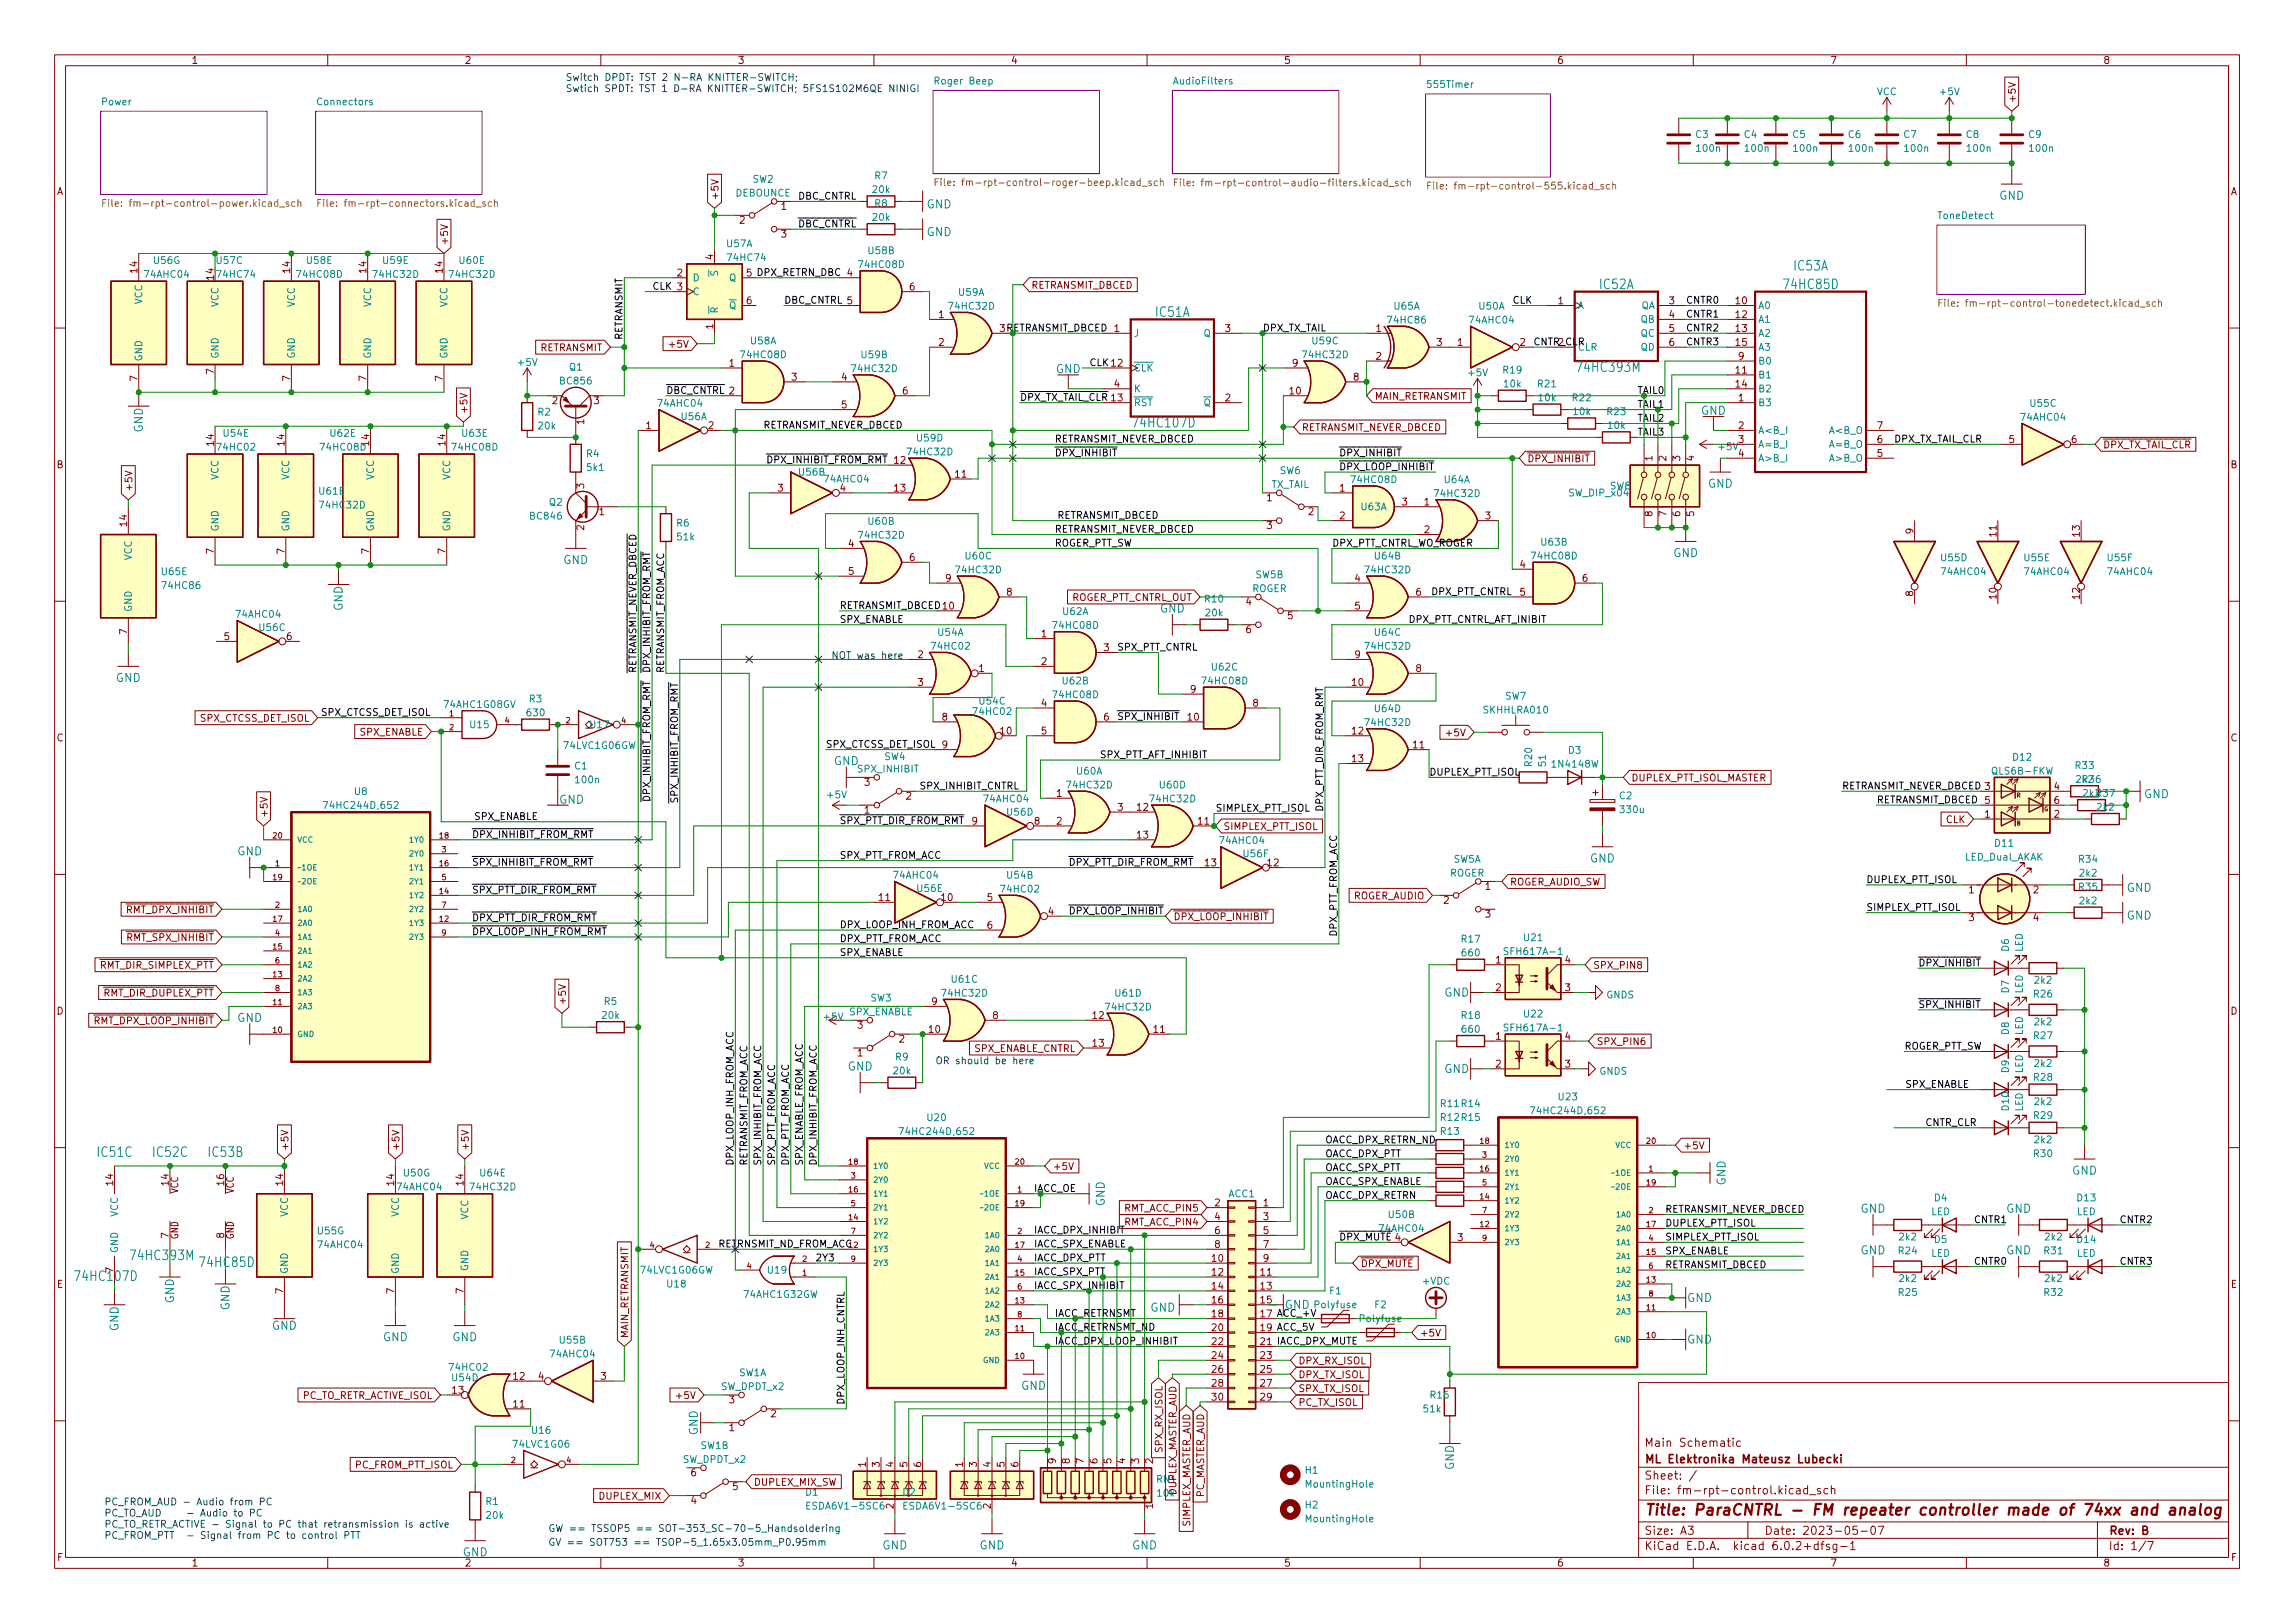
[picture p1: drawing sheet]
<svg xmlns="http://www.w3.org/2000/svg" width="420mm" height="297mm" viewBox="0 0 420 297" stroke-linecap="round" stroke-linejoin="round" font-family="sans-serif">
<defs><g id="words">
<text font-size="2.8" fill="#840000" x="301" y="277.3">Title: ParaCNTRL - FM repeater controller made of 74xx and analog</text>
<g font-size="2.5" fill="#008484">
<text x="292.9" y="52.9">IC52A</text>
<text x="326.8" y="52.9">74HC85D</text>
<text x="328.5" y="49.5">IC53A</text>
<text x="211.6" y="58">IC51A</text>
<text x="289.1" y="68.1">74HC393M</text>
<text x="207.8" y="78.2">74HC107D</text>
<text x="18" y="211.7">IC51C</text>
<text x="28.1" y="211.7">IC52C</text>
<text x="38.3" y="211.7">IC53B</text>
<text x="36.9" y="231.9">74HC85D</text>
<text x="14.1" y="234.4">74HC107D</text>
</g>
<text font-size="2.5" fill="#008400" x="24.3" y="230.6">74HC393M</text>
<g font-size="2.1" fill="#008484">
<text x="169.6" y="38.1">GND</text>
<text x="366" y="36.5">GND</text>
<text x="169.6" y="43.2">GND</text>
<text x="193.3" y="68.3">GND</text>
<text x="311.4" y="75.9">GND</text>
<text x="26.1" y="79.2" transform="rotate(-90 26.1 79.2)">GND</text>
<text x="312.6" y="89.3">GND</text>
<text x="306.3" y="102">GND</text>
<text x="103.1" y="103.2">GND</text>
<text x="62.7" y="111.8" transform="rotate(-90 62.7 111.8)">GND</text>
<text x="21.2" y="124.8">GND</text>
<text x="152.6" y="140">GND</text>
<text x="102.3" y="147.1">GND</text>
<text x="392.5" y="146.1">GND</text>
<text x="43.4" y="156.5">GND</text>
<text x="291.1" y="157.8">GND</text>
<text x="389.3" y="163.2">GND</text>
<text x="389.3" y="168.3">GND</text>
<text x="264.4" y="182.4">GND</text>
<text x="43.4" y="187">GND</text>
<text x="155.2" y="195.9">GND</text>
<text x="264.4" y="196.4">GND</text>
<text x="379.3" y="215">GND</text>
<text x="202.2" y="220.8" transform="rotate(-90 202.2 220.8)">GND</text>
<text x="315.9" y="217" transform="rotate(-90 315.9 217)">GND</text>
<text x="340.6" y="222">GND</text>
<text x="367.3" y="222">GND</text>
<text x="340.6" y="229.6">GND</text>
<text x="367.3" y="229.6">GND</text>
<text x="31.9" y="238.6" transform="rotate(-90 31.9 238.6)">GND</text>
<text x="42" y="239.8" transform="rotate(-90 42 239.8)">GND</text>
<text x="235.2" y="239.5">GND</text>
<text x="308.8" y="238.3">GND</text>
<text x="21.7" y="243.7" transform="rotate(-90 21.7 243.7)">GND</text>
<text x="49.8" y="243.4">GND</text>
<text x="70.1" y="245.5">GND</text>
<text x="82.8" y="245.5">GND</text>
<text x="210.6" y="240.1">GND</text>
<text x="308.8" y="245.9">GND</text>
<text x="186.9" y="254.4">GND</text>
<text x="127.7" y="262.7" transform="rotate(-90 127.7 262.7)">GND</text>
<text x="266.2" y="269.1" transform="rotate(-90 266.2 269.1)">GND</text>
<text x="84.7" y="284.8">GND</text>
<text x="161.5" y="283.6">GND</text>
<text x="179.3" y="283.6">GND</text>
<text x="207.2" y="283.6">GND</text>
</g>
<g font-size="2.1" fill="#840000">
<text x="212.3" y="112.1">GND</text>
<text x="301" y="267.8">ML Elektronika Mateusz Lubecki</text>
<text x="301" y="264.8">Main Schematic</text>
<text x="301" y="273.5">File: fm-rpt-control.kicad_sch</text>
<text x="301" y="270.8">Sheet: /</text>
<text x="301" y="280.9">Size: A3</text>
<text x="323" y="280.9">Date: 2023-05-07</text>
<text x="386" y="280.9">Rev: B</text>
<text x="301" y="283.7">KiCad E.D.A. kicad 6.0.2+dfsg-1</text>
<text x="386" y="283.7">Id: 1/7</text>
</g>
<g font-size="1.8" fill="#840000">
<text x="35" y="11.7">1</text>
<text x="85" y="11.7">2</text>
<text x="135" y="11.7">3</text>
<text x="185" y="11.7">4</text>
<text x="235" y="11.7">5</text>
<text x="285" y="11.7">6</text>
<text x="335" y="11.7">7</text>
<text x="385" y="11.7">8</text>
<text x="369" y="18.9" transform="rotate(-90 369 18.9)">+5V</text>
<text x="10.3" y="35.7">A</text>
<text x="408.3" y="35.7">A</text>
<text x="131.5" y="36.7" transform="rotate(-90 131.5 36.7)">+5V</text>
<text x="135.4" y="40.9">2</text>
<text x="143" y="38.4">1</text>
<text x="82" y="45" transform="rotate(-90 82 45)">+5V</text>
<text x="130.6" y="47.5" transform="rotate(-90 130.6 47.5)">4</text>
<text x="143" y="43.5">3</text>
<text x="25.1" y="49.9" transform="rotate(-90 25.1 49.9)">14</text>
<text x="39.1" y="51.2" transform="rotate(-90 39.1 51.2)">14</text>
<text x="53.1" y="49.9" transform="rotate(-90 53.1 49.9)">14</text>
<text x="67.1" y="49.9" transform="rotate(-90 67.1 49.9)">14</text>
<text x="81" y="49.9" transform="rotate(-90 81 49.9)">14</text>
<text x="124" y="50.6">2</text>
<text x="166.5" y="53.1">6</text>
<text x="188.8" y="52.8">RETRANSMIT_DBCED</text>
<text x="136.7" y="55.7">6</text>
<text x="171.8" y="58.2">1</text>
<text x="285.3" y="55.7">1</text>
<text x="305.6" y="55.7">3</text>
<text x="305.6" y="58.2">4</text>
<text x="317.8" y="55.7">10</text>
<text x="317.8" y="58.2">12</text>
<text x="98.7" y="64.3">RETRANSMIT</text>
<text x="123" y="63.6">+5V</text>
<text x="130.6" y="60.2" transform="rotate(-90 130.6 60.2)">1</text>
<text x="171.8" y="63.3">2</text>
<text x="224.3" y="60.7">3</text>
<text x="251.9" y="60.7">1</text>
<text x="251.9" y="65.8">2</text>
<text x="263" y="63.3">3</text>
<text x="266.8" y="63.3">1</text>
<text x="278.3" y="63.3">2</text>
<text x="305.6" y="60.7">5</text>
<text x="305.6" y="63.3">6</text>
<text x="317.8" y="60.7">13</text>
<text x="317.8" y="63.3">15</text>
<text x="318.3" y="65.8">9</text>
<text x="25.1" y="69.7" transform="rotate(-90 25.1 69.7)">7</text>
<text x="39.1" y="68.5" transform="rotate(-90 39.1 68.5)">7</text>
<text x="53.1" y="69.7" transform="rotate(-90 53.1 69.7)">7</text>
<text x="67.1" y="69.7" transform="rotate(-90 67.1 69.7)">7</text>
<text x="81" y="69.7" transform="rotate(-90 81 69.7)">7</text>
<text x="133.5" y="67.1">1</text>
<text x="144.9" y="69.6">3</text>
<text x="154.1" y="69.6">4</text>
<text x="204" y="70.9">4</text>
<text x="236.6" y="67.1">9</text>
<text x="247.8" y="69.6">8</text>
<text x="317.8" y="68.4">11</text>
<text x="317.8" y="70.9">14</text>
<text x="85.6" y="75.8" transform="rotate(-90 85.6 75.8)">+5V</text>
<text x="101.1" y="74">2</text>
<text x="106.9" y="77.7" transform="rotate(-90 106.9 77.7)">1</text>
<text x="108.7" y="74">3</text>
<text x="133.5" y="72.2">2</text>
<text x="154.1" y="74.7">5</text>
<text x="165.2" y="72.2">6</text>
<text x="203.5" y="73.4">13</text>
<text x="224.3" y="73.4">2</text>
<text x="236.1" y="72.2">10</text>
<text x="251.6" y="73.2">MAIN_RETRANSMIT</text>
<text x="318.3" y="73.4">1</text>
<text x="39.1" y="81.5" transform="rotate(-90 39.1 81.5)">14</text>
<text x="52.1" y="81.5" transform="rotate(-90 52.1 81.5)">14</text>
<text x="67.6" y="81.5" transform="rotate(-90 67.6 81.5)">14</text>
<text x="81.5" y="81.5" transform="rotate(-90 81.5 81.5)">14</text>
<text x="118.3" y="78.5">1</text>
<text x="129.7" y="78.5">2</text>
<text x="238.3" y="78.9">RETRANSMIT_NEVER_DBCED</text>
<text x="318.3" y="78.5">2</text>
<text x="318.3" y="81.1">3</text>
<text x="318.3" y="83.6">4</text>
<text x="343.7" y="83.6">5</text>
<text x="343.7" y="81.1">6</text>
<text x="343.7" y="78.5">7</text>
<text x="367.8" y="81.1">5</text>
<text x="379.2" y="81.1">6</text>
<text x="385" y="82">~{DPX_TX_TAIL_CLR}</text>
<text x="10.3" y="85.7">B</text>
<text x="106.9" y="89.4" transform="rotate(-90 106.9 89.4)">3</text>
<text x="142.4" y="90">3</text>
<text x="153.8" y="90">4</text>
<text x="163.7" y="90">13</text>
<text x="174.9" y="87.4">11</text>
<text x="245.3" y="90">1</text>
<text x="279.6" y="84.6">~{DPX_INHIBIT}</text>
<text x="302.5" y="84.3" transform="rotate(-90 302.5 84.3)">1</text>
<text x="305.1" y="84.3" transform="rotate(-90 305.1 84.3)">2</text>
<text x="307.6" y="84.3" transform="rotate(-90 307.6 84.3)">3</text>
<text x="310.1" y="84.3" transform="rotate(-90 310.1 84.3)">4</text>
<text x="408.3" y="85.7">B</text>
<text x="24.2" y="90" transform="rotate(-90 24.2 90)">+5V</text>
<text x="109.7" y="94.3">1</text>
<text x="231.9" y="91.7">1</text>
<text x="239.5" y="94.3">2</text>
<text x="245.3" y="95">2</text>
<text x="256.7" y="92.5">3</text>
<text x="260.7" y="92.5">1</text>
<text x="271.9" y="95">3</text>
<text x="302.5" y="94.5" transform="rotate(-90 302.5 94.5)">8</text>
<text x="305.1" y="94.5" transform="rotate(-90 305.1 94.5)">7</text>
<text x="307.6" y="94.5" transform="rotate(-90 307.6 94.5)">6</text>
<text x="310.1" y="94.5" transform="rotate(-90 310.1 94.5)">5</text>
<text x="23.2" y="96.3" transform="rotate(-90 23.2 96.3)">14</text>
<text x="39.1" y="101.4" transform="rotate(-90 39.1 101.4)">7</text>
<text x="52.1" y="101.4" transform="rotate(-90 52.1 101.4)">7</text>
<text x="67.6" y="101.4" transform="rotate(-90 67.6 101.4)">7</text>
<text x="81.5" y="101.4" transform="rotate(-90 81.5 101.4)">7</text>
<text x="106.9" y="97" transform="rotate(-90 106.9 97)">2</text>
<text x="155.3" y="100.1">4</text>
<text x="231.9" y="96.8">3</text>
<text x="260.7" y="97.6">2</text>
<text x="350.3" y="97.7" transform="rotate(-90 350.3 97.7)">9</text>
<text x="365.5" y="98.2" transform="rotate(-90 365.5 98.2)">11</text>
<text x="380.7" y="98.2" transform="rotate(-90 380.7 98.2)">13</text>
<text x="155.3" y="105.2">5</text>
<text x="166.5" y="102.7">6</text>
<text x="173.1" y="106.5">9</text>
<text x="248" y="106.5">4</text>
<text x="278.3" y="103.9">4</text>
<text x="289.7" y="106.5">6</text>
<text x="184.3" y="109">8</text>
<text x="195.8" y="110">ROGER_PTT_CNTRL_OUT</text>
<text x="228.1" y="110.8">4</text>
<text x="235.7" y="113.3">5</text>
<text x="248" y="111.5">5</text>
<text x="259.2" y="109">6</text>
<text x="278.3" y="109">5</text>
<text x="350.3" y="109.1" transform="rotate(-90 350.3 109.1)">8</text>
<text x="365.5" y="109.6" transform="rotate(-90 365.5 109.6)">10</text>
<text x="380.7" y="109.6" transform="rotate(-90 380.7 109.6)">12</text>
<text x="23.2" y="116.1" transform="rotate(-90 23.2 116.1)">7</text>
<text x="41" y="117.1">5</text>
<text x="52.5" y="117.1">6</text>
<text x="190.6" y="116.6">1</text>
<text x="202.1" y="119.2">3</text>
<text x="228.1" y="115.9">6</text>
<text x="168" y="120.4">2</text>
<text x="168" y="125.5">3</text>
<text x="179.2" y="123">1</text>
<text x="190.6" y="121.7">2</text>
<text x="247.6" y="125.5">10</text>
<text x="248" y="120.4">9</text>
<text x="259.2" y="123">8</text>
<text x="172.5" y="131.9">8</text>
<text x="190.6" y="129.3">4</text>
<text x="202.1" y="131.9">6</text>
<text x="217.9" y="126.8">9</text>
<text x="229.4" y="129.3">8</text>
<text x="10.3" y="135.7">C</text>
<text x="36.6" y="132.1">SPX_CTCSS_DET_ISOL</text>
<text x="65.8" y="134.6">SPX_ENABLE</text>
<text x="172.5" y="136.9">9</text>
<text x="183.2" y="134.4">10</text>
<text x="190.6" y="134.4">5</text>
<text x="247.6" y="134.4">12</text>
<text x="258.7" y="136.9">11</text>
<text x="265.2" y="134.7">+5V</text>
<text x="408.3" y="135.7">C</text>
<text x="158.3" y="143.8">3</text>
<text x="247.6" y="139.5">13</text>
<text x="298.6" y="143">DUPLEX_PTT_ISOL_MASTER</text>
<text x="49" y="149.7" transform="rotate(-90 49 149.7)">+5V</text>
<text x="158.3" y="148.9">1</text>
<text x="165.9" y="146.3">2</text>
<text x="193.4" y="145.8">1</text>
<text x="204.6" y="148.4">3</text>
<text x="208.2" y="148.4">12</text>
<text x="363.4" y="149.6">1</text>
<text x="376.1" y="149.6">2</text>
<text x="376.1" y="144.6">4</text>
<text x="376.1" y="147.1">6</text>
<text x="177.9" y="150.9">9</text>
<text x="189.4" y="150.9">8</text>
<text x="193.4" y="150.9">2</text>
<text x="208.2" y="153.5">13</text>
<text x="219.4" y="150.9">11</text>
<text x="223.9" y="151.9">SIMPLEX_PTT_ISOL</text>
<text x="356.3" y="150.6">CLK</text>
<text x="232.1" y="158.5">12</text>
<text x="22" y="167.1">~{RMT_DPX_INHIBIT}</text>
<text x="160.9" y="164.9">11</text>
<text x="172.4" y="164.9">10</text>
<text x="180.7" y="164.9">5</text>
<text x="191.9" y="167.4">4</text>
<text x="247.7" y="164.6">ROGER_AUDIO</text>
<text x="264.3" y="165.4">2</text>
<text x="271.9" y="162.9">1</text>
<text x="271.9" y="167.9">3</text>
<text x="276.4" y="162.1">ROGER_AUDIO_SW</text>
<text x="360.4" y="163.5">1</text>
<text x="372.3" y="163.5">2</text>
<text x="22.1" y="172.2">~{RMT_SPX_INHIBIT}</text>
<text x="180.7" y="170">6</text>
<text x="214.8" y="168.4">~{DPX_LOOP_INHIBIT}</text>
<text x="360.4" y="168.6">3</text>
<text x="372.3" y="168.6">4</text>
<text x="16.9" y="177.3">~{RMT_DIR_SIMPLEX_PTT}</text>
<text x="273.8" y="176.3">1</text>
<text x="286.5" y="176.3">4</text>
<text x="291.6" y="177.3">SPX_PIN8</text>
<text x="10.3" y="185.7">D</text>
<text x="17.5" y="182.4">~{RMT_DIR_DUPLEX_PTT}</text>
<text x="103.6" y="184" transform="rotate(-90 103.6 184)">+5V</text>
<text x="170.6" y="183.9">9</text>
<text x="273.8" y="181.4">2</text>
<text x="286.5" y="181.4">3</text>
<text x="408.3" y="185.7">D</text>
<text x="16" y="187.5">~{RMT_DPX_LOOP_INHIBIT}</text>
<text x="157" y="188.3">3</text>
<text x="164.6" y="190.8">2</text>
<text x="170.1" y="189">10</text>
<text x="181.8" y="186.5">8</text>
<text x="200.1" y="186.5">12</text>
<text x="200.1" y="191.6">13</text>
<text x="211.2" y="189">11</text>
<text x="273.8" y="190.3">1</text>
<text x="286.5" y="190.3">4</text>
<text x="292.3" y="191.3">SPX_PIN6</text>
<text x="157" y="193.3">1</text>
<text x="178.2" y="192.5">SPX_ENABLE_CNTRL</text>
<text x="273.8" y="195.4">2</text>
<text x="286.5" y="195.4">3</text>
<text x="52.8" y="210.7" transform="rotate(-90 52.8 210.7)">+5V</text>
<text x="73.1" y="210.7" transform="rotate(-90 73.1 210.7)">+5V</text>
<text x="85.8" y="210.7" transform="rotate(-90 85.8 210.7)">+5V</text>
<text x="192.7" y="214.1">+5V</text>
<text x="308.1" y="210.3">+5V</text>
<text x="20.7" y="216.9" transform="rotate(-90 20.7 216.9)">14</text>
<text x="30.9" y="216.9" transform="rotate(-90 30.9 216.9)">14</text>
<text x="32.6" y="218.5" transform="rotate(-90 32.6 218.5)">VCC</text>
<text x="41" y="216.9" transform="rotate(-90 41 216.9)">16</text>
<text x="42.8" y="218.5" transform="rotate(-90 42.8 218.5)">VCC</text>
<text x="51.8" y="216.9" transform="rotate(-90 51.8 216.9)">14</text>
<text x="72.1" y="216.9" transform="rotate(-90 72.1 216.9)">14</text>
<text x="84.8" y="216.9" transform="rotate(-90 84.8 216.9)">14</text>
<text x="206" y="221.7">RMT_ACC_PIN5</text>
<text x="222.4" y="220.8">2</text>
<text x="231.3" y="220.8">1</text>
<text x="30.9" y="226.6" transform="rotate(-90 30.9 226.6)">7</text>
<text x="32.6" y="226.8" transform="rotate(-90 32.6 226.8)">GND</text>
<text x="41" y="226.6" transform="rotate(-90 41 226.6)">8</text>
<text x="42.8" y="226.8" transform="rotate(-90 42.8 226.8)">GND</text>
<text x="206" y="224.3">RMT_ACC_PIN4</text>
<text x="222.4" y="223.3">4</text>
<text x="222.4" y="225.8">6</text>
<text x="231.3" y="223.3">3</text>
<text x="231.3" y="225.8">5</text>
<text x="255.4" y="227.1">4</text>
<text x="266.8" y="227.1">3</text>
<text x="20.7" y="232.9" transform="rotate(-90 20.7 232.9)">7</text>
<text x="221.9" y="230.9">10</text>
<text x="221.9" y="233.5">12</text>
<text x="222.4" y="228.4">8</text>
<text x="230.8" y="233.5">11</text>
<text x="231.3" y="228.4">7</text>
<text x="231.3" y="230.9">9</text>
<text x="249.1" y="231.9">~{DPX_MUTE}</text>
<text x="10.4" y="235.7">E</text>
<text x="51.8" y="236.7" transform="rotate(-90 51.8 236.7)">7</text>
<text x="72.1" y="236.7" transform="rotate(-90 72.1 236.7)">7</text>
<text x="84.8" y="236.7" transform="rotate(-90 84.8 236.7)">7</text>
<text x="221.9" y="236">14</text>
<text x="221.9" y="238.5">16</text>
<text x="230.8" y="236">13</text>
<text x="230.8" y="238.5">15</text>
<text x="408.4" y="235.7">E</text>
<text x="115" y="245" transform="rotate(-90 115 245)">MAIN_RETRANSMIT</text>
<text x="221.9" y="241.1">18</text>
<text x="221.9" y="243.6">20</text>
<text x="259.9" y="244.6">+5V</text>
<text x="221.9" y="246.2">22</text>
<text x="221.9" y="248.7">24</text>
<text x="221.9" y="251.2">26</text>
<text x="230.8" y="248.7">23</text>
<text x="230.8" y="251.2">25</text>
<text x="237.6" y="249.7">DPX_RX_ISOL</text>
<text x="54.9" y="256">PC_TO_RETR_ACTIVE_ISOL</text>
<text x="82.8" y="255.1">13</text>
<text x="94" y="257.6">11</text>
<text x="94" y="252.5">12</text>
<text x="98.6" y="252.5">4</text>
<text x="110" y="252.5">3</text>
<text x="124.3" y="256">+5V</text>
<text x="133.5" y="256.8">3</text>
<text x="221.9" y="253.8">28</text>
<text x="221.9" y="256.3">30</text>
<text x="230.8" y="253.8">27</text>
<text x="230.8" y="256.3">29</text>
<text x="237.6" y="254.8">SPX_TX_ISOL</text>
<text x="237.6" y="257.3">PC_TX_ISOL</text>
<text x="237.6" y="252.2">DPX_TX_ISOL</text>
<text x="133.5" y="261.9">1</text>
<text x="141.1" y="259.4">2</text>
<text x="64.9" y="268.7">PC_FROM_PTT_ISOL</text>
<text x="158.5" y="268.5" transform="rotate(-90 158.5 268.5)">1</text>
<text x="161" y="268.5" transform="rotate(-90 161 268.5)">3</text>
<text x="163.6" y="268.5" transform="rotate(-90 163.6 268.5)">4</text>
<text x="166.1" y="268.5" transform="rotate(-90 166.1 268.5)">5</text>
<text x="168.7" y="268.5" transform="rotate(-90 168.7 268.5)">6</text>
<text x="176.3" y="268.5" transform="rotate(-90 176.3 268.5)">1</text>
<text x="178.8" y="268.5" transform="rotate(-90 178.8 268.5)">3</text>
<text x="181.4" y="268.5" transform="rotate(-90 181.4 268.5)">4</text>
<text x="183.9" y="268.5" transform="rotate(-90 183.9 268.5)">5</text>
<text x="186.4" y="268.5" transform="rotate(-90 186.4 268.5)">6</text>
<text x="193.3" y="267.9" transform="rotate(-90 193.3 267.9)">9</text>
<text x="195.8" y="267.9" transform="rotate(-90 195.8 267.9)">8</text>
<text x="198.4" y="267.9" transform="rotate(-90 198.4 267.9)">7</text>
<text x="200.9" y="267.9" transform="rotate(-90 200.9 267.9)">6</text>
<text x="203.5" y="267.9" transform="rotate(-90 203.5 267.9)">5</text>
<text x="206" y="267.9" transform="rotate(-90 206 267.9)">4</text>
<text x="208.5" y="267.9" transform="rotate(-90 208.5 267.9)">3</text>
<text x="211.1" y="267.9" transform="rotate(-90 211.1 267.9)">2</text>
<text x="212.8" y="265.7" transform="rotate(-90 212.8 265.7)">SPX_RX_ISOL</text>
<text x="109.8" y="274.4">DUPLEX_MIX</text>
<text x="126.5" y="275.2">4</text>
<text x="126.5" y="270.2">6</text>
<text x="134.1" y="272.7">5</text>
<text x="138" y="271.9">DUPLEX_MIX_SW</text>
<text x="211.8" y="271.4">RN1</text>
<text x="211.9" y="273.9">10k</text>
<text x="215.4" y="274" transform="rotate(-90 215.4 274)">DUPLEX_MASTER_AUD</text>
<text x="220.4" y="274.4" transform="rotate(-90 220.4 274.4)">PC_MASTER_AUD</text>
<text x="163.6" y="276.1" transform="rotate(-90 163.6 276.1)">2</text>
<text x="181.4" y="276.1" transform="rotate(-90 181.4 276.1)">2</text>
<text x="211.1" y="276.1" transform="rotate(-90 211.1 276.1)">1</text>
<text x="217.9" y="279.7" transform="rotate(-90 217.9 279.7)">SIMPLEX_MASTER_AUD</text>
<text x="10.4" y="285.7">F</text>
<text x="35" y="286.7">1</text>
<text x="85" y="286.7">2</text>
<text x="135" y="286.7">3</text>
<text x="185" y="286.7">4</text>
<text x="235" y="286.7">5</text>
<text x="285" y="286.7">6</text>
<text x="335" y="286.7">7</text>
<text x="385" y="286.7">8</text>
<text x="408.4" y="285.7">F</text>
</g>
<g font-size="1.8" fill="#0000c2">
<text x="103.5" y="14.8">Switch DPDT: TST 2 N-RA KNITTER-SWITCH;</text>
<text x="103.5" y="16.8">Swtich SPDT: TST 1 D-RA KNITTER-SWITCH; 5FS1S102M6QE NINIGI</text>
<text x="152.1" y="120.6">NOT was here</text>
<text x="171.2" y="194.8">OR should be here</text>
<text x="19" y="275.5">PC_FROM_AUD - Audio from PC</text>
<text x="19" y="277.5">PC_TO_AUD - Audio to PC</text>
<text x="19" y="279.6">PC_TO_RETR_ACTIVE - Signal to PC that retransmission is active</text>
<text x="19" y="281.6">PC_FROM_PTT - Signal from PC to control PTT</text>
<text x="100.3" y="280.4">GW == TSSOP5 == SOT-353_SC-70-5_Handsoldering</text>
<text x="100.3" y="282.9">GV == SOT753 == TSOP-5_1.65x3.05mm_P0.95mm</text>
</g>
<g font-size="1.8" fill="#008484">
<text x="171.4" y="15.4">Roger Beep</text>
<text x="215.1" y="15.4">AudioFilters</text>
<text x="261.6" y="16.1">555Timer</text>
<text x="343.6" y="17.4">VCC</text>
<text x="355.3" y="17.4">+5V</text>
<text x="18.7" y="19.3">Power</text>
<text x="58.2" y="19.3">Connectors</text>
<text x="310.4" y="25.2">C3</text>
<text x="310.7" y="27.8">100n</text>
<text x="319.3" y="25.2">C4</text>
<text x="319.6" y="27.8">100n</text>
<text x="328.2" y="25.2">C5</text>
<text x="328.5" y="27.8">100n</text>
<text x="338.4" y="25.2">C6</text>
<text x="338.7" y="27.8">100n</text>
<text x="348.5" y="25.2">C7</text>
<text x="348.8" y="27.8">100n</text>
<text x="360" y="25.2">C8</text>
<text x="360.2" y="27.8">100n</text>
<text x="371.4" y="25.2">C9</text>
<text x="371.7" y="27.8">100n</text>
<text x="134.6" y="36">DEBOUNCE</text>
<text x="137.8" y="33.4">SW2</text>
<text x="159.8" y="35.3">20k</text>
<text x="160.2" y="32.8">R7</text>
<text x="159.8" y="40.4">20k</text>
<text x="160.2" y="37.9">R8</text>
<text x="355" y="40.1">ToneDetect</text>
<text x="133.1" y="45.2">U57A</text>
<text x="133.4" y="47.8">74HC74</text>
<text x="159" y="46.5">U58B</text>
<text x="26.6" y="50.8">74AHC04</text>
<text x="28.2" y="48.3">U56G</text>
<text x="39.9" y="50.8">74HC74</text>
<text x="54.5" y="50.8">74HC08D</text>
<text x="56.2" y="48.3">U58E</text>
<text x="68.5" y="50.8">74HC32D</text>
<text x="70.2" y="48.3">U59E</text>
<text x="82.5" y="50.8">74HC32D</text>
<text x="84.1" y="48.3">U60E</text>
<text x="126.7" y="51.5">D</text>
<text x="133.5" y="51.5">Q</text>
<text x="157.4" y="49">74HC08D</text>
<text x="26" y="55.7" transform="rotate(-90 26 55.7)">VCC</text>
<text x="40" y="56.2" transform="rotate(-90 40 56.2)">VCC</text>
<text x="54" y="56.2" transform="rotate(-90 54 56.2)">VCC</text>
<text x="67.9" y="56.2" transform="rotate(-90 67.9 56.2)">VCC</text>
<text x="81.9" y="56.2" transform="rotate(-90 81.9 56.2)">VCC</text>
<text x="126.7" y="54">C</text>
<text x="131.4" y="57.4" transform="rotate(-90 131.4 57.4)">~{R}</text>
<text x="132.1" y="56.6">~{Q}</text>
<text x="173.9" y="56.7">74HC32D</text>
<text x="175.5" y="54.1">U59A</text>
<text x="254.3" y="59.2">74HC86</text>
<text x="255.2" y="56.7">U65A</text>
<text x="269.2" y="59.2">74AHC04</text>
<text x="270.8" y="56.7">U50A</text>
<text x="288.8" y="56.6">A</text>
<text x="300.4" y="56.6">QA</text>
<text x="300.4" y="59.1">QB</text>
<text x="321.8" y="56.6">A0</text>
<text x="321.8" y="59.1">A1</text>
<text x="40" y="65.7" transform="rotate(-90 40 65.7)">GND</text>
<text x="54" y="65.7" transform="rotate(-90 54 65.7)">GND</text>
<text x="67.9" y="65.7" transform="rotate(-90 67.9 65.7)">GND</text>
<text x="81.9" y="65.7" transform="rotate(-90 81.9 65.7)">GND</text>
<text x="135.8" y="65.5">74HC08D</text>
<text x="137.4" y="63">U58A</text>
<text x="157.8" y="65.6">U59B</text>
<text x="207.5" y="61.6">J</text>
<text x="220.4" y="61.6">Q</text>
<text x="238.7" y="65.5">74HC32D</text>
<text x="240.3" y="63">U59C</text>
<text x="300.4" y="61.6">QC</text>
<text x="300.4" y="64.2">QD</text>
<text x="321.8" y="61.6">A2</text>
<text x="321.8" y="64.2">A3</text>
<text x="26" y="66.2" transform="rotate(-90 26 66.2)">GND</text>
<text x="94.9" y="66.9">+5V</text>
<text x="102.7" y="70.3">BC856</text>
<text x="104.2" y="67.8">Q1</text>
<text x="156.1" y="68.1">74HC32D</text>
<text x="207.5" y="68">~{CLK}</text>
<text x="207.5" y="71.8">K</text>
<text x="268.9" y="68.9">+5V</text>
<text x="275.2" y="68.3">R19</text>
<text x="275.4" y="70.9">10k</text>
<text x="281.6" y="70.9">R21</text>
<text x="321.8" y="69.3">B1</text>
<text x="321.8" y="71.8">B2</text>
<text x="321.8" y="66.7">B0</text>
<text x="98.5" y="76">R2</text>
<text x="120.6" y="74.4">74AHC04</text>
<text x="124.7" y="76.9">U56A</text>
<text x="207.5" y="74.3">~{RST}</text>
<text x="219" y="74.3">~{Q}</text>
<text x="281.7" y="73.4">10k</text>
<text x="287.9" y="73.4">R22</text>
<text x="288.1" y="76">10k</text>
<text x="294.3" y="76">R23</text>
<text x="321.8" y="74.3">B3</text>
<text x="370.1" y="77">74AHC04</text>
<text x="371.8" y="74.4">U55C</text>
<text x="39.9" y="82.5">74HC02</text>
<text x="41" y="79.9">U54E</text>
<text x="58.9" y="82.5">74HC08D</text>
<text x="60.5" y="79.9">U62E</text>
<text x="83" y="82.5">74HC08D</text>
<text x="84.7" y="79.9">U63E</text>
<text x="98.6" y="78.6">20k</text>
<text x="107.4" y="83.7">R4</text>
<text x="166.3" y="83.3">74HC32D</text>
<text x="167.9" y="80.8">U59D</text>
<text x="294.4" y="78.5">10k</text>
<text x="314.7" y="82.4">+5V</text>
<text x="321.8" y="79.4">A&lt;B_I</text>
<text x="321.8" y="82">A=B_I</text>
<text x="335.2" y="82">A=B_O</text>
<text x="335.2" y="79.4">A&lt;B_O</text>
<text x="40" y="87.8" transform="rotate(-90 40 87.8)">VCC</text>
<text x="53" y="87.8" transform="rotate(-90 53 87.8)">VCC</text>
<text x="68.5" y="87.8" transform="rotate(-90 68.5 87.8)">VCC</text>
<text x="82.4" y="87.8" transform="rotate(-90 82.4 87.8)">VCC</text>
<text x="107.5" y="86.2">5k1</text>
<text x="146.3" y="87">U56B</text>
<text x="151.1" y="88.3">74AHC04</text>
<text x="232.6" y="89.3">TX_TAIL</text>
<text x="234.3" y="86.8">SW6</text>
<text x="247.6" y="88.4">74HC08D</text>
<text x="264.4" y="88.4">U64A</text>
<text x="294.7" y="89.6">SW8</text>
<text x="321.8" y="84.5">A&gt;B_I</text>
<text x="335.2" y="84.5">A&gt;B_O</text>
<text x="58.5" y="90.5">U61E</text>
<text x="58.7" y="93.1">74HC32D</text>
<text x="97.2" y="95.1">BC846</text>
<text x="100.6" y="92.5">Q2</text>
<text x="249.2" y="93.4">U63A</text>
<text x="262.8" y="90.9">74HC32D</text>
<text x="287.3" y="90.8">SW_DIP_x04</text>
<text x="40" y="97.3" transform="rotate(-90 40 97.3)">GND</text>
<text x="53" y="97.3" transform="rotate(-90 53 97.3)">GND</text>
<text x="68.5" y="97.3" transform="rotate(-90 68.5 97.3)">GND</text>
<text x="82.4" y="97.3" transform="rotate(-90 82.4 97.3)">GND</text>
<text x="123.9" y="96.4">R6</text>
<text x="124" y="98.9">51k</text>
<text x="157.4" y="98.6">74HC32D</text>
<text x="159" y="96">U60B</text>
<text x="282.2" y="99.8">U63B</text>
<text x="24.1" y="102.6" transform="rotate(-90 24.1 102.6)">VCC</text>
<text x="29.7" y="105.2">U65E</text>
<text x="29.9" y="107.8">74HC86</text>
<text x="175.2" y="104.9">74HC32D</text>
<text x="176.8" y="102.4">U60C</text>
<text x="229.9" y="105.8">SW5B</text>
<text x="250.1" y="104.9">74HC32D</text>
<text x="251.7" y="102.4">U64B</text>
<text x="280.6" y="102.4">74HC08D</text>
<text x="355.4" y="102.7">U55D</text>
<text x="355.6" y="105.2">74AHC04</text>
<text x="370.6" y="102.7">U55E</text>
<text x="370.8" y="105.2">74AHC04</text>
<text x="385.9" y="102.7">U55F</text>
<text x="386" y="105.2">74AHC04</text>
<text x="24.1" y="112.1" transform="rotate(-90 24.1 112.1)">GND</text>
<text x="43.4" y="113">74AHC04</text>
<text x="194.6" y="112.5">U62A</text>
<text x="220.6" y="110.3">R10</text>
<text x="220.8" y="112.8">20k</text>
<text x="229.2" y="108.3">ROGER</text>
<text x="47.5" y="115.5">U56C</text>
<text x="170.7" y="118.9">74HC02</text>
<text x="171.7" y="116.4">U54A</text>
<text x="193" y="115.1">74HC08D</text>
<text x="250.1" y="118.9">74HC32D</text>
<text x="251.7" y="116.4">U64C</text>
<text x="194.6" y="125.2">U62B</text>
<text x="220.3" y="125.2">74HC08D</text>
<text x="221.9" y="122.7">U62C</text>
<text x="81.4" y="129.6">74AHC1G08GV</text>
<text x="96.6" y="131.1">630</text>
<text x="96.9" y="128.5">R3</text>
<text x="178.4" y="130.8">74HC02</text>
<text x="179.3" y="128.9">U54C</text>
<text x="193" y="127.8">74HC08D</text>
<text x="251.7" y="130.3">U64D</text>
<text x="271.7" y="130.6">SKHHLRA010</text>
<text x="275.6" y="128">SW7</text>
<text x="86.1" y="133.3">U15</text>
<text x="103.3" y="137.1">74LVC1G06GW</text>
<text x="108.1" y="133.3">U17</text>
<text x="250.1" y="132.9">74HC32D</text>
<text x="287.2" y="137.9">D3</text>
<text x="105.2" y="140.8">C1</text>
<text x="105.5" y="143.3">100n</text>
<text x="157.1" y="141.4">SPX_INHIBIT</text>
<text x="161.9" y="139.1">SW4</text>
<text x="197.1" y="141.8">U60A</text>
<text x="280.5" y="140.2" transform="rotate(-90 280.5 140.2)">R20</text>
<text x="283" y="140.2" transform="rotate(-90 283 140.2)">51</text>
<text x="284.4" y="140.5">1N4148W</text>
<text x="364.9" y="141.7">QLS6B-FKW</text>
<text x="368.6" y="139.2">D12</text>
<text x="380" y="140.7">R33</text>
<text x="380.2" y="143.3">2k2</text>
<text x="59.9" y="148">74HC244D,652</text>
<text x="64.9" y="145.5">U8</text>
<text x="151.5" y="146.1">+5V</text>
<text x="180.3" y="146.8">74AHC04</text>
<text x="184.4" y="149.3">U56D</text>
<text x="195.5" y="144.3">74HC32D</text>
<text x="210.7" y="146.8">74HC32D</text>
<text x="212.4" y="144.3">U60D</text>
<text x="296.5" y="146.3">C2</text>
<text x="296.7" y="148.8">330u</text>
<text x="381.4" y="145.8">2k2R37</text>
<text x="384" y="148.4">2k2</text>
<text x="223.4" y="154.4">74AHC04</text>
<text x="365.3" y="155">D11</text>
<text x="163.8" y="160.8">74AHC04</text>
<text x="184.4" y="160.8">U54B</text>
<text x="227.7" y="156.9">U56F</text>
<text x="265.4" y="160.4">ROGER</text>
<text x="266" y="157.9">SW5A</text>
<text x="359.7" y="157.5">LED_Dual_AKAK</text>
<text x="380.6" y="157.9">R34</text>
<text x="380.8" y="160.4">2k2</text>
<text x="168" y="163.2">U56E</text>
<text x="183.4" y="163.3">74HC02</text>
<text x="380.6" y="163">R35</text>
<text x="380.8" y="165.5">2k2</text>
<text x="267.6" y="172.5">R17</text>
<text x="279" y="172.2">U21</text>
<text x="174.3" y="179.9">U61C</text>
<text x="267.8" y="175">660</text>
<text x="276" y="174.8">SFH617A-1</text>
<text x="367.8" y="174.1" transform="rotate(-90 367.8 174.1)">D6</text>
<text x="370.3" y="174.2" transform="rotate(-90 370.3 174.2)">LED</text>
<text x="110.6" y="183.9">R5</text>
<text x="155.4" y="185.8">SPX_ENABLE</text>
<text x="159.4" y="183.3">SW3</text>
<text x="172.6" y="182.4">74HC32D</text>
<text x="202.6" y="184.9">74HC32D</text>
<text x="204.2" y="182.4">U61D</text>
<text x="294.1" y="182.7">GNDS</text>
<text x="367.8" y="181.7" transform="rotate(-90 367.8 181.7)">D7</text>
<text x="370.3" y="181.9" transform="rotate(-90 370.3 181.9)">LED</text>
<text x="372.4" y="182.6">R26</text>
<text x="372.5" y="180">2k2</text>
<text x="110.3" y="186.5">20k</text>
<text x="150.9" y="186.7">+5V</text>
<text x="267.6" y="186.5">R18</text>
<text x="267.8" y="189">660</text>
<text x="276" y="188.7">SFH617A-1</text>
<text x="279" y="186.2">U22</text>
<text x="367.8" y="189.3" transform="rotate(-90 367.8 189.3)">D8</text>
<text x="370.3" y="189.5" transform="rotate(-90 370.3 189.5)">LED</text>
<text x="372.4" y="190.2">R27</text>
<text x="372.5" y="187.6">2k2</text>
<text x="163.6" y="196.6">20k</text>
<text x="164" y="194.1">R9</text>
<text x="292.8" y="196.7">GNDS</text>
<text x="367.8" y="196.3" transform="rotate(-90 367.8 196.3)">D9</text>
<text x="370.3" y="196.5" transform="rotate(-90 370.3 196.5)">LED</text>
<text x="372.4" y="197.8">R28</text>
<text x="372.5" y="195.3">2k2</text>
<text x="263.8" y="202.6">R11 R14</text>
<text x="280.9" y="203.9">74HC244D,652</text>
<text x="285.4" y="201.4">U23</text>
<text x="367.8" y="203.2" transform="rotate(-90 367.8 203.2)">D10</text>
<text x="370.3" y="203.5" transform="rotate(-90 370.3 203.5)">LED</text>
<text x="372.5" y="202.2">2k2</text>
<text x="165.4" y="207.7">74HC244D,652</text>
<text x="169.8" y="205.2">U20</text>
<text x="263.8" y="207.7">R13</text>
<text x="263.8" y="205.1">R12 R15</text>
<text x="372.4" y="204.8">R29</text>
<text x="372.5" y="209.2">2k2</text>
<text x="73.9" y="215.3">U50G</text>
<text x="88" y="215.3">U64E</text>
<text x="372.4" y="211.8">R30</text>
<text x="72.9" y="217.8">74AHC04</text>
<text x="86.3" y="217.8">74HC32D</text>
<text x="224.9" y="219.1">ACC1</text>
<text x="354.2" y="219.9">D4</text>
<text x="380.3" y="219.9">D13</text>
<text x="21.6" y="222.7" transform="rotate(-90 21.6 222.7)">VCC</text>
<text x="52.7" y="222.7" transform="rotate(-90 52.7 222.7)">VCC</text>
<text x="58.2" y="225.9">U55G</text>
<text x="73" y="222.7" transform="rotate(-90 73 222.7)">VCC</text>
<text x="85.7" y="223.2" transform="rotate(-90 85.7 223.2)">VCC</text>
<text x="254.3" y="222.9">U50B</text>
<text x="347.8" y="227">2k2</text>
<text x="353.5" y="222.4">LED</text>
<text x="354.2" y="227.5">D5</text>
<text x="374.4" y="227">2k2</text>
<text x="380.2" y="222.4">LED</text>
<text x="380.3" y="227.5">D14</text>
<text x="21.6" y="229.4" transform="rotate(-90 21.6 229.4)">GND</text>
<text x="52.7" y="233.2" transform="rotate(-90 52.7 233.2)">GND</text>
<text x="58.4" y="228.4">74AHC04</text>
<text x="73" y="233.2" transform="rotate(-90 73 233.2)">GND</text>
<text x="85.7" y="232.7" transform="rotate(-90 85.7 232.7)">GND</text>
<text x="117.4" y="233.1">74LVC1G06GW</text>
<text x="140.6" y="233.1">U19</text>
<text x="347.6" y="229.5">R24</text>
<text x="353.5" y="230">LED</text>
<text x="374.3" y="229.5">R31</text>
<text x="380.2" y="230">LED</text>
<text x="122.2" y="235.6">U18</text>
<text x="136.3" y="237.5">74AHC1G32GW</text>
<text x="240.8" y="239.4">Polyfuse</text>
<text x="243.4" y="236.9">F1</text>
<text x="251.7" y="239.4">F2</text>
<text x="260.5" y="235.1">+VDC</text>
<text x="347.6" y="237.2">R25</text>
<text x="347.8" y="234.6">2k2</text>
<text x="374.3" y="237.2">R32</text>
<text x="374.4" y="234.6">2k2</text>
<text x="102.5" y="245.9">U55B</text>
<text x="249" y="242">Polyfuse</text>
<text x="82.5" y="250.9">74HC02</text>
<text x="100.9" y="248.4">74AHC04</text>
<text x="135.2" y="251.9">SW1A</text>
<text x="82.8" y="252.8">U54D</text>
<text x="132" y="254.4">SW_DPDT_x2</text>
<text x="261.9" y="255.9">R16</text>
<text x="97.4" y="262.4">U16</text>
<text x="260.7" y="258.5">51k</text>
<text x="94.1" y="264.9">74LVC1G06</text>
<text x="125" y="267.7">SW_DPDT_x2</text>
<text x="128.3" y="265.2">SW1B</text>
<text x="239" y="269.7">H1</text>
<text x="89" y="275.4">R1</text>
<text x="147.5" y="273.7">D1</text>
<text x="165.3" y="273.7">D2</text>
<text x="239.3" y="272.2">MountingHole</text>
<text x="89.1" y="278">20k</text>
<text x="148.2" y="276.3">ESDA6V1-5SC6</text>
<text x="166" y="276.3">ESDA6V1-5SC6</text>
<text x="239" y="276.1">H2</text>
<text x="239.3" y="278.6">MountingHole</text>
</g>
<g font-size="1.8" fill="#848400">
<text x="174.7" y="34">File: fm-rpt-control-roger-beep.kicad_sch</text>
<text x="218.8" y="34.1">File: fm-rpt-control-audio-filters.kicad_sch</text>
<text x="264.4" y="34.7">File: fm-rpt-control-555.kicad_sch</text>
<text x="21.6" y="37.8">File: fm-rpt-control-power.kicad_sch</text>
<text x="60.4" y="37.8">File: fm-rpt-connectors.kicad_sch</text>
<text x="358.1" y="56.1">File: fm-rpt-control-tonedetect.kicad_sch</text>
</g>
<g font-size="1.8">
<text x="146" y="41.6">~{DBC_CNTRL}</text>
<text x="146" y="36.5">DBC_CNTRL</text>
<text x="119.4" y="53">CLK 3</text>
<text x="136.7" y="50.6">5 DPX_RETRN_DBC 4</text>
<text x="143.5" y="55.6">DBC_CNTRL 5</text>
<text x="276.9" y="55.6">CLK</text>
<text x="308.6" y="58.1">CNTR1</text>
<text x="308.6" y="55.6">CNTR0</text>
<text x="114" y="62.3" transform="rotate(-90 114 62.3)">RETRANSMIT</text>
<text x="285.3" y="63.3">2</text>
<text x="288.8" y="64.2">CLR</text>
<text x="308.6" y="63.2">CNTR3</text>
<text x="308.6" y="60.6">CNTR2</text>
<text x="199.4" y="67">CLK 12</text>
<text x="121.9" y="72.1">~{DBC_CNTRL}</text>
<text x="186.7" y="73.3">~{DPX_TX_TAIL_CLR}</text>
<text x="299.7" y="77.2">TAIL2</text>
<text x="299.7" y="74.6">TAIL1</text>
<text x="299.7" y="72.1">TAIL0</text>
<text x="139.7" y="78.4">RETRANSMIT_NEVER_DBCED</text>
<text x="193" y="83.5">~{DPX_INHIBIT}</text>
<text x="193" y="81">RETRANSMIT_NEVER_DBCED</text>
<text x="245.1" y="83.5">~{DPX_INHIBIT}</text>
<text x="299.7" y="79.7">TAIL3</text>
<text x="346.7" y="81">DPX_TX_TAIL_CLR</text>
<text x="139.2" y="84.8">~{DPX_INHIBIT_FROM_RMT} 12</text>
<text x="245.1" y="86">~{DPX_LOOP_INHIBIT}</text>
<text x="193.5" y="94.9">RETRANSMIT_DBCED</text>
<text x="193" y="97.5">RETRANSMIT_NEVER_DBCED</text>
<text x="193" y="100">ROGER_PTT_SW</text>
<text x="243.8" y="100">DPX_PTT_CNTRL_WO_ROGER</text>
<text x="153.7" y="114">SPX_ENABLE</text>
<text x="153.7" y="111.4">RETRANSMIT_DBCED10</text>
<text x="257.8" y="114">DPX_PTT_CNTRL_AFT_INIBIT</text>
<text x="261.9" y="108.9">DPX_PTT_CNTRL</text>
<text x="204.5" y="119.1">SPX_PTT_CNTRL</text>
<text x="116.5" y="123.2" transform="rotate(-90 116.5 123.2)">~{RETRANSMIT_NEVER_DBCED}</text>
<text x="121.6" y="123.2" transform="rotate(-90 121.6 123.2)">RETRANSMIT_FROM_ACC</text>
<text x="58.7" y="131">SPX_CTCSS_DET_ISOL</text>
<text x="204.5" y="131.8">~{SPX_INHIBIT}10</text>
<text x="151.1" y="136.8">SPX_CTCSS_DET_ISOL</text>
<text x="201.3" y="138.8">SPX_PTT_AFT_INHIBIT</text>
<text x="261.6" y="141.9">DUPLEX_PTT_ISOL</text>
<text x="119" y="146.8" transform="rotate(-90 119 146.8)">~{DPX_INHIBIT_FROM_RMT}~{DPX_INHIBIT_FROM_RMT}</text>
<text x="124.1" y="147.1" transform="rotate(-90 124.1 147.1)">~{SPX_INHIBIT_FROM_RMT}</text>
<text x="168.3" y="144.5">SPX_INHIBIT_CNTRL</text>
<text x="222.5" y="148.5">SIMPLEX_PTT_ISOL</text>
<text x="242.2" y="148.6" transform="rotate(-90 242.2 148.6)">DPX_PTT_DIR_FROM_RMT</text>
<text x="337.2" y="144.5">RETRANSMIT_NEVER_DBCED 3</text>
<text x="343.5" y="147">RETRANSMIT_DBCED 5</text>
<text x="86.4" y="153.4">~{DPX_INHIBIT_FROM_RMT}</text>
<text x="86.8" y="150.1">SPX_ENABLE</text>
<text x="153.7" y="150.8">~{SPX_PTT_DIR_FROM_RMT}</text>
<text x="86.4" y="158.4">~{SPX_INHIBIT_FROM_RMT}</text>
<text x="153.7" y="157.2">SPX_PTT_FROM_ACC</text>
<text x="195.6" y="158.4">~{DPX_PTT_DIR_FROM_RMT}13</text>
<text x="341.6" y="161.6">DUPLEX_PTT_ISOL</text>
<text x="86.4" y="163.5">~{SPX_PTT_DIR_FROM_RMT}</text>
<text x="195.6" y="167.3">~{DPX_LOOP_INHIBIT}</text>
<text x="341.6" y="166.7">SIMPLEX_PTT_ISOL</text>
<text x="86.4" y="168.6">~{DPX_PTT_DIR_FROM_RMT}</text>
<text x="86.4" y="171.1">~{DPX_LOOP_INH_FROM_RMT}</text>
<text x="153.7" y="172.4">DPX_PTT_FROM_ACC</text>
<text x="153.7" y="169.9">DPX_LOOP_INH_FROM_ACC</text>
<text x="244.8" y="171.5" transform="rotate(-90 244.8 171.5)">DPX_PTT_FROM_ACC</text>
<text x="153.7" y="174.9">SPX_ENABLE</text>
<text x="351.2" y="176.9">~{DPX_INHIBIT}</text>
<text x="351.2" y="184.5">~{SPX_INHIBIT}</text>
<text x="348.6" y="192.1">ROGER_PTT_SW</text>
<text x="348.7" y="199.1">SPX_ENABLE</text>
<text x="242.6" y="209.2">OACC_DPX_RETRN_ND</text>
<text x="352.4" y="206.1">CNTR_CLR</text>
<text x="134.3" y="213.4" transform="rotate(-90 134.3 213.4)">DPX_LOOP_INH_FROM_ACC</text>
<text x="136.8" y="213.4" transform="rotate(-90 136.8 213.4)">RETRANSMIT_FROM_ACC</text>
<text x="139.4" y="213.4" transform="rotate(-90 139.4 213.4)">SPX_INHIBIT_FROM_ACC</text>
<text x="141.9" y="213.4" transform="rotate(-90 141.9 213.4)">SPX_PTT_FROM_ACC</text>
<text x="144.4" y="213.4" transform="rotate(-90 144.4 213.4)">DPX_PTT_FROM_ACC</text>
<text x="147" y="213.4" transform="rotate(-90 147 213.4)">SPX_ENABLE_FROM_ACC</text>
<text x="149.5" y="213.4" transform="rotate(-90 149.5 213.4)">DPX_INHIBIT_FROM_ACC</text>
<text x="242.6" y="214.3">OACC_SPX_PTT</text>
<text x="242.6" y="211.8">OACC_DPX_PTT</text>
<text x="242.6" y="216.9">OACC_SPX_ENABLE</text>
<text x="242.6" y="219.4">OACC_DPX_RETRN</text>
<text x="304.8" y="221.9">RETRANSMIT_NEVER_DBCED</text>
<text x="189.2" y="225.7">IACC_DPX_INHIBIT</text>
<text x="245.1" y="227">~{DPX_MUTE}</text>
<text x="252.7" y="225.5">74AHC04</text>
<text x="304.8" y="224.5">DUPLEX_PTT_ISOL</text>
<text x="304.8" y="227">SIMPLEX_PTT_ISOL</text>
<text x="361.3" y="223.8">CNTR1</text>
<text x="388" y="223.8">CNTR2</text>
<text x="131.4" y="228.3">RETRNSMIT_ND_FROM_ACC</text>
<text x="149.2" y="230.8">2Y3</text>
<text x="189.2" y="228.3">IACC_SPX_ENABLE</text>
<text x="189.2" y="230.8">IACC_DPX_PTT</text>
<text x="304.8" y="229.6">SPX_ENABLE</text>
<text x="304.8" y="232.1">RETRANSMIT_DBCED</text>
<text x="361.3" y="231.5">CNTR0</text>
<text x="388" y="231.5">CNTR3</text>
<text x="230.8" y="241.1">17 ACC_+V</text>
<text x="230.8" y="243.6">19 ACC_5V</text>
<text x="193" y="246.1">IACC_DPX_LOOP_INHIBIT</text>
<text x="230.8" y="246.2">21 IACC_DPX_MUTE</text>
<text x="154.6" y="256.9" transform="rotate(-90 154.6 256.9)">DPX_LOOP_INH_CNTRL</text>
</g>
<g font-size="1.8" fill="#008400">
<text x="39.7" y="48.3">U57C</text>
<text x="183" y="60.7">3RETRANSMIT_DBCED 1</text>
<text x="231.1" y="60.6">DPX_TX_TAIL</text>
<text x="280.7" y="63.2">CNTR_CLR</text>
<text x="189.2" y="218.1">IACC_OE</text>
<text x="189.2" y="233.4">IACC_SPX_PTT</text>
<text x="189.2" y="235.9">IACC_SPX_INHIBIT</text>
<text x="193" y="243.5">IACC_RETRNSMT_ND</text>
<text x="193" y="241">IACC_RETRNSMT</text>
</g>
<g font-size="1.4" fill="#840000">
<text x="82.3" y="131.1">1</text>
<text x="82.3" y="133.6">2</text>
<text x="92.4" y="132.4">4</text>
<text x="103.6" y="132.4">2</text>
<text x="113.8" y="132.4">4</text>
<text x="50" y="153.5">20</text>
<text x="80.5" y="153.5">18</text>
<text x="80.9" y="156">3</text>
<text x="50" y="161.1">19</text>
<text x="50.4" y="158.5">1</text>
<text x="80.5" y="158.5">16</text>
<text x="80.9" y="161.1">5</text>
<text x="50.4" y="166.2">2</text>
<text x="80.5" y="163.6">14</text>
<text x="80.9" y="166.2">7</text>
<text x="50" y="173.8">15</text>
<text x="50" y="168.7">17</text>
<text x="50.4" y="171.2">4</text>
<text x="80.5" y="168.7">12</text>
<text x="80.9" y="171.2">9</text>
<text x="50" y="178.9">13</text>
<text x="50.4" y="176.3">6</text>
<text x="50" y="183.9">11</text>
<text x="50.4" y="181.4">8</text>
<text x="50" y="189">10</text>
<text x="271" y="209.3">18</text>
<text x="301.5" y="209.3">20</text>
<text x="155.4" y="213.1">18</text>
<text x="155.8" y="215.7">3</text>
<text x="185.9" y="213.1">20</text>
<text x="271" y="214.4">16</text>
<text x="271.4" y="211.9">3</text>
<text x="301.9" y="214.4">1</text>
<text x="155.4" y="218.2">16</text>
<text x="155.8" y="220.8">5</text>
<text x="185.9" y="220.8">19</text>
<text x="186.3" y="218.2">1</text>
<text x="271" y="219.5">14</text>
<text x="271.4" y="217">5</text>
<text x="301.5" y="217">19</text>
<text x="155.4" y="223.3">14</text>
<text x="155.8" y="225.8">7</text>
<text x="186.3" y="225.8">2</text>
<text x="271" y="224.6">12</text>
<text x="271.4" y="222">7</text>
<text x="271.4" y="227.1">9</text>
<text x="301.5" y="224.6">17</text>
<text x="301.9" y="222">2</text>
<text x="301.9" y="227.1">4</text>
<text x="119" y="228.4">4</text>
<text x="129.1" y="228.4">2</text>
<text x="136.8" y="232.2">4</text>
<text x="146.9" y="233.5">1</text>
<text x="146.9" y="230.9">2</text>
<text x="155.4" y="228.4">12</text>
<text x="155.8" y="230.9">9</text>
<text x="185.9" y="233.5">15</text>
<text x="185.9" y="228.4">17</text>
<text x="186.3" y="230.9">4</text>
<text x="301.5" y="229.7">15</text>
<text x="301.9" y="232.2">6</text>
<text x="185.9" y="238.5">13</text>
<text x="186.3" y="236">6</text>
<text x="301.5" y="239.8">11</text>
<text x="301.5" y="234.7">13</text>
<text x="301.9" y="237.3">8</text>
<text x="185.9" y="243.6">11</text>
<text x="186.3" y="241.1">8</text>
<text x="301.5" y="244.9">10</text>
<text x="185.9" y="248.7">10</text>
<text x="93.6" y="267.8">2</text>
<text x="103.7" y="267.8">4</text>
</g>
<g font-size="1.4" fill="#008484">
<text x="54.4" y="154.2">VCC</text>
<text x="75.2" y="154.2">1Y0</text>
<text x="54.4" y="159.3">~1OE</text>
<text x="54.4" y="161.8">~2OE</text>
<text x="75.2" y="159.3">1Y1</text>
<text x="75.2" y="156.8">2Y0</text>
<text x="75.2" y="161.8">2Y1</text>
<text x="54.4" y="166.9">1A0</text>
<text x="75.2" y="164.4">1Y2</text>
<text x="75.2" y="166.9">2Y2</text>
<text x="54.4" y="169.5">2A0</text>
<text x="54.4" y="172">1A1</text>
<text x="75.2" y="169.5">1Y3</text>
<text x="75.2" y="172">2Y3</text>
<text x="54.4" y="179.6">2A2</text>
<text x="54.4" y="174.5">2A1</text>
<text x="54.4" y="177.1">1A2</text>
<text x="54.4" y="184.7">2A3</text>
<text x="54.4" y="182.2">1A3</text>
<text x="54.4" y="189.8">GND</text>
<text x="159.8" y="213.9">1Y0</text>
<text x="180.1" y="213.9">VCC</text>
<text x="275.3" y="215.2">1Y1</text>
<text x="275.3" y="210.1">1Y0</text>
<text x="275.3" y="212.6">2Y0</text>
<text x="295.7" y="210.1">VCC</text>
<text x="295.9" y="215.2">~1OE</text>
<text x="159.8" y="219">1Y1</text>
<text x="159.8" y="216.4">2Y0</text>
<text x="159.8" y="221.5">2Y1</text>
<text x="180.3" y="219">~1OE</text>
<text x="180.3" y="221.5">~2OE</text>
<text x="275.3" y="220.3">1Y2</text>
<text x="275.3" y="217.7">2Y1</text>
<text x="295.9" y="217.7">~2OE</text>
<text x="159.8" y="224.1">1Y2</text>
<text x="159.8" y="226.6">2Y2</text>
<text x="180.5" y="226.6">1A0</text>
<text x="275.3" y="225.3">1Y3</text>
<text x="275.3" y="222.8">2Y2</text>
<text x="275.3" y="227.9">2Y3</text>
<text x="296.1" y="225.3">2A0</text>
<text x="296.1" y="222.8">1A0</text>
<text x="296.1" y="227.9">1A1</text>
<text x="159.8" y="229.1">1Y3</text>
<text x="159.8" y="231.7">2Y3</text>
<text x="180.5" y="229.1">2A0</text>
<text x="180.5" y="231.7">1A1</text>
<text x="296.1" y="230.4">2A1</text>
<text x="296.1" y="233">1A2</text>
<text x="180.5" y="239.3">2A2</text>
<text x="180.5" y="234.2">2A1</text>
<text x="180.5" y="236.8">1A2</text>
<text x="296.1" y="235.5">2A2</text>
<text x="296.1" y="238">1A3</text>
<text x="180.5" y="244.4">2A3</text>
<text x="180.5" y="241.8">1A3</text>
<text x="295.6" y="245.7">GND</text>
<text x="296.1" y="240.6">2A3</text>
<text x="180" y="249.5">GND</text>
</g>
<g font-size="1.1" fill="#840000">
<text x="369.2" y="145.9">R</text>
<text x="374.2" y="148.4">G</text>
<text x="369.2" y="151.1">B</text>
</g>
</g></defs>
<g fill="none" stroke="#840000" stroke-width=".18">
<path d="M10 10h400v277h-400zM12 12h396v273h-396zM60 10v2M110 10v2M160 10v2M210 10v2M260 10v2M310 10v2M345.4 17.8l-.7 1.3M345.4 17.8v2.6M345.4 17.8l.8 1.3M356.9 17.8v2.6"/>
<path d="M356.9 17.8l-.8 1.3M356.9 17.8l.7 1.3M360 10v2M367 14.1h2.6v5.1l-1.3 1.2-1.3-1.2zM367.7 15.1l1.3 .4-1.3 .4M129.5 31.9h2.6v5.1l-1.3 1.1-1.3-1.1zM130.2 32.9l1.3 .4-1.3 .4M134.6 39.4h2.6M141.4 37.1l-3.2 2.1M142.2 36.9h2.6M157.5 36.9h1.2M163.8 36.9h1.3"/>
<path d="M166.4 36.9h2.5M168.9 35v3.8M307.3 21.6v2.8M307.3 26.5v2.7M316.2 21.6v2.8M316.2 26.5v2.7M325.1 21.6v2.8M325.1 26.5v2.7M335.3 21.6v2.8M335.3 26.5v2.7M345.4 21.6v2.8M345.4 26.5v2.7"/>
<path d="M356.9 21.6v2.8M356.9 26.5v2.7M366.4 33.7h3.8M368.3 21.6v2.8M368.3 26.5v2.7M368.3 31.2v2.5M25.4 46.4v5.1M53.3 46.4v5.1M67.3 46.4v5.1M80 40.1h2.6v5.2l-1.3 1.1-1.3-1.1zM80.7 41.1l1.2 .5-1.2 .4M81.3 46.4v5.1"/>
<path d="M123.2 50.8h2.5M123.2 53.4h2.5M125.7 52.7l1.3 .7-1.3 .6M130.8 45.8v2.5M130.8 58.5v2.5M135.9 55.9h2.5M135.9 50.8h2.5M142.2 41.9h2.6M153.7 55.9h3.8M153.7 50.8h3.8M163.8 41.9h1.3M165.1 53.4h3.8"/>
<path d="M166.4 41.9h2.5M168.9 40v3.9M170.2 58.5h4.3M177.2 57.2h-3.2a6.6 6.6 0 0 1 0 7.6h3.2M188.4 50.8h19.8v2.6h-19.8l-1.1-1.3zM257.2 59.7h-3.2a6.6 6.6 0 0 1 0 7.6h3.2M283.2 55.9h5.1M303.5 55.9h5.1M303.5 58.5h5.1M316.2 55.9h5.1M316.2 58.5h5.1M10 60h2"/>
<path d="M23.5 74.3h3.8M25.4 66.7v7.6M39.4 66.7v2.6M39.4 78v5.1M52.3 78v5.1M53.3 66.7v5.1M67.3 66.7v5.1M67.8 78v5.1M81.3 66.7v5.1M81.8 78v5.1M83.6 71h2.5v5.1l-1.3 1.2-1.2-1.2zM84.2 72l1.3 .4-1.3 .4"/>
<path d="M96.5 67.3l-.7 1.3M96.5 67.3v2.6M96.5 72.4v1.3M96.5 78.8v1.2M96.5 67.3l.8 1.3M98.1 62.3h12.5l1.2 1.2-1.2 1.3h-12.5zM100.3 72.4h2.6l1.9 1.9M105.4 74.3v7M110.5 72.4h-2.6l-1.9 1.9M116.8 78.8h3.8M121.4 61.6h5.1l1.1 1.3-1.1 1.3h-5.1zM129.5 78.8h2.6"/>
<path d="M132.1 72.4h3.8M132.1 67.3h3.8M143.5 69.9h3.8M152.4 75h4.3M152.4 69.9h4.3M159.4 68.6h-3.2a6.6 6.6 0 0 1 0 7.6h3.2M163.8 72.4h3.8M170.2 63.5h4.3M181.6 61h3.8M193.7 68.6h3.8M195.6 68.6v2.6M201.9 61h5.1"/>
<path d="M201.9 73.7h5.1M201.9 71.2h5.1M201.9 67.3h5.1M222.2 61h5.1M222.2 73.7h5.1M234.9 72.4h4.4M234.9 67.3h4.4M238 76.9h26.7v2.5h-26.7l-1.1-1.3zM241.9 66.1h-3.1a6.6 6.6 0 0 1 0 7.6h3.1M246.4 69.9h3.8M250.2 66.1h4.4M250.2 61h4.4"/>
<path d="M251.3 71.2h18v2.5h-18l-1.1-1.3zM261.6 63.5h7.6M270.5 69.3l-.8 1.2M270.5 69.3v2.5M270.5 69.3l.8 1.2M273 72.4h1.3M278.1 63.5h2.6M279.4 72.4h1.3M279.4 75h1.3M283.2 63.5h5.1M285.7 77.5h1.3M285.7 75h1.3"/>
<path d="M292.1 77.5h1.3M303.5 63.5h5.1M303.5 61h5.1M311.8 76.2h3.8M313.7 76.2v2.6M316.2 63.5h5.1M316.2 66.1h5.1M316.2 61h5.1M316.2 73.7h5.1M316.2 68.6h5.1M316.2 71.2h5.1M316.2 78.8h5.1"/>
<path d="M341.6 78.8h5.1M408 60h2M22.2 85.2h2.6v5.2l-1.3 1.1-1.3-1.1zM22.9 86.2l1.3 .4-1.3 .5M23.5 92.7v5.1M39.4 98.3v5.1M52.3 98.3v5.1M67.8 98.3v5.1M81.8 98.3v5.1M105.4 86.4v3.8l1.9 1.9M107.3 93.4l-1.9 1.9v5.1M107.3 92.7h5.7"/>
<path d="M121.9 92.7v1.3M121.9 99.1v1.3M141 90.2h3.8M153.7 90.2h2.5M160.7 99.1h-3.2a6.6 6.6 0 0 1 0 7.6h3.2M162.6 90.2h4.3M162.6 85.1h4.3M169.5 83.9h-3.1a6.6 6.6 0 0 1 0 7.6h3.1M174 87.7h3.8M231.1 90.2h2.6M231.1 95.3h2.6M234.6 90.5l3.1 2"/>
<path d="M238.8 92.7h2.5M243.8 90.2h3.8M243.8 95.3h3.8M255.3 92.7h8.1M259.1 97.8h4.3M266.1 91.5h-3.2a6.6 6.6 0 0 1 0 7.6h3.2M270.5 95.3h3.8M279.2 82.6h12.7v2.5h-12.7l-1.1-1.2zM292.1 80h1.3M298.4 80h1.3M300.9 87.4l-1.1 3.9M301 81.3v5.1"/>
<path d="M301 91.5v5.1M303.4 87.4l-1 3.9M303.5 81.3v5.1M303.5 91.5v5.1M305.9 87.4l-1 3.9M306.1 81.3v5.1M306.1 91.5v5.1M306.7 99.1h3.8M308.5 87.4l-1.1 3.9M308.6 81.3v5.1M308.6 91.5v7.6M311.1 81.3l1.3 .8"/>
<path d="M311.1 81.3h2.6M312.4 80.6l-1.3 .7M313.1 86.4h3.8M315 83.9v2.5M316.2 81.3h5.1M316.2 83.9h5.1M341.6 81.3h5.1M341.6 83.9h5.1M350.5 95.3v3.8M365.8 95.3v3.8M366.4 81.3h3.8M379.1 81.3h2.5"/>
<path d="M381 95.3v3.8M384.7 80h17.3v2.6h-17.3l-1.2-1.3zM10 110h2M23.5 113.1v5M23.5 119.4v2.6M39.6 117.4h3.8M52.3 117.4h2.6M60.1 107h3.8M62 104.4v2.6M103.5 100.4h3.8M153.7 100.4h4.3M153.7 105.4h4.3"/>
<path d="M165.1 102.9h3.8M171.4 106.7h4.4M171.4 111.8h4.4M173.4 119.4h-3.2a6.6 6.6 0 0 1 0 7.6h3.2M178.4 105.4h-3.1a6.6 6.6 0 0 1 0 7.7h3.1M182.9 109.3h3.8M189.2 116.9h3.8M195.4 108h23.2l1.1 1.3-1.1 1.2h-23.2zM200.7 119.4h3.8M214.6 112.4v3.8M214.6 114.3h2.6M218.4 114.3h1.3"/>
<path d="M224.8 114.3h1.3M227.3 109.3h2.6M227.3 114.3h2.6M230.8 109.5l3.1 2M234.9 111.8h2.6M246.4 106.7h4.3M246.4 111.8h4.3M253.4 105.4h-3.2a6.6 6.6 0 0 1 0 7.7h3.2M253.4 119.4h-3.2a6.6 6.6 0 0 1 0 7.6h3.2M257.8 109.3h3.8M276.9 109.3h3.8M276.9 104.2h3.8"/>
<path d="M288.3 106.7h3.8M350.5 108v2.5M365.8 108v2.5M381 108v2.5M408 110h2M21.6 122h3.8M35.7 130.1h21.4l1.1 1.3-1.1 1.2h-21.4zM64.9 132.6h13l1.1 1.3-1.1 1.3h-13zM80.8 131.4h3.8M80.8 133.9h3.8M90.9 132.6h4.6M100.6 132.6h1.3"/>
<path d="M102.1 132.6h3.8M102.1 137.2v2.8M107.2 132.6l.6-.6 .7 .6-.7 .7zM107.2 133.3h1.3M113.5 132.6h2.6M166.4 125.8h4.3M166.4 120.7h4.3M170.8 132.1h4.3M170.8 137.2h4.3M177.8 130.8h-3.2a6.6 6.6 0 0 1 0 7.7h3.2M179.1 123.2h2.5M183.5 134.7h2.6"/>
<path d="M189.2 122h3.8M189.2 134.7h3.8M189.2 129.6h3.8M200.7 132.1h3.8M216.5 132.1h3.8M216.5 127h3.8M228 129.6h3.8M246.4 125.8h4.3M246.4 120.7h4.3M246.4 134.7h4.3M246.4 139.7h4.3M253.4 133.4h-3.2a6.6 6.6 0 0 1 0 7.6h3.2"/>
<path d="M257.8 123.2h3.8M257.8 137.2h3.8M263.6 132.8h5.2l1.1 1.2-1.1 1.3h-5.2zM272.4 134h2.6M275 132.8h5M277.5 131v1.8M280 134h2.6M45.7 158.8h7.6M45.7 156.9v3.8M47 144.9h2.5v5.2l-1.2 1.1-1.3-1.1zM47.7 145.9l1.2 .4-1.2 .5M48.3 153.7h5"/>
<path d="M78.7 158.8h5.1M78.7 153.7h5.1M78.7 156.2h5.1M100.2 147.4h3.8M102.1 142v5.4M152.4 147.4h2.5M152.4 147.4l1.3 .7M153.7 146.6l-1.3 .8M154.9 142.3h5.1M154.9 140.4v3.8M157.5 147.4h2.5M164.1 145.1l-3.2 2"/>
<path d="M165.1 144.8h2.5M176.5 151.2h3.8M189.2 151.2h6.9M191.8 146.1h4.3M198.8 144.8h-3.2a6.6 6.6 0 0 1 0 7.6h3.2M203.2 148.6h8.1M207 153.7h4.3M214 147.4h-3.2a6.6 6.6 0 0 1 0 7.6h3.2M218.4 151.2h3.8M219.7 158.8h3.8M223.6 149.9h18.5v2.5h-18.5l-1.1-1.2zM232.4 158.8h2.5"/>
<path d="M283.2 142.3h8.9M291.1 146.3h4.6v.5h-4.6zM291.5 155h3.8M291.6 145.1h1M292.1 144.6v1M293.4 143.5v2.8M293.4 148.4v2.8M293.4 152.4v2.6M298.3 141h25.9v2.5h-25.9l-1.1-1.2zM355.4 148.6h4.8l1.1 1.3-1.1 1.3h-4.8zM362.6 147.4h15.2M362.6 144.8h16.5"/>
<path d="M362.6 149.9h15.2M367.7 142.8l.7-.3-.2 .8M367.7 147.9l.7-.3-.2 .8M368.4 147.6l-1 1M368.4 142.5l-1 1M368.7 147.9l.7-.3-.2 .8M368.7 142.8l.7-.3-.2 .8M369.4 147.6l-1 1M369.4 142.5l-1 1M370.6 158.7v-.8h-.8h.8l-1.5 1.5M371.9 159.7v-.8h-.8h.8l-1.6 1.5M372.7 145.3l.8-.2-.2 .7"/>
<path d="M373.5 145.1l-1 1M373.8 145.3l.7-.2-.2 .7M374.5 145.1l-1 1M379.1 147.4h1.3M381.6 149.9h1.3M388 149.9h1.3M389.3 144.8h2.5M391.8 142.9v3.8M10 160h2M17.4 175.3h22.1l1.1 1.3-1.1 1.2h-22.1zM22.2 165.1h17.3l1.1 1.3-1.1 1.3h-17.3zM22.2 170.2h17.3l1.1 1.3-1.1 1.3h-17.3z"/>
<path d="M48.3 168.9h5M48.3 179.1h5M48.3 174h5M48.3 161.3h5M48.3 166.4h5M48.3 171.5h5M48.3 176.6h5M78.7 168.9h5.1M78.7 163.9h5.1M78.7 161.3h5.1M78.7 166.4h5.1M78.7 171.5h5.1"/>
<path d="M101.6 179.2h2.5v5.1l-1.2 1.2-1.3-1.2zM160 165.1h3.8M172.7 165.1h2.6M179.1 165.1h4.3M179.1 170.2h4.3M186.1 163.9h-3.2a6.6 6.6 0 0 1 0 7.6h3.2M191.8 167.7h2.5M214.5 166.4h18.6v2.5h-18.6l-1.1-1.2zM247 162.6h14.1l1.2 1.3-1.2 1.2h-14.1zM263.5 163.9h2.6M265.4 176.6h1.3M269.2 179.7v3.9"/>
<path d="M270.3 161.6l-3.2 2M271.1 161.3h2.6M271.1 166.4h2.6M271.8 176.6h6.3v3.8v-1.9M276.1 160.1h17.7v2.5h-17.7l-1.1-1.3zM278.1 179.7v1.9h-5.1M280.2 179.6h1.2l-.3 .1v-.2l.3 .1M280.2 178.6h1.2l-.3 .1v-.2l.3 .1M288.3 176.6h-3.2l-1.9 1.9M291.3 175.3h10.3v2.5h-10.3l-1.1-1.2zM359.4 162h15.2M359.4 167h15.2"/>
<path d="M362.6 177.2h8.9M369.7 175.7v-.8h-.8h.8l-1.5 1.5M371 175.7v-.8h-.8h.8l-1.6 1.5M376.6 177.2h1.2M378.5 162h1.2M378.5 167h1.2M384.8 162h3.8M384.8 167h3.8M388.6 160.1v3.8M388.6 165.1v3.8M408 160h2M16.2 185.5h23.3l1.1 1.2-1.1 1.3h-23.3z"/>
<path d="M18.1 180.4h21.4l1.1 1.2-1.1 1.3h-21.4zM45.7 189.3h7.6M45.7 187.4v3.8M48.3 184.2h5M48.3 181.6h5M102.3 180.2l1.2 .4-1.2 .4M107.9 188h1.3M114.3 188h1.3M151.8 186.7l1.2 .8M156.2 186.7h2.5M156.2 191.8h2.5M157.5 196.3v3.8"/>
<path d="M157.5 198.2h2.5M161.3 198.2h1.3M162.8 189.5l-3.2 2.1M163.8 189.3h2.6M167.6 198.2h1.3M168.9 189.3h4.3M168.9 184.2h4.3M175.9 182.9h-3.2a6.6 6.6 0 0 1 0 7.6h3.2M177.5 190.5h19.8l1.1 1.3-1.1 1.3h-19.8zM180.3 186.7h3.8M198.9 186.7h4.3M198.9 191.8h4.3"/>
<path d="M205.9 185.5h-3.2a6.6 6.6 0 0 1 0 7.6h3.2M210.3 189.3h3.8M265.4 190.5h1.3M269.2 181.6h2.6M269.2 193.7v3.8M269.2 195.6h2.6M271.8 190.5h6.3v3.8v-1.9M278.1 193.7v1.9h-5.1M280.2 193.6h1.2l-.3 .1v-.2l.3 .1M280.2 192.6h1.2l-.3 .1v-.3l.3 .2M285.1 181.6h3.2M285.1 195.6h3.2"/>
<path d="M288.3 190.5h-3.2l-1.9 1.9M289.6 195.6h1.2v-1.3l1.3 1.3-1.3 1.3v-1.3M290.8 181.6h1.3v-1.2l1.3 1.2-1.3 1.3v-1.3M291.9 189.3h10.4v2.5h-10.4l-1.1-1.3zM362.6 184.8h8.9M362.6 192.4h8.9M362.6 199.4h8.9M369.7 183.3v-.8h-.8h.8l-1.5 1.6M369.7 190.9v-.7h-.8h.8l-1.5 1.5M369.7 197.9v-.8h-.8h.8l-1.5 1.6M371 183.3v-.8h-.8h.8l-1.6 1.6M371 190.9v-.7h-.8h.8l-1.6 1.5"/>
<path d="M371 197.9v-.8h-.8h.8l-1.6 1.6M376.6 184.8h1.2M376.6 192.4h1.2M376.6 199.4h1.2M10 210h2M21 213.4v5.1M31.1 213.4v5.1M41.3 213.4v5.1M50.8 205.9h2.5v5.1l-1.2 1.1-1.3-1.1zM51.5 206.9l1.2 .4-1.2 .4M52.1 213.4v5.1M71.1 205.9h2.6v5.1l-1.3 1.1-1.3-1.1z"/>
<path d="M71.8 206.9l1.3 .4-1.3 .4M72.4 213.4v5.1M83.8 205.9h2.6v5.1l-1.3 1.1-1.3-1.1zM84.5 206.9l1.3 .4-1.3 .4M85.1 213.4v5.1M153.7 218.5h5M153.7 213.4h5M153.7 215.9h5M184.1 218.5h5.1M184.1 213.4h5.1M192.4 212.1h5.1v2.6h-5.1l-1.1-1.3zM195.7 212.8l.4 1.3 .4-1.3"/>
<path d="M196.8 218.5h2.6M199.4 216.6v3.8M204.9 219.7h15l1.1 1.3-1.1 1.3h-15zM261.6 217.2h1.3M261.6 219.7h1.3M261.6 214.7h1.3M261.6 212.1h1.3M268 209.6h6.3M268 217.2h6.3M268 219.7h6.3M268 214.7h6.3M268 212.1h6.3"/>
<path d="M299.7 209.6h5.1M299.7 217.2h5.1M299.7 214.7h5.1M307.8 208.3h5.2v2.6h-5.2l-1.1-1.3zM310.5 214.7h2.6M311.1 209l.4 1.3 .5-1.3M313.1 212.8v3.8M362.6 206.4h8.9M369.7 204.9v-.8h-.8h.8l-1.5 1.5M371 204.9v-.8h-.8h.8l-1.6 1.5M376.6 206.4h1.2M379.7 212.1h3.8"/>
<path d="M381.6 209.6v2.5M408 210h2M19 238.8h3.9M21 229.9v5.1M21 236.3v2.5M29.2 233.7h3.8M31.1 223.6v5M31.1 231.2v2.5M39.4 235h3.8M41.3 223.6v5M41.3 232.4v2.6M52.1 233.7v7.6"/>
<path d="M72.4 233.7v5.1M85.1 233.7v5.1M113 227.3h2.6v18l-1.3 1.1-1.3-1.1zM117.5 228.6h2.5M125.1 228.6l.6-.6 .7 .6-.7 .7zM125.1 229.3h1.3M127.6 228.6h3.8M135.3 232.4h3.8M144.8 231.2h4.4M144.8 233.7h4.4M153.7 228.6h5M153.7 231.2h5"/>
<path d="M153.7 223.6h5M153.7 221h5M153.7 226.1h5M184.1 228.6h5.1M184.1 231.2h5.1M184.1 233.7h5.1M184.1 238.8h5.1M184.1 221h5.1M184.1 226.1h5.1M184.1 236.3h5.1M204.9 222.3h15l1.1 1.3-1.1 1.2h-15zM215.9 238.8h2.5"/>
<path d="M215.9 236.9v3.8M221 228.6h3.8M221 231.2h3.8M221 233.7h3.8M221 238.8h3.8M221 223.6h3.8M221 221h3.8M221 226.1h3.8M221 236.3h3.8M224.8 238.7h1.3v.2h-1.3zM224.8 236.1h1.3v.3h-1.3zM224.8 233.6h1.3v.2h-1.3z"/>
<path d="M224.8 231h1.3v.3h-1.3zM224.8 228.5h1.3v.3h-1.3zM224.8 226h1.3v.2h-1.3zM224.8 223.4h1.3v.3h-1.3zM224.8 220.9h1.3v.2h-1.3zM228.6 238.7h1.3v.2h-1.3zM228.6 236.1h1.3v.3h-1.3zM228.6 233.6h1.3v.2h-1.3zM228.6 231h1.3v.3h-1.3zM228.6 228.5h1.3v.3h-1.3zM228.6 226h1.3v.2h-1.3zM228.6 223.4h1.3v.3h-1.3z"/>
<path d="M228.6 220.9h1.3v.2h-1.3zM229.9 228.6h3.8M229.9 231.2h3.8M229.9 233.7h3.8M229.9 238.8h5M229.9 223.6h3.8M229.9 221h3.8M229.9 226.1h3.8M229.9 236.3h3.8M234.9 236.9v3.8M247 239.8h-1l-3 3.1h-1.1M248.8 229.9h10.8v2.5h-10.8l-1.2-1.2z"/>
<path d="M262.9 239.4v1.3M265.4 227.4h8.9M269.2 224.8h5.1M269.2 222.3h5.1M299.7 232.4h5.1M299.7 224.8h5.1M299.7 235h5.1M299.7 229.9h5.1M299.7 222.3h5.1M299.7 227.4h5.1M299.7 237.5h5.1M306.1 237.5h2.5"/>
<path d="M308.6 235.6v3.8M342.9 222.3v3.8M342.9 229.9v3.8M342.9 224.2h3.8M342.9 231.8h3.8M351.8 224.2h8.9M351.8 231.8h8.9M353.8 232.6l-1.5 1.5h.8h-.8v-.8M353.8 225l-1.5 1.5h.8h-.8v-.8M355.1 232.6l-1.5 1.5h.7h-.7v-.8M355.1 225l-1.5 1.5h.7h-.7v-.8M369.6 224.2h3.8"/>
<path d="M369.6 231.8h3.8M369.6 222.3v3.8M369.6 229.9v3.8M378.5 224.2h8.8M378.5 231.8h8.8M380.5 225l-1.5 1.5h.7h-.7v-.8M380.5 232.6l-1.5 1.5h.7h-.7v-.8M381.8 225l-1.6 1.5h.8h-.8v-.8M381.8 232.6l-1.6 1.5h.8h-.8v-.8M50.2 241.3h3.8M54.6 254h24.9l1.1 1.3-1.1 1.3h-24.9zM70.5 242.6h3.8"/>
<path d="M72.4 240.1v2.5M81.9 255.3h2.6M83.2 242.6h3.8M85.1 240.1v2.5M90.2 251.5h3.1a6.7 6.7 0 0 0 0 7.6h-3.1M92.8 257.8h4.4M92.8 252.8h6.9M108.6 252.8h3.8M122.7 254h5.1l1.1 1.3-1.1 1.3h-5.1zM128.3 258.5v3.8M132.7 255.3h2.6M139.3 258.1l-3.2 2"/>
<path d="M140.3 257.8h2.6M184.1 243.9h5.1M184.1 249h5.1v2.5M184.1 241.3h5.1M187.3 251.5h3.8M210.8 253.2l1.3-1.1 1.3 1.1v13.6h-2.6zM213.4 253.2l1.2-1.1 1.3 1.1v21.3h-2.5zM215.9 258.3l1.3-1.1 1.2 1.1v22h-2.5zM218.4 258.3l1.3-1.1 1.3 1.1v16.6h-2.6zM221 243.9h3.8M221 249h3.8M221 241.3h3.8"/>
<path d="M221 246.4h3.8M221 251.5h3.8M221 254h3.8M221 256.6h3.8M224.8 256.4h1.3v.3h-1.3zM224.8 253.9h1.3v.3h-1.3zM224.8 251.4h1.3v.2h-1.3zM224.8 248.8h1.3v.3h-1.3zM224.8 246.3h1.3v.2h-1.3zM224.8 243.7h1.3v.3h-1.3zM224.8 241.2h1.3v.3h-1.3zM228.6 256.4h1.3v.3h-1.3z"/>
<path d="M228.6 253.9h1.3v.3h-1.3zM228.6 251.4h1.3v.2h-1.3zM228.6 248.8h1.3v.3h-1.3zM228.6 246.3h1.3v.2h-1.3zM228.6 243.7h1.3v.3h-1.3zM228.6 241.2h1.3v.3h-1.3zM229.9 243.9h3.8M229.9 249h3.8M229.9 241.3h3.8M229.9 246.4h3.8M229.9 251.5h3.8M229.9 254h3.8"/>
<path d="M229.9 256.6h3.8M237.3 247.7h13.6v2.5h-13.6l-1.1-1.2zM237.3 252.8h13.3v2.5h-13.3l-1.1-1.3zM237.3 255.3h12.1v2.5h-12.1l-1.1-1.2zM237.3 250.2h13.3v2.6h-13.3l-1.1-1.3zM240.7 241.3h7.6M248.9 243.9h7.6M255.3 242.4h-1l-3.1 3h-1M259.6 242.6h5.1v2.5h-5.1l-1.2-1.2zM262.9 243.3l.4 1.2 .4-1.2M265.4 252.8v1.2M265.4 259.1v1.3"/>
<path d="M299.7 245.1h5.1M299.7 240.1h5.1M300 253h108v32h-108zM306.1 245.1h2.5M308.6 243.2v3.9M10 260h2M64.1 266.7h19.2l1.2 1.3-1.2 1.3h-19.2zM87 271.8v1.3M87 278.2v3.8M92.1 268h3.8M97.2 268l.6-.6 .6 .6-.6 .6zM97.2 268.6h1.2"/>
<path d="M103.5 268h2.5M108.7 272.5h12.7l1.2 1.2-1.2 1.3h-12.7zM125.7 273.7h2.6M125.7 268.6h2.6M128.3 260.4h2.5M132.3 271.4l-3.1 2.1M132.7 260.4h2.6M133.3 271.2h2.6M137.6 269.9h16.4v2.6h-16.4l-1.1-1.3zM158.1 271.2h1.3v.2M158.7 271.2l.7 1.3h-1.3zM158.7 266.7v7h10.2v-7"/>
<path d="M160.7 271.2h1.2v.2M161.3 271.2l.6 1.3h-1.2zM161.3 266.7v7M163.2 271.2h1.3v.2M163.8 271.2l.7 1.3h-1.3zM163.8 266.7v10.2M163.8 278.2v2.5M165.7 271.2h1.3v.2M166.4 271.2l.6 1.3h-1.3zM166.4 266.7v7M168.3 271.2h1.2v.2M168.9 271.2l.6 1.3h-1.2z"/>
<path d="M175.9 271.2h1.3v.2M176.5 271.2l.7 1.3h-1.3zM176.5 266.7v7h10.2v-7M178.4 271.2h1.3v.2M179.1 271.2l.6 1.3h-1.3zM179.1 266.7v7M181 271.2h1.2v.2M181.6 271.2l.6 1.3h-1.2zM181.6 266.7v10.2M181.6 278.2v2.5M183.5 271.2h1.3v.2M184.1 271.2l.7 1.3h-1.3z"/>
<path d="M184.1 266.7v7M186.1 271.2h1.2v.2M186.7 271.2l.6 1.3h-1.2zM191.8 273.3v.8h2.5v-.8v.8h2.5v-.8v.8h2.6v-.8v.8h2.5v-.8v.8h2.6v-.8v.8h2.5v-.8v.8h2.5v-.8M191.8 268v1.3M194.3 268v1.3M196.8 268v1.3M199.4 268v1.3M201.9 268v1.3M204.5 268v1.3M207 268v1.3M209.5 268v1.3"/>
<path d="M209.5 274.4v2.5M209.5 278.2v2.5M263.5 264.2h3.8M265.4 261.7v2.5M300 278.5h108M300 274.5h108M300 268.5h108M309.1 279.3h.9l-.5 .6 .4 .1v.7l-.2 .1h-.4l-.2-.1M310.6 269.1l-1.3 2M316.2 263.7h.6M316.4 263.2v1.3l.4 .2M317.3 263.2v.2"/>
<path d="M317.3 263.7v1M318.6 263.8l-.4-.1-.3 .3v.4l.2 .2h.5M320 278.5v3M328.9 272.5h.6l.1 .9M329.6 272.8h-.5a.29 .29 0 0 0-.3 .3 .29 .29 0 0 0 .3 .3l.5-.1M330.9 272.5l-.4-.1-.3 .3v.4l.1 .2h.6M330.9 271.9v1.5M331.3 273.6h1.1M333.3 272.5l-.4-.1-.2 .2 .1 .2 .5 .2v.3h-.6M334.6 272.5l-.4-.1-.3 .3v.4l.2 .2h.5M335.3 272.6l.2-.2 .4 .1v.9M335.3 271.9v1.5"/>
<path d="M340 279.3h-.7l-.1 .7 .2-.1 .5 .1 .2 .2-.1 .5-.2 .1-.6-.1M342.7 279.4l.2-.1a.8 .8 0 0 1 .5 .8 .8 .8 0 0 1-.5 .7 1 1 0 0 1-.2-1.4zM343.8 279.3h1.1l-.7 1.5M384 278.5v6.5M408 260h2M60 285v2M85.1 282h3.8M110 285v2M160 285v2M161.9 280.7h3.8M179.7 280.7h3.8M207.6 280.7h3.9"/>
<path d="M210 285v2M260 285v2M300 281.5h108M310 285v2M332.9 282.7l-.5-.1-.3 .3v.4l.2 .2h.6M332.9 282.1v1.5M333.4 282.6h.5M333.9 282.1l-.3 .2v1.3M334.9 282.7l-.3-.1-.2 .2v.2l.5 .2v.3h-.5M336.3 282.6v1.2l-.3 .3-.4-.1M336.3 282.7l-.4-.1-.3 .3v.4l.1 .2h.6M337 283h1.1"/>
<path d="M338.8 282.5l.4-.4v1.5M338.8 283.6h.8M340.7 280.2h1.2M360 285v2M392.9 282l-1.3 2M393.2 282.1h1l-.6 1.5"/>
<circle cx="137.7" cy="39.4" r=".51"/>
<circle cx="141.7" cy="36.9" r=".51"/>
<circle cx="141.7" cy="41.9" r=".51"/>
<circle cx="128.9" cy="78.8" r=".63"/>
<circle cx="277.5" cy="63.5" r=".63"/>
<circle cx="153" cy="90.2" r=".63"/>
<circle cx="234.2" cy="90.2" r=".51"/>
<circle cx="234.2" cy="95.3" r=".51"/>
<circle cx="238.3" cy="92.7" r=".51"/>
<circle cx="301" cy="91" r=".51"/>
<circle cx="301" cy="86.9" r=".51"/>
<circle cx="303.5" cy="86.9" r=".51"/>
<circle cx="303.5" cy="91" r=".51"/>
<circle cx="306.1" cy="91" r=".51"/>
<circle cx="306.1" cy="86.9" r=".51"/>
<circle cx="308.6" cy="91" r=".51"/>
<circle cx="308.6" cy="86.9" r=".51"/>
<circle cx="378.5" cy="81.3" r=".63"/>
<circle cx="51.7" cy="117.4" r=".63"/>
<circle cx="230.4" cy="114.3" r=".51"/>
<circle cx="230.4" cy="109.3" r=".51"/>
<circle cx="234.4" cy="111.8" r=".51"/>
<circle cx="350.5" cy="107.4" r=".63"/>
<circle cx="365.8" cy="107.4" r=".63"/>
<circle cx="381" cy="107.4" r=".63"/>
<circle cx="112.9" cy="132.6" r=".63"/>
<circle cx="178.4" cy="123.2" r=".63"/>
<circle cx="182.9" cy="134.7" r=".63"/>
<circle cx="275.5" cy="134" r=".51"/>
<circle cx="279.5" cy="134" r=".51"/>
<circle cx="160.5" cy="142.3" r=".51"/>
<circle cx="160.5" cy="147.4" r=".51"/>
<circle cx="164.6" cy="144.8" r=".51"/>
<circle cx="188.6" cy="151.2" r=".63"/>
<circle cx="231.8" cy="158.8" r=".63"/>
<circle cx="172.1" cy="165.1" r=".63"/>
<circle cx="191.1" cy="167.7" r=".63"/>
<circle cx="266.6" cy="163.9" r=".51"/>
<circle cx="270.6" cy="166.4" r=".51"/>
<circle cx="270.6" cy="161.3" r=".51"/>
<circle cx="159.3" cy="191.8" r=".51"/>
<circle cx="159.3" cy="186.7" r=".51"/>
<circle cx="163.3" cy="189.3" r=".51"/>
<circle cx="120.6" cy="228.6" r=".63"/>
<circle cx="257.2" cy="227.4" r=".63"/>
<circle cx="85.1" cy="255.3" r=".63"/>
<circle cx="100.3" cy="252.8" r=".63"/>
<circle cx="135.8" cy="255.3" r=".51"/>
<circle cx="139.8" cy="257.8" r=".51"/>
<circle cx="102.9" cy="268" r=".63"/>
<circle cx="128.8" cy="273.7" r=".51"/>
<circle cx="128.8" cy="268.6" r=".51"/>
<circle cx="132.8" cy="271.2" r=".51"/>
<circle cx="135.8" cy="260.4" r=".51"/>
<circle cx="161.3" cy="273.7" r=".13"/>
<circle cx="163.8" cy="273.7" r=".13"/>
<circle cx="179.1" cy="273.7" r=".13"/>
<circle cx="181.6" cy="273.7" r=".13"/>
<circle cx="184.1" cy="273.7" r=".13"/>
</g>
<g fill="none" stroke="#840000" stroke-width=".4">
<path d="M390.5 276l.2-.1 .5 .1v1.2M391.3 276.4l-.7 .1a.4 .4 0 0 0-.3 .3 .4 .4 0 0 0 .2 .4l.7-.1M392.3 276.1a.49 .49 0 0 1 .8 .1l-.1 1M392.3 275.9l-.2 1.3M394.9 276a.66 .66 0 0 0-.9 .3l-.1 .6 .1 .2 .2 .1 .6-.1M395 275.2l-.2 2M397.4 276l.2-.1 .6 .1-.1 1.2M398.2 276.4l-.7 .1a.4 .4 0 0 0-.3 .3 .4 .4 0 0 0 .3 .4l.6-.1M399.2 276.1a.49 .49 0 0 1 .9 .1l-.2 1M399.2 275.9l-.1 1.3M401 276l.2-.1 .6 .1-.1 1.2M401.8 276.4l-.6 .1a.4 .4 0 0 0-.4 .3 .4 .4 0 0 0 .3 .4l.6-.1"/>
<path d="M402.9 275.2l-.2 1.8 .3 .2M403.9 276.1a.52 .52 0 0 1 .5-.2 .52 .52 0 0 1 .4 .4l-.1 .6a.55 .55 0 0 1-.5 .4 .55 .55 0 0 1-.5-.4zM406.6 276a.66 .66 0 0 0-1 .3l-.1 .6 .2 .2 .1 .1 .6-.1M406.6 275.9l-.2 1.6a.6 .6 0 0 1-.9 .3"/>
</g>
<path d="M333.2 267.2l.7-.1-.1-.3-.4-.1-.2 .2 .1 .7h.5M335.2 266.8l-.4-.1-.3 .3v.4l.1 .2h.6M335.8 266.2v1.5M336 267.1l.4 .6M336.4 266.7l-.6 .6M337 266.2v.2M337 266.7v1" fill="none" stroke="#840000" stroke-width=".3"/>
<g fill="#fff" stroke="#fff" stroke-width=".18">
<path d="M57.8 20.4h30.5v15.2h-30.5z"/>
<path d="M354.6 41.2h27.2v12.7h-27.2z"/>
<path d="M261 17.2h22.8v15.2h-22.8z"/>
<path d="M214.6 16.5h30.5v15.3h-30.5z"/>
<path d="M170.8 16.5h30.5v15.3h-30.5z"/>
<path d="M18.4 20.4h30.5v15.2h-30.5z"/>
</g>
<path d="M170.8 16.5h30.5v15.3h-30.5zM214.6 16.5h30.5v15.3h-30.5zM261 17.2h22.8v15.2h-22.8zM18.4 20.4h30.5v15.2h-30.5zM57.8 20.4h30.5v15.2h-30.5zM354.6 41.2h27.2v12.7h-27.2z" fill="none" stroke="#840084" stroke-width=".18"/>
<g fill="none" stroke="#008484" stroke-width=".18">
<path d="M68.1 18.4h-.3l-.1 .1v.2l.4 .1v.3h-.4M181.1 14.6l.3-.1 .3 .3-.2 .5h-.4M225.5 14.6l-.3-.1-.1 .2v.2l.4 .1v.3h-.4M269.7 15.2l-.4 .2M364.4 39.2h.5M364.6 38.8v1l.3 .2M129.8 49.4v1.2M130.2 49.6l-.1 .5 .1 .2h.4l.2-.5 .3-.2 .3 .3-.1 .5M59.1 146.7h.9l-.6 1.3M72.1 146.8l.5-.1 .3 .4-.8 .9h.8M384.4 141.9l-.4 .1a.86 .86 0 0 0 0 1.2l.4-.1 .1-.4-.2-.3h-.3l-.2 .3M276.1 173.5l-.5-.1-.3 .3 .2 .3 .5 .2v.4l-.2 .1-.5-.1"/>
<path d="M285.3 173.8l.3-.4v1.3M285.3 174.7h.7M276.1 187.5l-.5-.1-.3 .2 .2 .4 .5 .2v.4l-.2 .1-.5-.1M285.3 187.8l.3-.4v1.3M285.3 188.7h.7M164.6 206.4h.8l-.5 1.3M177.6 206.5l.4-.1 .3 .3-.8 1h.8M180 218.5h-.5M280.1 202.6h.9l-.6 1.2M293.1 202.7l.5-.1 .3 .3-.8 .9h.8M295.5 214.6l-.5 .1M295.5 217.2l-.5 .1"/>
<path d="M180 221l-.5 .1M247.6 238.9l.7-.1-.1-.2-.4-.1-.2 .2 .1 .6h.5M255.9 241.5l.6-.2-.1-.2-.3-.1-.2 .2 .1 .6h.4M147.7 275.5h.4M148.3 274.9h-.6v1.3h.6M161.7 274.9l-.3 .1a.86 .86 0 0 0 0 1.2l.4-.1 .1-.4-.3-.3h-.2l-.3 .3M165.5 275.5h.4M166.1 274.9h-.6v1.3h.6M179.5 274.9l-.4 .1a.86 .86 0 0 0 0 1.2l.5-.1v-.4l-.2-.3h-.3l-.2 .3M250.8 278.1l.6-.1-.1-.2-.4-.1-.1 .2v.6h.5M250.8 271.8l.6-.2-.1-.2-.4-.1-.1 .2v.6h.5"/>
</g>
<g fill="none" stroke="#848400" stroke-width=".18">
<path d="M18.8 37.1h.4M19.4 36.5h-.6v1.3M19.9 36.5v.1M19.9 36.9v.9M20.5 36.5v1.1l.2 .2M21.1 37.4l.6-.2-.1-.2-.3-.1-.2 .2 .1 .6h.4M50.8 37l-.3-.1-.3 .3 .2 .5h.4M50.8 36.5v1.3M51.2 37.9h.9M52.8 37l-.3-.1-.1 .2v.2l.4 .1v.3h-.4M54 37l-.4-.1-.2 .3 .1 .5h.5M54.5 37.1l.2-.2 .3 .1 .1 .8"/>
<path d="M54.5 36.5v1.3M58.2 37.1h.4M58.8 36.5h-.6v1.3M59.3 36.5v.1M59.3 36.9v.9M59.9 36.5v1.1l.1 .2M87.1 37.9h1M88.8 37l-.3-.1-.2 .2 .1 .2 .4 .1v.3h-.5M90 37l-.4-.1-.2 .3 .1 .5h.5M90.5 37.1l.2-.2 .3 .1 .1 .8M90.5 36.5v1.3M171.2 33.3h.4"/>
<path d="M171.8 32.7h-.6v1.3M172.3 32.7v.1M172.3 33.1v.9M172.9 32.7v1.1l.2 .2M173.5 33.5l.6-.1-.1-.2-.3-.1-.2 .2 .1 .6h.4M207.1 33.2h.4l.1 .8M207.6 33.4l-.4 .1-.2 .2 .2 .3 .4-.1M208.8 33.2l-.4-.1-.3 .3 .2 .5h.5M208.8 32.7v1.3M209.1 34.1h.9M210.7 33.2l-.3-.1-.1 .2v.2l.4 .1v.3h-.4M211.9 33.2l-.4-.1-.2 .3 .1 .5h.5"/>
<path d="M212.4 33.2l.2-.1 .3 .1 .1 .8M212.4 32.7v1.3M215 33.4h.4M215.6 32.7h-.6v1.3M216.1 32.7v.2M216.1 33.2v.8M216.7 32.7v1.1l.2 .2M217.3 33.6l.6-.1v-.3h-.4l-.2 .2 .1 .6h.5M252.3 33.2h.4l.1 .8M252.8 33.5h-.4l-.2 .2 .2 .3h.4M254 33.2h-.4l-.2 .2 .1 .6h.5M254 32.7v1.3"/>
<path d="M254.3 34.1h.9M256 33.2h-.3l-.2 .2v.1l.5 .2v.3h-.5M257.1 33.2h-.4l-.2 .2 .1 .6h.5M257.6 33.3l.2-.1h.3l.1 .8M257.6 32.7v1.3M261.4 33.9h.4M262 33.3h-.6v1.3M262.5 33.3v.2M262.5 33.8v.8M263.1 33.3v1.1l.1 .2M263.7 34.2l.6-.1-.1-.3h-.4l-.1 .1v.6h.5M291.5 33.8h-.3l-.3 .2 .2 .5h.4"/>
<path d="M291.5 33.3v1.3M291.8 34.7h1M293.5 33.8h-.3l-.1 .1v.2l.4 .1v.3h-.4M294.7 33.8h-.4l-.2 .2 .1 .5h.5M295.2 33.9l.2-.1h.3l.1 .8M295.2 33.3v1.3M355 55.4h.4M355.6 54.8h-.6v1.3M356.1 54.8v.1M356.1 55.2v.9M356.7 54.8v1.1l.1 .2M357.3 55.6l.6-.1-.1-.2-.4-.1-.1 .2v.6h.5"/>
<path d="M389.8 55.3h.5v.8M390.3 55.5l-.4 .1-.2 .2 .2 .3 .4-.1M391.5 55.3l-.4-.1-.2 .3 .1 .5h.5M391.5 54.8v1.3M391.8 56.2h1M393.5 55.3l-.3-.1-.2 .2 .1 .2 .4 .1v.3h-.5M394.6 55.3l-.3-.1-.3 .3 .2 .5h.4M395.2 55.3l.2-.1 .3 .1v.8M395.2 54.8v1.3"/>
</g>
<g fill="#ffffc2" stroke="#ffffc2" stroke-width=".18">
<path d="M53.3 148.6h25.4v45.7h-25.4z"/>
<path d="M205.3 187.9l5 1.4a5.2 5.2 0 0 1-4.4 3.8z"/>
<path d="M202.7 193.1h3.2z"/>
<path d="M202.7 185.5h3.2z"/>
<path d="M202.7 185.5h3.2v7.6h-3.2a6.7 6.7 0 0 0 0-7.6z"/>
<path d="M205.9 185.5a5.1 5.1 0 0 1 4.4 3.8l-5 1.3z"/>
<path d="M223.5 155l7.6 3.8-7.6 3.8z"/>
<path d="M275.6 175.3h10.1v7.6h-10.1z"/>
<path d="M275.6 189.3h10.1v7.6h-10.1z"/>
<path d="M141.6 229.9h3.8z"/>
<path d="M141.6 235h3.8z"/>
<path d="M274.3 204.5h25.4v45.7h-25.4z"/>
<path d="M158.7 208.3h25.4v45.7h-25.4z"/>
<path d="M224.8 219.7h5.1v38.1h-5.1z"/>
<path d="M34.3 83.1h10.1v15.2h-10.1z"/>
<path d="M269.2 59.7l7.7 3.8-7.7 3.8z"/>
<path d="M256.6 62.2l5 1.3a5.2 5.2 0 0 1-4.4 3.8z"/>
<path d="M254 67.3h3.2z"/>
<path d="M254 59.7h3.2z"/>
<path d="M254 59.7h3.2v7.6h-3.2a6.7 6.7 0 0 0 0-7.6z"/>
<path d="M257.2 59.7a5.1 5.1 0 0 1 4.4 3.8l-5 1.3z"/>
<path d="M18.4 97.8h10.2v15.3h-10.2z"/>
<path d="M62.7 83.1h10.2v15.2h-10.2z"/>
<path d="M47.2 83.1h10.2v15.2h-10.2z"/>
<path d="M43.4 113.6l7.7 3.8-7.7 3.8z"/>
<path d="M76.7 83.1h10.2v15.2h-10.2z"/>
<path d="M80 218.5h10.2v15.2h-10.2z"/>
<path d="M257.8 227.4l7.6-3.8v7.6z"/>
<path d="M190.5 268.6h20.3v6.4h-20.3z"/>
<path d="M67.3 218.5h10.2v15.2h-10.2z"/>
<path d="M47 218.5h10.1v15.2h-10.1z"/>
<path d="M156.2 269.3h15.2v5.1h-15.2z"/>
<path d="M101 252.8l7.6-3.8v7.6z"/>
<path d="M87 253.1a5.2 5.2 0 0 1 3.1-1.6l.6 5.2-5-1.4 .5-1.1z"/>
<path d="M90.2 251.5h3.1z"/>
<path d="M90.2 259.1h3.1z"/>
<path d="M90.2 251.5h3.1a6.7 6.7 0 0 0 0 7.6h-3.1z"/>
<path d="M85.7 255.3l5-1.3-.6 5.1a5.1 5.1 0 0 1-4.4-3.8z"/>
<path d="M163.8 161.3l7.6 3.8-7.6 3.8z"/>
<path d="M175.3 185.4l5 1.3a5.2 5.2 0 0 1-4.4 3.8z"/>
<path d="M172.7 190.5h3.2z"/>
<path d="M172.7 182.9h3.2z"/>
<path d="M172.7 182.9h3.2v7.6h-3.2a6.7 6.7 0 0 0 0-7.6z"/>
<path d="M175.9 182.9a5.1 5.1 0 0 1 4.4 3.8l-4.9 1.3z"/>
<path d="M365.1 142.3h10.2v10.1h-10.2z"/>
<path d="M377.2 99.1h7.6l-3.8 7.6z"/>
<path d="M346.7 99.1h7.6l-3.8 7.6z"/>
<path d="M370.2 77.5l7.6 3.8-7.6 3.8z"/>
<path d="M361.9 99.1h7.7l-3.8 7.6z"/>
<path d="M185.5 166.3l5 1.4a5.2 5.2 0 0 1-4.4 3.8z"/>
<path d="M182.9 171.5h3.2z"/>
<path d="M182.9 163.9h3.2z"/>
<path d="M182.9 163.9h3.2v7.6h-3.2a6.7 6.7 0 0 0 0-7.6z"/>
<path d="M186.1 163.9a5.1 5.1 0 0 1 4.4 3.8l-5 1.3z"/>
<path d="M298.4 85.1h12.7v7.6h-12.7z"/>
<path d="M174 269.3h15.2v5.1h-15.2z"/>
<path d="M252.8 107.9l5 1.4a5.2 5.2 0 0 1-4.4 3.8z"/>
<path d="M250.2 113.1h3.2z"/>
<path d="M250.2 105.4h3.2z"/>
<path d="M250.2 105.4h3.2v7.7h-3.2a6.7 6.7 0 0 0 0-7.7z"/>
<path d="M253.4 105.4a5.1 5.1 0 0 1 4.4 3.9l-5 1.3z"/>
<path d="M196.9 115.6a3.8 3.8 0 0 1 3.8 3.8 3.8 3.8 0 0 1-3.8 3.8z"/>
<path d="M193 115.6h3.8v7.6h-3.8z"/>
<path d="M120.6 75l7.7 3.8-7.7 3.8z"/>
<path d="M20.3 51.5h10.2v15.2h-10.2z"/>
<path d="M34.3 51.5h10.1v15.2h-10.1z"/>
<path d="M252.8 121.9l5 1.3a5.2 5.2 0 0 1-4.4 3.8z"/>
<path d="M250.2 127h3.2z"/>
<path d="M250.2 119.4h3.2z"/>
<path d="M250.2 119.4h3.2v7.6h-3.2a6.7 6.7 0 0 0 0-7.6z"/>
<path d="M253.4 119.4a5.1 5.1 0 0 1 4.4 3.8l-5 1.3z"/>
<path d="M172.8 121.9l5 1.3a5.2 5.2 0 0 1-4.4 3.8z"/>
<path d="M170.2 127h3.2z"/>
<path d="M170.2 119.4h3.2z"/>
<path d="M170.2 119.4h3.2v7.6h-3.2a6.7 6.7 0 0 0 0-7.6z"/>
<path d="M173.4 119.4a5.1 5.1 0 0 1 4.4 3.8l-5 1.3z"/>
<path d="M177.2 133.3l5 1.4a5.2 5.2 0 0 1-4.4 3.8z"/>
<path d="M174.6 138.5h3.2z"/>
<path d="M174.6 130.8h3.2z"/>
<path d="M174.6 130.8h3.2v7.7h-3.2a6.7 6.7 0 0 0 0-7.7z"/>
<path d="M177.8 130.8a5.1 5.1 0 0 1 4.4 3.9l-4.9 1.3z"/>
<path d="M158.8 71.1l5 1.3a5.2 5.2 0 0 1-4.4 3.8z"/>
<path d="M156.2 76.2h3.2z"/>
<path d="M156.2 68.6h3.2z"/>
<path d="M156.2 68.6h3.2v7.6h-3.2a6.7 6.7 0 0 0 0-7.6z"/>
<path d="M159.4 68.6a5.1 5.1 0 0 1 4.4 3.8l-4.9 1.3z"/>
<path d="M241.4 68.5l5 1.4a5.2 5.2 0 0 1-4.4 3.8z"/>
<path d="M238.8 73.7h3.1z"/>
<path d="M238.8 66.1h3.1z"/>
<path d="M238.8 66.1h3.1v7.6h-3.1a6.7 6.7 0 0 0 0-7.6z"/>
<path d="M242 66.1a5.1 5.1 0 0 1 4.4 3.8l-5 1.3z"/>
<path d="M251.5 88.9a3.8 3.8 0 0 1 3.8 3.8 3.8 3.8 0 0 1-3.8 3.9z"/>
<path d="M247.6 88.9h3.9v7.7h-3.9z"/>
<path d="M139.7 66.1a3.8 3.8 0 0 1 3.8 3.8 3.8 3.8 0 0 1-3.8 3.8z"/>
<path d="M135.9 66.1h3.8v7.6h-3.8z"/>
<path d="M252.8 135.8l5 1.4a5.2 5.2 0 0 1-4.4 3.8z"/>
<path d="M250.2 141h3.2z"/>
<path d="M250.2 133.4h3.2z"/>
<path d="M250.2 133.4h3.2v7.6h-3.2a6.7 6.7 0 0 0 0-7.6z"/>
<path d="M253.4 133.4a5.1 5.1 0 0 1 4.4 3.8l-5 1.3z"/>
<path d="M265.5 93.9l5 1.4a5.2 5.2 0 0 1-4.4 3.8z"/>
<path d="M262.9 99.1h3.2z"/>
<path d="M262.9 91.5h3.2z"/>
<path d="M262.9 91.5h3.2v7.6h-3.2a6.7 6.7 0 0 0 0-7.6z"/>
<path d="M266.1 91.5a5.1 5.1 0 0 1 4.4 3.8l-5 1.3z"/>
<path d="M177.9 107.9l5 1.4a5.2 5.2 0 0 1-4.4 3.8z"/>
<path d="M175.3 113.1h3.1z"/>
<path d="M175.3 105.4h3.1z"/>
<path d="M175.3 105.4h3.1v7.7h-3.1a6.7 6.7 0 0 0 0-7.7z"/>
<path d="M178.5 105.4a5.1 5.1 0 0 1 4.4 3.9l-5 1.3z"/>
<path d="M62.2 51.5h10.2v15.2h-10.2z"/>
<path d="M76.2 51.5h10.2v15.2h-10.2z"/>
<path d="M176.6 59.6l5 1.4a5.2 5.2 0 0 1-4.4 3.8z"/>
<path d="M174 64.8h3.2z"/>
<path d="M174 57.2h3.2z"/>
<path d="M174 57.2h3.2v7.6h-3.2a6.7 6.7 0 0 0 0-7.6z"/>
<path d="M177.2 57.2a5.1 5.1 0 0 1 4.4 3.8l-5 1.3z"/>
<path d="M198.2 147.3l5 1.3a5.2 5.2 0 0 1-4.4 3.8z"/>
<path d="M195.6 152.4h3.2z"/>
<path d="M195.6 144.8h3.2z"/>
<path d="M195.6 144.8h3.2v7.6h-3.2a6.7 6.7 0 0 0 0-7.6z"/>
<path d="M198.8 144.8a5.1 5.1 0 0 1 4.4 3.8l-5 1.3z"/>
<path d="M161.3 49.6a3.8 3.8 0 0 1 3.8 3.8 3.8 3.8 0 0 1-3.8 3.8z"/>
<path d="M157.5 49.6h3.8v7.6h-3.8z"/>
<path d="M144.8 86.4l7.6 3.8-7.6 3.8z"/>
<path d="M160.1 101.6l5 1.3a5.2 5.2 0 0 1-4.4 3.8z"/>
<path d="M157.5 106.7h3.2z"/>
<path d="M157.5 99.1h3.2z"/>
<path d="M157.5 99.1h3.2v7.6h-3.2a6.7 6.7 0 0 0 0-7.6z"/>
<path d="M160.7 99.1a5.1 5.1 0 0 1 4.4 3.8l-5 1.3z"/>
<path d="M169 86.3l5 1.4a5.2 5.2 0 0 1-4.4 3.8z"/>
<path d="M166.4 91.5h3.1z"/>
<path d="M166.4 83.9h3.1z"/>
<path d="M166.4 83.9h3.1v7.6h-3.1a6.7 6.7 0 0 0 0-7.6z"/>
<path d="M169.6 83.9a5.1 5.1 0 0 1 4.4 3.8l-5 1.3z"/>
<path d="M213.4 149.8l5 1.4a5.2 5.2 0 0 1-4.4 3.8z"/>
<path d="M210.8 155h3.2z"/>
<path d="M210.8 147.4h3.2z"/>
<path d="M210.8 147.4h3.2v7.6h-3.2a6.7 6.7 0 0 0 0-7.6z"/>
<path d="M214 147.4a5.1 5.1 0 0 1 4.4 3.8l-4.9 1.3z"/>
<path d="M224.2 125.8a3.8 3.8 0 0 1 3.8 3.8 3.8 3.8 0 0 1-3.8 3.8z"/>
<path d="M220.3 125.8h3.9v7.6h-3.9z"/>
<path d="M48.3 51.5h10.1v15.2h-10.1z"/>
<path d="M284.5 102.9a3.8 3.8 0 0 1 3.8 3.8 3.8 3.8 0 0 1-3.8 3.8z"/>
<path d="M280.7 102.9h3.8v7.6h-3.8z"/>
<path d="M125.7 48.3h10.2v10.2h-10.2z"/>
<path d="M180.3 147.4l7.7 3.8-7.7 3.8z"/>
<path d="M196.9 128.3a3.8 3.8 0 0 1 3.8 3.8 3.8 3.8 0 0 1-3.8 3.8z"/>
<path d="M193 128.3h3.8v7.6h-3.8z"/>
<circle cx="367" cy="164.5" r="4.6"/>
</g>
<path d="M207 58.5h15.2v17.7h-15.2zM288.3 53.4h15.2v12.7h-15.2zM321.3 53.4h20.3v33h-20.3zM53.3 148.6h25.4v45.7h-25.4zM158.7 208.3h25.4v45.7h-25.4zM274.3 204.5h25.4v45.7h-25.4z" fill="none" stroke="#840000" stroke-width=".41"/>
<g fill="none" stroke="#840000" stroke-width=".25">
<path d="M158.7 35.9h5.1v2h-5.1zM20.3 51.5h10.2v15.2h-10.2zM34.3 51.5h10.1v15.2h-10.1zM48.3 51.5h10.1v15.2h-10.1zM62.2 51.5h10.2v15.2h-10.2zM76.2 51.5h10.2v15.2h-10.2zM125.7 48.3h10.2v10.2h-10.2zM157.5 49.6h3.8a3.8 3.8 0 0 1 3.8 3.8 3.8 3.8 0 0 1-3.8 3.8h-3.8zM158.7 40.9h5.1v2.1h-5.1zM174 57.2h3.2a5.1 5.1 0 0 1 4.4 3.8 5.2 5.2 0 0 1-4.4 3.8h-3.2M174 57.2a6.6 6.6 0 0 1 0 7.6M253.4 59.7a6.6 6.6 0 0 1 0 7.6"/>
<path d="M257.2 59.7h-3.2a6.6 6.6 0 0 1 0 7.6h3.2M257.2 59.7a5.1 5.1 0 0 1 4.4 3.8 5.2 5.2 0 0 1-4.4 3.8M269.2 59.7l7.7 3.8-7.7 3.8zM95.5 73.7h2v5.1h-2zM120.6 75l7.7 3.8-7.7 3.8zM135.9 66.1h3.8a3.8 3.8 0 0 1 3.8 3.8 3.8 3.8 0 0 1-3.8 3.8h-3.8zM159.4 68.6h-3.2a6.6 6.6 0 0 1 0 7.6h3.2M159.4 68.6a5.1 5.1 0 0 1 4.4 3.8 5.2 5.2 0 0 1-4.4 3.8M241.9 66.1h-3.1a6.6 6.6 0 0 1 0 7.6h3.1M242 66.1a5.1 5.1 0 0 1 4.4 3.8 5.2 5.2 0 0 1-4.4 3.8M274.3 71.4h5.1v2h-5.1zM280.7 74h5v2h-5z"/>
<path d="M287 76.5h5.1v2h-5.1zM293.4 79h5v2.1h-5zM370.2 77.5l7.6 3.8-7.6 3.8zM18.4 97.8h10.2v15.3h-10.2zM34.3 83.1h10.1v15.2h-10.1zM47.2 83.1h10.2v15.2h-10.2zM62.7 83.1h10.2v15.2h-10.2zM76.7 83.1h10.2v15.2h-10.2zM104.4 81.3h2v5.1h-2zM120.9 94h2v5.1h-2zM144.8 86.4l7.6 3.8-7.6 3.8zM160.7 99.1h-3.2a6.6 6.6 0 0 1 0 7.6h3.2"/>
<path d="M160.7 99.1a5.1 5.1 0 0 1 4.4 3.8 5.2 5.2 0 0 1-4.4 3.8M169.5 83.9h-3.1a6.6 6.6 0 0 1 0 7.6h3.1M169.6 83.9a5.1 5.1 0 0 1 4.4 3.8 5.2 5.2 0 0 1-4.4 3.8M247.6 88.9h3.9a3.8 3.8 0 0 1 3.8 3.8 3.8 3.8 0 0 1-3.8 3.9h-3.9zM266.1 91.5h-3.2a6.6 6.6 0 0 1 0 7.6h3.2M266.1 91.5a5.1 5.1 0 0 1 4.4 3.8 5.2 5.2 0 0 1-4.4 3.8M298.4 85.1h12.7v7.6h-12.7zM346.7 99.1h7.6l-3.8 7.6zM361.9 99.1h7.7l-3.8 7.6zM377.2 99.1h7.6l-3.8 7.6zM43.4 113.6l7.7 3.8-7.7 3.8zM170.2 119.4h3.2a5.1 5.1 0 0 1 4.4 3.8 5.2 5.2 0 0 1-4.4 3.8h-3.2a6.6 6.6 0 0 0 0-7.6z"/>
<path d="M175.3 105.4h3.2a5.1 5.1 0 0 1 4.4 3.9 5.2 5.2 0 0 1-4.4 3.8h-3.2a6.6 6.6 0 0 0 0-7.7zM193 115.6h3.9a3.8 3.8 0 0 1 3.8 3.8 3.8 3.8 0 0 1-3.8 3.8h-3.9zM219.7 113.3h5.1v2.1h-5.1zM250.2 105.4h3.2a5.1 5.1 0 0 1 4.4 3.9 5.2 5.2 0 0 1-4.4 3.8h-3.2a6.6 6.6 0 0 0 0-7.7zM250.2 119.4h3.2a5.1 5.1 0 0 1 4.4 3.8 5.2 5.2 0 0 1-4.4 3.8h-3.2a6.6 6.6 0 0 0 0-7.6zM280.7 102.9h3.8a3.8 3.8 0 0 1 3.8 3.8 3.8 3.8 0 0 1-3.8 3.8h-3.8zM84.6 130.1h3.8a2.54 2.54 0 0 1 2.5 2.5 2.54 2.54 0 0 1-2.5 2.6h-3.8zM95.5 131.6h5.1v2h-5.1zM105.9 130.1l6.4 2.5-6.4 2.6zM174.6 130.8h3.2a5.1 5.1 0 0 1 4.4 3.9 5.2 5.2 0 0 1-4.4 3.8h-3.2a6.6 6.6 0 0 0 0-7.7zM193 128.3h3.9a3.8 3.8 0 0 1 3.8 3.8 3.8 3.8 0 0 1-3.8 3.8h-3.9zM220.3 125.8h3.9a3.8 3.8 0 0 1 3.8 3.8 3.8 3.8 0 0 1-3.8 3.8h-3.9z"/>
<path d="M250.2 133.4h3.2a5.1 5.1 0 0 1 4.4 3.8 5.2 5.2 0 0 1-4.4 3.8h-3.2a6.6 6.6 0 0 0 0-7.6zM180.3 147.4l7.7 3.8-7.7 3.8zM195.6 152.4a6.6 6.6 0 0 0 0-7.6h3.2a5.1 5.1 0 0 1 4.4 3.8 5.2 5.2 0 0 1-4.4 3.8h-3.2M210.8 147.4h3.2a5.1 5.1 0 0 1 4.4 3.8 5.2 5.2 0 0 1-4.4 3.8h-3.2a6.6 6.6 0 0 0 0-7.6zM223.5 155l7.6 3.8-7.6 3.8zM278.1 141.3h5.1v2h-5.1zM287 141l2.6 1.3-2.6 1.2zM289.6 141v2.5M365.1 142.3h10.2v10.1h-10.2zM366.4 148.6l2.5 1.3-2.5 1.3zM366.4 143.5l2.5 1.3-2.5 1.3zM368.9 143.5v2.6"/>
<path d="M368.9 148.6v2.6M371.5 146.1l2.5 1.3-2.5 1.2zM374 146.1v2.5M379.1 143.8h5.1v2h-5.1zM380.4 146.3h5v2.1h-5zM382.9 148.9h5.1v2h-5.1zM163.8 161.3l7.6 3.8-7.6 3.8zM186.1 163.9h-3.2a6.6 6.6 0 0 1 0 7.6h3.2M186.1 163.9a5.1 5.1 0 0 1 4.4 3.8 5.2 5.2 0 0 1-4.4 3.8M266.7 175.6h5.1v2h-5.1zM275.6 175.3h10.1v7.6h-10.1zM277.5 178.5h1.3l-.7 1.2z"/>
<path d="M277.5 179.7h1.3M365.1 175.9l2.6 1.3-2.6 1.3zM365.8 165.8l2.5 1.2-2.5 1.3zM365.8 160.7l2.5 1.3-2.5 1.2zM367.7 175.9v2.6M368.3 160.7v2.5M368.3 165.8v2.5M371.5 176.2h5.1v2h-5.1zM379.7 160.9h5.1v2.1h-5.1zM379.7 166h5.1v2.1h-5.1zM109.2 187h5.1v2h-5.1zM162.6 197.1h5v2.1h-5z"/>
<path d="M175.9 182.9h-3.2a6.6 6.6 0 0 1 0 7.6h3.2M175.9 182.9a5.1 5.1 0 0 1 4.4 3.8 5.2 5.2 0 0 1-4.4 3.8M202.7 193.1h3.2M205.9 185.5h-3.2a6.6 6.6 0 0 1 0 7.6M205.9 185.5a5.1 5.1 0 0 1 4.4 3.8 5.2 5.2 0 0 1-4.4 3.8M266.7 189.5h5.1v2.1h-5.1zM275.6 189.3h10.1v7.6h-10.1zM277.5 192.4h1.3l-.7 1.3zM277.5 193.7h1.3M365.1 183.6l2.6 1.2-2.6 1.3zM365.1 191.2l2.6 1.2-2.6 1.3zM365.1 198.2l2.6 1.2-2.6 1.3z"/>
<path d="M367.7 183.6v2.5M367.7 191.2v2.5M367.7 198.2v2.5M371.5 183.8h5.1v2h-5.1zM371.5 198.4h5.1v2h-5.1zM371.5 191.4h5.1v2.1h-5.1zM47 218.5h10.1v15.2h-10.1zM67.3 218.5h10.2v15.2h-10.2zM80 218.5h10.2v15.2h-10.2zM224.8 219.7h5.1v38.1h-5.1zM262.9 208.6h5.1v2h-5.1zM262.9 216.2h5.1v2h-5.1z"/>
<path d="M262.9 218.7h5.1v2.1h-5.1zM262.9 213.7h5.1v2h-5.1zM262.9 211.1h5.1v2h-5.1zM365.1 205.1l2.6 1.3-2.6 1.3zM367.7 205.1v2.6M371.5 205.4h5.1v2h-5.1zM121.3 228.6l6.3-2.5v5.1zM140 230.9l.7-.6 .9-.4h3.8a4.1 4.1 0 0 0 0 5.1h-3.8a3.6 3.6 0 0 1-2.5-2.6l.3-.7zM257.8 227.4l7.6-3.8v7.6zM346.7 223.2h5.1v2h-5.1zM346.7 230.8h5.1v2h-5.1zM355.6 231.8l2.5-1.3v2.6z"/>
<path d="M355.6 224.2l2.5-1.3v2.6zM355.6 222.9v2.6M355.6 230.5v2.6M373.4 223.2h5.1v2h-5.1zM373.4 230.8h5.1v2h-5.1zM382.3 224.2l2.5-1.3v2.6zM382.3 231.8l2.5-1.3v2.6zM382.3 222.9v2.6M382.3 230.5v2.6M87 253.1a5.2 5.2 0 0 1 3.1-1.6h3.2a6.6 6.6 0 0 0 0 7.6h-3.2a5.1 5.1 0 0 1-4.4-3.8l.5-1.1zM101 252.8l7.6-3.8v7.6zM241.9 240.6h5.1v1.5h-5.1z"/>
<path d="M250.2 243.1h5.1v1.5h-5.1zM264.4 254h2v5.1h-2zM86 273.1h2v5.1h-2zM95.9 265.5l6.3 2.5-6.3 2.5zM156.2 269.3h15.2v5.1h-15.2zM174 269.3h15.2v5.1h-15.2zM190.5 268.6h20.3v6.4h-20.3zM191 269.3h1.5v4h-1.5zM193.5 269.3h1.6v4h-1.6zM196.1 269.3h1.5v4h-1.5zM198.6 269.3h1.6v4h-1.6zM201.2 269.3h1.5v4h-1.5z"/>
<path d="M203.7 269.3h1.5v4h-1.5zM206.2 269.3h1.6v4h-1.6zM208.8 269.3h1.5v4h-1.5z"/>
<circle cx="105.4" cy="73.7" r="2.82"/>
<circle cx="106.7" cy="92.7" r="2.82"/>
<circle cx="367" cy="164.5" r="4.6"/>
<circle cx="262.9" cy="237.5" r="1.9"/>
</g>
<g fill="none" stroke="#840000" stroke-width="1.3">
<circle cx="236.2" cy="276.3" r="1.27"/>
<circle cx="236.2" cy="269.9" r="1.27"/>
</g>
<g fill="none" stroke="#840000" stroke-width=".51">
<path d="M305.3 26.2h4.1M305.3 24.7h4.1M314.2 26.2h4.1M314.2 24.7h4.1M323.1 26.2h4.1M323.1 24.7h4.1M333.2 26.2h4.1M333.2 24.7h4.1M343.4 26.2h4.1M343.4 24.7h4.1M354.8 26.2h4.1M354.8 24.7h4.1"/>
<path d="M366.3 26.2h4M366.3 24.7h4M103.5 74.3h3.8M107.3 90.8v3.9M100.1 141.8h4M100.1 140.2h4M283.2 177.2v3.8M283.2 191.2v3.8M261.7 237.5h2.3M262.9 236.4v2.3"/>
</g>
<g fill="#840000" stroke="#840000" stroke-width=".18">
<path d="M283.2 179.7l1.9 1.9z"/>
<path d="M283.7 180.8l.5-.6 .5 1.1z"/>
<path d="M283.2 193.7l1.9 1.9z"/>
<path d="M283.7 194.7l.5-.5 .5 1z"/>
<path d="M103.1 73.2l.5-.5 .5 1z"/>
<path d="M106.2 94l.5 .5-1 .5z"/>
<path d="M291.1 147.9h4.6v.5h-4.6z"/>
<circle cx="209.5" cy="274.1" r=".25"/>
<circle cx="207" cy="274.1" r=".25"/>
<circle cx="204.5" cy="274.1" r=".25"/>
<circle cx="201.9" cy="274.1" r=".25"/>
<circle cx="199.4" cy="274.1" r=".25"/>
<circle cx="196.8" cy="274.1" r=".25"/>
<circle cx="194.3" cy="274.1" r=".25"/>
</g>
<g fill="none" stroke="#0000c2" stroke-width=".18">
<path d="M141.6 13.5v1.2M142 13.5h.8M142.4 13.5v1.2M143.9 13.6a.6 .6 0 0 0-.8 .4 .6 .6 0 0 0 .6 .7l.2-.1M144.5 13.5v1.2M144.5 14.1h.7M145.2 13.5v1.2M145.8 13.9v.2M145.9 14.7l-.2 .2M160.8 16.1h.4M161.4 15.5h-.6v1.3h.6M163.6 15.5v1.3l-.7-1.3v1.3"/>
<path d="M164.2 15.5v1.3M165.6 15.5v1.3l-.8-1.3v1.3M166.2 15.5v1.3M167.4 15.6a.59 .59 0 0 0-.7 .5 .59 .59 0 0 0 .7 .6l.1-.5h-.2M168 15.5v1.3M164.2 119.7l-.4 .2M164.6 120.1l.6-.1-.1-.3h-.4l-.1 .2v.6h.5M186.7 194.3l.6-.1-.1-.3h-.3l-.2 .1 .1 .6h.4M187.8 193.9v.8M188.2 193.9l-.4 .2M188.6 194.3l.6-.1-.1-.3h-.4l-.1 .1v.6h.5M41 276.7l.3-.1 .2 .3v.3l-.2 .3-.3-.1-.2-.2z"/>
<path d="M42.8 276.6h.5M43 276.2v1.1l.3 .2M43.8 276.7l.3-.1 .2 .3v.3l-.2 .3-.3-.1-.1-.2zM45.6 274.8l.1-.2h.3l.1 .8M45.9 276.9l.6-.1 .1-.2-.1-.3-.6-.1v1.3M47.7 274.8h.6l.1-.2-.1-.3-.6-.1v1.2M47.9 276.3a.6 .6 0 0 0-.9 .5 .6 .6 0 0 0 .6 .7l.3-.1M49.7 274.3a.6 .6 0 0 0-.9 .4 .6 .6 0 0 0 .6 .7l.3-.1M72.3 278.8l.2-.1h.3v.8M74.4 278.3v.1M74.4 278.7v.8M75.4 278.7h-.3l-.2 .2 .1 .1 .4 .2v.3h-.5"/>
<path d="M77 278.7h.5v.8M77.5 279h-.4l-.2 .2 .2 .3h.4M78.7 278.7h-.4l-.2 .2 .1 .6h.5M79.1 278.7h.4M79.2 278.3v1l.3 .2M80 278.3v.1M80 278.7v.8M80.4 278.7l.4 .8 .3-.8M81.5 279.1l.6-.1-.1-.3h-.3l-.2 .2v.6h.5M144.9 279.5h-.4l-.2 .2 .1 .5h.5M144.9 279v1.3M145.9 279.5h-.3l-.2 .1 .1 .2 .4 .1v.3h-.5"/>
<path d="M146.5 279.6l.2-.1 .3 .1 .1 .5-.1 .1-.3 .1-.2-.1zM147.6 279v1.1l.2 .2M148.8 279.5h-.3l-.3 .2 .2 .5h.4M148.8 279v1.3M149.4 279.9l.6-.1-.1-.3h-.3l-.2 .1 .1 .6h.4M150.5 279.5v.8M150.9 279.5l-.4 .2M151.3 279v.1M151.3 279.5v.8M151.9 279.6l.2-.1h.3l.1 .8M151.9 279.5v.8M153.6 279.5v1l-.2 .2h-.3"/>
<path d="M153.6 279.5h-.3l-.3 .2 .1 .5h.5M57.7 280.8l.2-.1 .3 .1 .1 .8M57.7 280.7v.9M58.7 280.7h.5M58.9 280.3v1.1l.3 .2M59.6 280.7v.9M59.9 280.7l-.3 .3M60.4 280.8l.3-.1 .3 .3v.3l-.3 .3-.3-.1-.1-.2zM61.5 280.3v1.1l.2 .2M63.2 281l.6-.1 .1-.2-.1-.3-.6-.1v1.3M64.6 280.3v1.3M65.6 280.3v1.3"/>
<path d="M142.7 282.2h.6l.2-.2-.1-.3-.7-.1v1.2M144.1 281.7l.2-.1a.68 .68 0 0 1 .4 .6 .68 .68 0 0 1-.4 .6l-.4-.4zM145.2 282.7v.1M146.5 282.1l-.3 .3-.3-.1-.1-.2v-.3l.2-.2h.2l.3 .2a.84 .84 0 0 1-.4 1h-.2M147.6 281.6h-.6v.6l.2-.1h.4l.1 .2-.1 .4-.1 .1-.5-.1M148.2 282.1l.2-.1 .3 .1 .1 .7M148.2 282v.8M148.8 282.2l.2-.2 .3 .1v.7M149.9 282.1l.2-.1 .3 .1 .1 .7M149.9 282v.8M150.5 282.2l.2-.2 .3 .1v.7"/>
</g>
<g fill="none" stroke="#008400" stroke-width=".18">
<path d="M130.8 38.1v7.7M130.8 39.4h3.8M144.8 36.9h12.7M165.1 36.9h1.3M307.3 29.2v.7h61M316.2 29.2v.7M325.1 29.2v.7M335.3 29.2v.7M345.4 20.4v1.2M345.4 29.2v.7M356.9 20.4v1.2M356.9 29.2v.7"/>
<path d="M368.3 20.4v1.2h-61M368.3 29.2v2M25.4 46.4h55.9M118.1 53.4h5.1M123.2 50.8h-8.9v21.6h-3.8M138.4 50.8h15.3M143.5 55.9h10.2M144.8 41.9h12.7M165.1 41.9h1.3M168.9 53.4h1.3v5.1M187.3 52.1h-1.9v43.2h45.7M276.9 55.9h6.3"/>
<path d="M308.6 55.9h7.6M308.6 58.5h7.6M25.4 71.8h55.9M39.4 69.3v2.5M84.8 77.3v.7h-45.4M96.5 69.9v2.5h3.8M111.8 63.5h2.5M114.3 67.3h17.8M116.8 78.8v189.2h-10.8M121.9 72.4h10.2M130.8 61v1.9h-3.2M132.1 78.8h49.5v19h77.5"/>
<path d="M147.3 69.9h5.1M152.4 75h-17.8v30.4h19.1M170.2 63.5v8.9h-2.6M185.4 61h16.5M186.7 73.7h15.2M195.6 71.2h6.3M198.1 67.3h3.8M227.3 61h22.9M231.1 61v29.2M234.9 67.3h-6.3v11.5h-43.2M234.9 72.4v8.9h-53.3M234.9 78.1h2"/>
<path d="M250.2 66.1v6.3M270.5 71.8v8.2h21.6M270.5 75h8.9M270.5 77.5h15.2M270.5 72.4h2.5M301 72.4v8.9M303.5 75v6.3M306.1 77.5v3.8M308.6 61h7.6M308.6 63.5h7.6M313.7 78.8h2.5M316.2 68.6h-10.1v6.4h-19.1"/>
<path d="M316.2 71.2h-8.9v6.3h-13.9M316.2 66.1h-11.4v6.3h-24.1M316.2 73.7h-7.6v7.6M23.5 91.5v1.2M96.5 80h8.9M113 92.7h8.9M141 90.2h-3.8v10.2h12.7v113h3.8M156.2 90.2h6.4M162.6 85.1h-43.2v68.6h-35.6M241.3 92.7v2.6h2.5M262.9 86.4h-20.3v3.8h1.2M274.3 95.3v5.1h-30.5v6.3h2.6"/>
<path d="M276.9 83.9v20.3M278.1 83.9h-99v3.8h-1.3M299.7 80h8.9M301 96.6h7.6M313.7 81.3h2.5M315 83.9h1.2M346.7 81.3h19.7M381.6 81.3h1.9M23.5 118.1v1.3M39.4 103.4h42.4M62 103.4v1M121.9 100.4v22.8h15.3v102.9h16.5"/>
<path d="M153.7 100.4h-2.6v-6.4h28v6.4h62.2v11.4M153.7 111.8h17.7M168.9 102.9h1.3v3.8h1.2M186.7 109.3h1.3v7.6h1.2M204.5 119.4h7.6v7.6h4.4M217.2 114.3h1.2M219.7 109.3h7.6M226.1 114.3h1.2M237.5 111.8h8.9M261.6 109.3h15.3M292.1 106.7h1.3v7.6h-49.6v6.4h2.6M58.2 131.4h22.6"/>
<path d="M79 133.9h1.8v16.5h41.1v24.9h95.3v14h-3.1M94.2 132.6h.5M101.9 132.6h.2v4.6M116.1 132.6h.7M151.1 137.2h19.7M166.4 120.7h-41.9v38.1h-40.7M166.4 125.8h-26.7v97.8h14M181.6 123.2v4.5h-10.8v4.4M189.2 122h-5.1v-7.7h-52v61M189.2 129.6h-3.1v5.1M189.2 134.7h-1.2v10.1h-20.4M204.5 132.1h12"/>
<path d="M231.8 129.6h2.5v9.5h-43.8v7h1.3M246.4 125.8h-3.8v33h-7.7M246.4 139.7h-1.3v33.1h-100.3v45.7h8.9M261.6 123.2h1.3v5.1h-19.1v6.4h2.6M261.6 137.2v5.1h15.3M269.9 134h2.5M282.6 134h10.8v9.5M48.3 151.2v2.5M48.3 158.8v2.5M154.9 147.4h2.6M176.5 151.2h-49.5v12.7h-43.2M207 153.7h-21.6v3.8h-43.2v63.5h11.5"/>
<path d="M219.7 158.8h-90.2v10.1h-45.7M238.3 148.9h-16.1v2.3h.3M292.1 142.3h5.1M293.4 151.2v1.2M337.2 144.8h25.4M343.5 147.4h19.1M361.3 149.9h1.3M377.8 147.4h1.3M377.8 149.9h3.8M385.4 144.8h3.9v5.1M386.7 147.4h2.6M40.6 171.5h7.7"/>
<path d="M40.6 166.4h7.7M40.6 176.6h7.7M160 165.1h-26.7v6.4h-49.5M175.3 165.1h3.8M179.1 170.2h-44.5v62.2h.7M194.3 167.7h19.1M262.3 163.9h1.2M265.4 176.6h-3.8v27.9h-26.7v16.5h-1.2M273.7 161.3h1.3M288.3 176.6h1.9M341.6 162h17.8M341.6 167h17.8"/>
<path d="M351.2 177.2h11.4M374.6 162h3.9M374.6 167h3.9M377.8 177.2h3.8v32.4M40.6 181.6h7.7M48.3 184.2h-6.4v2.5h-1.3M102.9 185.5v2.5h5M115.6 188h1.2M154.3 186.7h1.9M160 198.2h1.3M166.4 189.3h2.5v8.9M168.9 184.2h-21.6v31.7h6.4"/>
<path d="M184.1 186.7h14.8M198.4 191.8h.5M265.4 190.5h-2.5v16.5h-26.7v16.6h-2.5M271.8 181.6h1.2M271.8 195.6h1.2M288.3 181.6h2.5M288.3 195.6h1.3M288.3 190.5h2.5M345.4 199.4h17.2M348.6 192.4h14M351.2 184.8h11.4M377.8 199.4h3.8"/>
<path d="M377.8 192.4h3.8M377.8 184.8h3.8M52.1 212.1v1.3h-31.1M72.4 212.1v1.3M85.1 212.1v1.3M189.2 213.4h2.1M196.8 218.5h-6.3v2.5h-1.3M261.6 219.7h-19v16.6h-8.9M261.6 217.2h-20.3v16.5h-7.6M261.6 212.1h-22.8v16.5h-5.1M261.6 209.6h-24.1v16.5h-3.8M261.6 214.7h-21.6v16.5h-6.3"/>
<path d="M304.8 214.7h5.7M304.8 209.6h1.9M306.7 214.7v2.5h-1.9M346.7 206.4h15.9M377.8 206.4h3.8M21 235v1.3M41.3 228.6v3.8M72.4 238.8v1.3M85.1 238.8v1.3M116.8 228.6h.7M131.4 228.6h22.3M149.2 233.7h5.7v24.1h-12"/>
<path d="M149.2 231.2h4.5M189.2 228.6h31.8M189.2 238.8h2.6v2.5h29.2M189.2 236.3h31.8M189.2 233.7h31.8M189.2 226.1h31.8M189.2 231.2h31.8M199.4 236.3v30.4M201.9 233.7v33M204.5 231.2v35.5M207 228.6v38.1M209.5 226.1v40.6"/>
<path d="M218.4 238.8h2.6M232.4 238.8h1.3M254 227.4h-9.5v3.8h3.1M304.8 232.4h25.4M304.8 227.4h25.4M304.8 224.8h25.4M304.8 222.3h25.4M304.8 229.9h25.4M304.8 235h1.3v2.5h-1.3M360.7 224.2h6.3M360.7 231.8h6.3M387.3 224.2h6.4"/>
<path d="M387.3 231.8h6.4M80.6 255.3h1.3M97.2 257.8v3.2h-10.2v10.8M114.3 246.4v6.4h-1.9M128.9 255.3h3.8M189.2 241.3h1.3v2.6h30.5M189.2 243.9v2.5h31.8M191.8 246.4v20.3M194.3 243.9v22.8M196.8 241.3v25.4M204.5 259.1h-35.6v7.6M207 257.8h-40.6v8.9"/>
<path d="M209.5 256.6h-45.7v10.1M221 251.5h-6.4v.6M221 249h-8.9v3.1M221 256.6h-1.3v.6M221 254h-3.8v3.2M233.7 241.3h7M233.7 256.6h2.5M233.7 246.4h31.7v6.4M233.7 254h2.5M233.7 251.5h2.5M233.7 243.9h15.2M233.7 249h2.5"/>
<path d="M256.5 243.9h1.9M262.9 240.7v.6h-14.6M304.8 240.1h7.6v11.4h-47M304.8 245.1h1.3M84.5 268h7.6M122.6 273.7h3.1M130.8 260.4h1.9M135.9 271.2h.6M163.8 276.9v1.3M181.6 276.9v1.3M191.8 265.5h-5.1v1.2M194.3 264.2h-10.2v2.5"/>
<path d="M196.8 262.9h-15.2v3.8M199.4 261.7h-20.3v5M201.9 260.4h-25.4v6.3M209.5 276.9v1.3M265.4 260.4v1.3"/>
</g>
<g fill="none" stroke="#000084" stroke-width=".18">
<path d="M230.5 66.7l1.2 1.3M231.7 66.7l-1.2 1.3M181 83.2l1.2 1.3M182.2 83.2l-1.2 1.3M184.8 80.7l1.2 1.2M184.8 83.2l1.2 1.3M186 80.7l-1.2 1.2M186 83.2l-1.2 1.3M230.5 80.7l1.2 1.2M230.5 83.2l1.2 1.3M231.7 80.7l-1.2 1.2M231.7 83.2l-1.2 1.3"/>
<path d="M149.3 104.8l1.2 1.3M150.5 104.8l-1.2 1.3M136.6 120.1l1.2 1.2M137.8 120.1l-1.2 1.2M149.3 125.2l1.2 1.2M149.3 120.1l1.2 1.2M150.5 125.2l-1.2 1.2M150.5 120.1l-1.2 1.2M116.2 153.1l1.2 1.2M116.2 158.2l1.2 1.2M117.4 158.2l-1.2 1.2M117.4 153.1l-1.2 1.2"/>
<path d="M116.2 170.9l1.2 1.2M116.2 168.3l1.2 1.3M116.2 163.3l1.2 1.2M117.4 170.9l-1.2 1.2M117.4 168.3l-1.2 1.3M117.4 163.3l-1.2 1.2M134 228l1.2 1.2M135.2 228l-1.2 1.2"/>
</g>
<g fill="#008400" stroke="#008400" stroke-width=".18">
<circle cx="67.3" cy="46.4" r=".46"/>
<circle cx="53.3" cy="46.4" r=".46"/>
<circle cx="53.3" cy="71.8" r=".46"/>
<circle cx="67.8" cy="78" r=".46"/>
<circle cx="25.4" cy="71.8" r=".46"/>
<circle cx="39.4" cy="46.4" r=".46"/>
<circle cx="67.3" cy="71.8" r=".46"/>
<circle cx="181.6" cy="81.3" r=".46"/>
<circle cx="185.4" cy="78.8" r=".46"/>
<circle cx="130.8" cy="39.4" r=".46"/>
<circle cx="134.6" cy="78.8" r=".46"/>
<circle cx="114.3" cy="63.5" r=".46"/>
<circle cx="114.3" cy="67.3" r=".46"/>
<circle cx="96.5" cy="72.4" r=".46"/>
<circle cx="105.4" cy="80" r=".46"/>
<circle cx="81.8" cy="78" r=".46"/>
<circle cx="62" cy="103.4" r=".46"/>
<circle cx="67.8" cy="103.4" r=".46"/>
<circle cx="52.3" cy="103.4" r=".46"/>
<circle cx="52.3" cy="78" r=".46"/>
<circle cx="39.4" cy="71.8" r=".46"/>
<circle cx="209.5" cy="256.6" r=".46"/>
<circle cx="207" cy="257.8" r=".46"/>
<circle cx="191.8" cy="246.4" r=".46"/>
<circle cx="199.4" cy="261.7" r=".46"/>
<circle cx="265.4" cy="251.5" r=".46"/>
<circle cx="201.9" cy="260.4" r=".46"/>
<circle cx="204.5" cy="259.1" r=".46"/>
<circle cx="306.7" cy="214.7" r=".46"/>
<circle cx="306.1" cy="237.5" r=".46"/>
<circle cx="356.9" cy="29.9" r=".46"/>
<circle cx="368.3" cy="29.9" r=".46"/>
<circle cx="356.9" cy="21.6" r=".46"/>
<circle cx="345.4" cy="21.6" r=".46"/>
<circle cx="368.3" cy="21.6" r=".46"/>
<circle cx="276.9" cy="83.9" r=".46"/>
<circle cx="303.5" cy="96.6" r=".46"/>
<circle cx="308.6" cy="96.6" r=".46"/>
<circle cx="306.1" cy="96.6" r=".46"/>
<circle cx="293.4" cy="142.3" r=".46"/>
<circle cx="389.3" cy="144.8" r=".46"/>
<circle cx="345.4" cy="29.9" r=".46"/>
<circle cx="316.2" cy="29.9" r=".46"/>
<circle cx="335.3" cy="21.6" r=".46"/>
<circle cx="325.1" cy="21.6" r=".46"/>
<circle cx="335.3" cy="29.9" r=".46"/>
<circle cx="316.2" cy="21.6" r=".46"/>
<circle cx="325.1" cy="29.9" r=".46"/>
<circle cx="306.1" cy="77.5" r=".46"/>
<circle cx="308.6" cy="80" r=".46"/>
<circle cx="389.3" cy="147.4" r=".46"/>
<circle cx="381.6" cy="199.4" r=".46"/>
<circle cx="381.6" cy="192.4" r=".46"/>
<circle cx="381.6" cy="184.8" r=".46"/>
<circle cx="381.6" cy="206.4" r=".46"/>
<circle cx="209.5" cy="226.1" r=".46"/>
<circle cx="168.9" cy="189.3" r=".46"/>
<circle cx="204.5" cy="231.2" r=".46"/>
<circle cx="116.8" cy="228.6" r=".46"/>
<circle cx="87" cy="268" r=".46"/>
<circle cx="80.8" cy="133.9" r=".46"/>
<circle cx="102.1" cy="132.6" r=".46"/>
<circle cx="116.8" cy="132.6" r=".46"/>
<circle cx="52.1" cy="213.4" r=".46"/>
<circle cx="31.1" cy="213.4" r=".46"/>
<circle cx="41.3" cy="213.4" r=".46"/>
<circle cx="196.8" cy="262.9" r=".46"/>
<circle cx="191.8" cy="265.5" r=".46"/>
<circle cx="194.3" cy="264.2" r=".46"/>
<circle cx="207" cy="228.6" r=".46"/>
<circle cx="116.8" cy="188" r=".46"/>
<circle cx="48.3" cy="158.8" r=".46"/>
<circle cx="132.1" cy="175.3" r=".46"/>
<circle cx="270.5" cy="77.5" r=".46"/>
<circle cx="303.5" cy="75" r=".46"/>
<circle cx="301" cy="72.4" r=".46"/>
<circle cx="270.5" cy="72.4" r=".46"/>
<circle cx="222.2" cy="151.2" r=".46"/>
<circle cx="241.3" cy="111.8" r=".46"/>
<circle cx="270.5" cy="75" r=".46"/>
<circle cx="250.2" cy="69.9" r=".46"/>
<circle cx="234.9" cy="78.1" r=".46"/>
</g>
<use href="#words"/>
</svg>
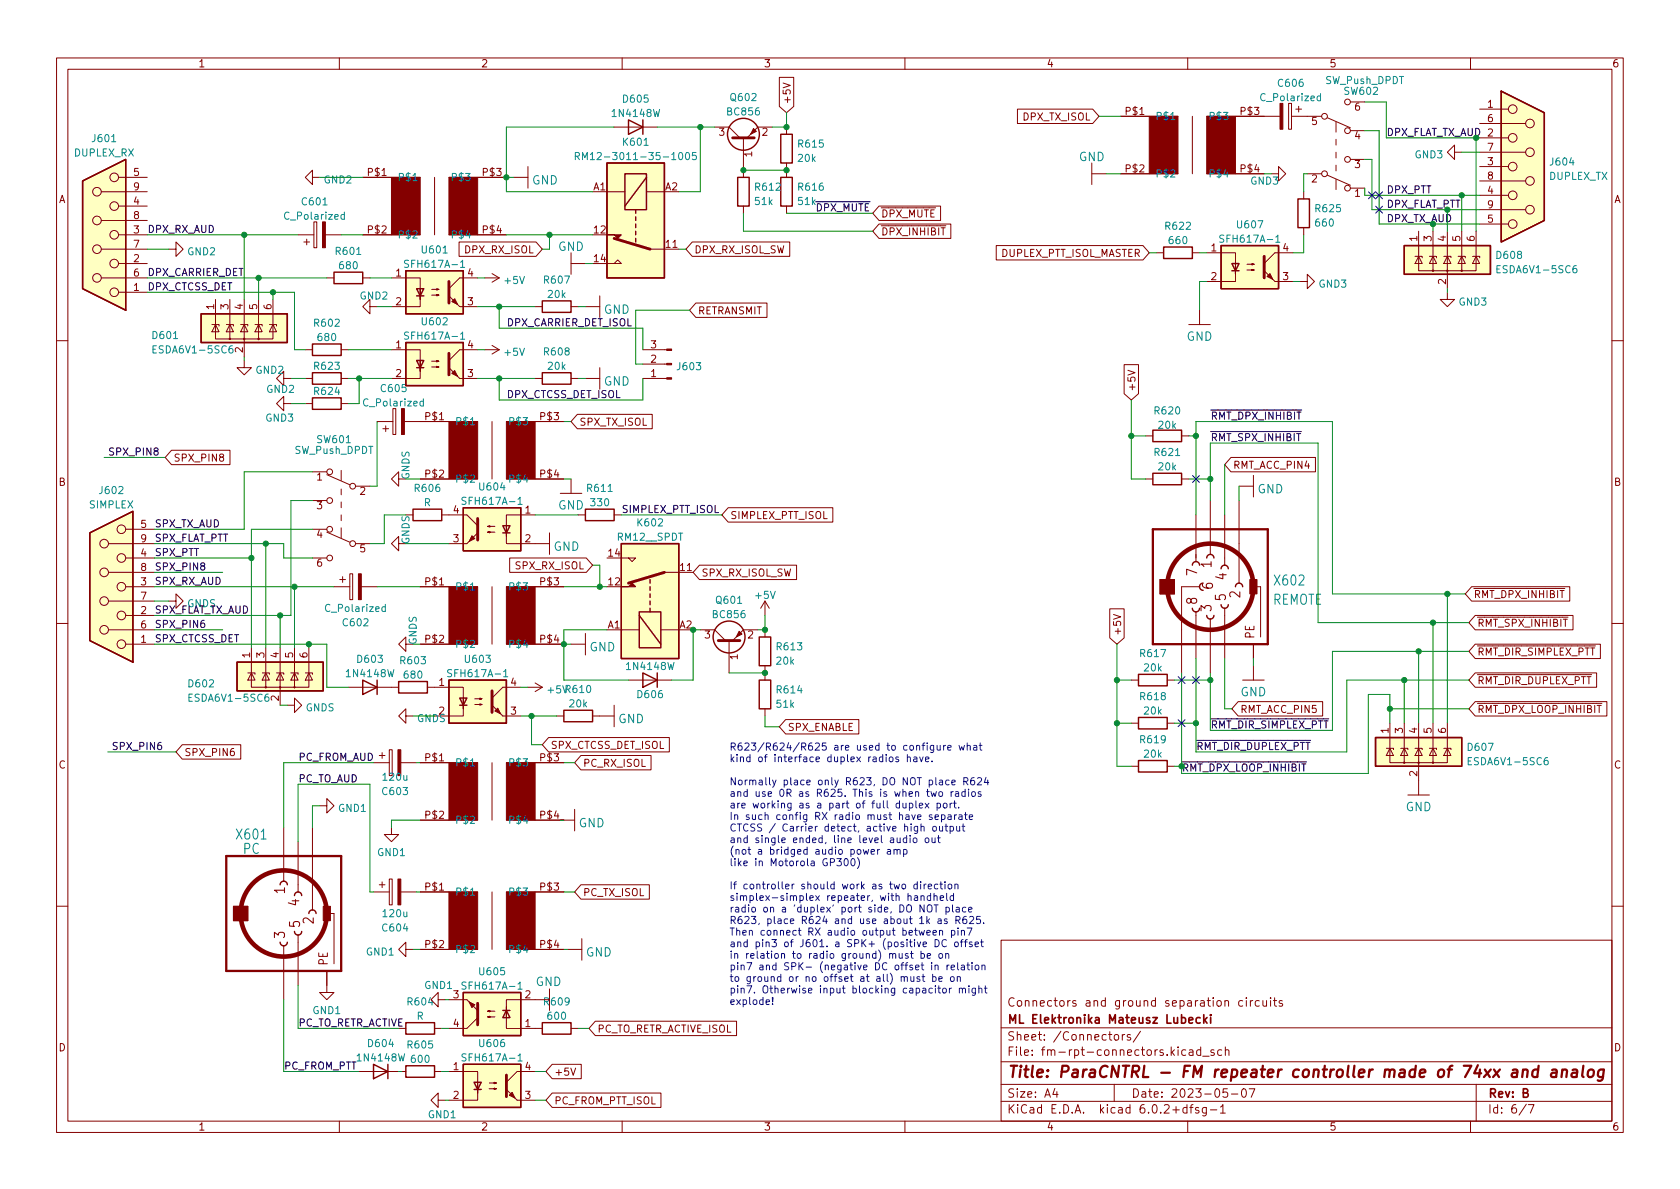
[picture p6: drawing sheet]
<svg xmlns="http://www.w3.org/2000/svg" width="297mm" height="210mm" viewBox="0 0 297 210" stroke-linecap="round" stroke-linejoin="round" font-family="sans-serif">
<defs><g id="words">
<text font-size="2.8" fill="#840000" x="178" y="190.6">Title: ParaCNTRL - FM repeater controller made of 74xx and analog</text>
<g font-size="2.5" fill="#840000">
<text x="211.7" y="101.7" transform="rotate(-90 211.7 101.7)">7</text>
<text x="214.2" y="100.3" transform="rotate(-90 214.2 100.3)">1</text>
<text x="211.7" y="106.8" transform="rotate(-90 211.7 106.8)">8</text>
<text x="214.5" y="104.2" transform="rotate(-90 214.5 104.2)">6</text>
<text x="216.8" y="106.2" transform="rotate(-90 216.8 106.2)">5</text>
<text x="216.9" y="102.5" transform="rotate(-90 216.9 102.5)">4</text>
<text x="219.3" y="105.7" transform="rotate(-90 219.3 105.7)">2</text>
<text x="214.2" y="108.1" transform="rotate(-90 214.2 108.1)">3</text>
<text x="50.4" y="158" transform="rotate(-90 50.4 158)">1</text>
<text x="52.9" y="160.2" transform="rotate(-90 52.9 160.2)">4</text>
<text x="50.4" y="165.9" transform="rotate(-90 50.4 165.9)">3</text>
<text x="53.1" y="164" transform="rotate(-90 53.1 164)">5</text>
<text x="55.5" y="163.3" transform="rotate(-90 55.5 163.3)">2</text>
</g>
<g font-size="2.5" fill="#008484">
<text x="224.9" y="106.9">REMOTE</text>
<text x="225.5" y="103.5">X602</text>
<text x="42" y="148.5">X601</text>
<text x="43" y="151">PC</text>
</g>
<g font-size="2.1" fill="#008484">
<text x="190.7" y="28.5">GND</text>
<text x="94" y="32.6">GND</text>
<text x="98.6" y="44.4">GND</text>
<text x="106.7" y="55.5">GND</text>
<text x="209.8" y="60.3">GND</text>
<text x="106.7" y="68.2">GND</text>
<text x="222.3" y="87.2">GND</text>
<text x="98.6" y="90.1">GND</text>
<text x="97.8" y="97.4">GND</text>
<text x="104.2" y="115.2">GND</text>
<text x="219.3" y="123.1">GND</text>
<text x="109.3" y="127.9">GND</text>
<text x="248.5" y="143.4">GND</text>
<text x="102.3" y="146.3">GND</text>
<text x="103.6" y="169.1">GND</text>
<text x="94.7" y="174.4">GND</text>
</g>
<g font-size="2.1" fill="#840000">
<text x="221.8" y="112.9" transform="rotate(-90 221.8 112.9)">PE</text>
<text x="58" y="170.7" transform="rotate(-90 58 170.7)">PE</text>
<text x="178" y="178">Connectors and ground separation circuits</text>
<text x="178" y="184">Sheet: /Connectors/</text>
<text x="178" y="181">ML Elektronika Mateusz Lubecki</text>
<text x="178" y="186.7">File: fm-rpt-connectors.kicad_sch</text>
<text x="178" y="196.9">KiCad E.D.A. kicad 6.0.2+dfsg-1</text>
<text x="178" y="194.1">Size: A4</text>
<text x="200" y="194.1">Date: 2023-05-07</text>
<text x="263" y="194.1">Rev: B</text>
<text x="263" y="196.9">Id: 6/7</text>
</g>
<g font-size="1.8" fill="#840000">
<text x="35" y="11.9">1</text>
<text x="85" y="11.9">2</text>
<text x="135" y="11.9">3</text>
<text x="185" y="11.9">4</text>
<text x="235" y="11.9">5</text>
<text x="285" y="11.9">6</text>
<text x="127.1" y="24">3</text>
<text x="134.8" y="24">2</text>
<text x="139.8" y="18.5" transform="rotate(-90 139.8 18.5)">+5V</text>
<text x="180.9" y="21.3">DPX_TX_ISOL</text>
<text x="199.1" y="20.3">P$1</text>
<text x="219.4" y="20.3">P$3</text>
<text x="231.9" y="22.1">5</text>
<text x="239.5" y="19.6">6</text>
<text x="263" y="19">1</text>
<text x="263" y="21.6">6</text>
<text x="133" y="27.7" transform="rotate(-90 133 27.7)">1</text>
<text x="239.5" y="29.7">3</text>
<text x="239.5" y="24.6">4</text>
<text x="263" y="29.2">3</text>
<text x="263" y="26.7">7</text>
<text x="10.3" y="35.9">A</text>
<text x="23.6" y="31.1">5</text>
<text x="23.6" y="33.6">9</text>
<text x="65.1" y="31.1">P$1</text>
<text x="85.4" y="31.1">P$3</text>
<text x="104.9" y="33.6">A1</text>
<text x="117.6" y="33.6">A2</text>
<text x="199.1" y="30.5">P$2</text>
<text x="219.4" y="30.5">P$4</text>
<text x="231.9" y="32.3">2</text>
<text x="239.5" y="34.8">1</text>
<text x="263" y="34.3">4</text>
<text x="263" y="31.7">8</text>
<text x="285.3" y="35.9">A</text>
<text x="23.6" y="41.3">3</text>
<text x="23.6" y="36.2">4</text>
<text x="23.6" y="38.7">8</text>
<text x="65.1" y="41.3">P$2</text>
<text x="85.4" y="41.3">P$4</text>
<text x="105.1" y="41.3">12</text>
<text x="155.7" y="41.6">~{DPX_INHIBIT}</text>
<text x="155.7" y="38.4">~{DPX_MUTE}</text>
<text x="263" y="39.4">5</text>
<text x="263" y="36.8">9</text>
<text x="23.6" y="46.3">2</text>
<text x="23.6" y="43.8">7</text>
<text x="82.3" y="44.8">DPX_RX_ISOL</text>
<text x="105.1" y="46.3">14</text>
<text x="117.8" y="43.8">11</text>
<text x="122.7" y="44.8">DPX_RX_ISOL_SW</text>
<text x="176.7" y="45.4">DUPLEX_PTT_ISOL_MASTER</text>
<text x="214.1" y="44.4">1</text>
<text x="226.8" y="44.4">4</text>
<text x="250.6" y="42.7" transform="rotate(-90 250.6 42.7)">1</text>
<text x="253.1" y="42.7" transform="rotate(-90 253.1 42.7)">3</text>
<text x="255.7" y="42.7" transform="rotate(-90 255.7 42.7)">4</text>
<text x="258.2" y="42.7" transform="rotate(-90 258.2 42.7)">5</text>
<text x="260.7" y="42.7" transform="rotate(-90 260.7 42.7)">6</text>
<text x="23.6" y="51.4">1</text>
<text x="23.6" y="48.9">6</text>
<text x="70" y="48.9">1</text>
<text x="70" y="54">2</text>
<text x="82.7" y="54">3</text>
<text x="82.7" y="48.9">4</text>
<text x="214.1" y="49.5">2</text>
<text x="226.8" y="49.5">3</text>
<text x="255.7" y="50.3" transform="rotate(-90 255.7 50.3)">2</text>
<text x="37.8" y="54.7" transform="rotate(-90 37.8 54.7)">1</text>
<text x="40.4" y="54.7" transform="rotate(-90 40.4 54.7)">3</text>
<text x="42.9" y="54.7" transform="rotate(-90 42.9 54.7)">4</text>
<text x="45.5" y="54.7" transform="rotate(-90 45.5 54.7)">5</text>
<text x="48" y="54.7" transform="rotate(-90 48 54.7)">6</text>
<text x="123.3" y="55.6">RETRANSMIT</text>
<text x="42.9" y="62.3" transform="rotate(-90 42.9 62.3)">2</text>
<text x="70" y="61.6">1</text>
<text x="82.7" y="61.6">4</text>
<text x="115.1" y="64.1">2</text>
<text x="115.1" y="61.6">3</text>
<text x="70" y="66.7">2</text>
<text x="82.7" y="66.7">3</text>
<text x="115.1" y="66.7">1</text>
<text x="200.8" y="69.3" transform="rotate(-90 200.8 69.3)">+5V</text>
<text x="75.3" y="74.3">P$1</text>
<text x="95.6" y="74.3">P$3</text>
<text x="102.4" y="75.3">SPX_TX_ISOL</text>
<text x="30.6" y="81.6">SPX_PIN8</text>
<text x="218" y="82.9">RMT_ACC_PIN4</text>
<text x="10.3" y="85.9">B</text>
<text x="56" y="85">1</text>
<text x="63.6" y="87.5">2</text>
<text x="75.3" y="84.4">P$2</text>
<text x="95.6" y="84.4">P$4</text>
<text x="285.3" y="85.9">B</text>
<text x="24.9" y="93.3">5</text>
<text x="24.9" y="95.9">9</text>
<text x="56" y="90">3</text>
<text x="56" y="95.1">4</text>
<text x="80.2" y="95.9">3</text>
<text x="80.2" y="90.8">4</text>
<text x="92.9" y="90.8">1</text>
<text x="92.9" y="95.9">2</text>
<text x="129.1" y="91.8">SIMPLEX_PTT_ISOL</text>
<text x="24.9" y="98.4">4</text>
<text x="24.9" y="101">8</text>
<text x="56" y="100.2">6</text>
<text x="63.6" y="97.7">5</text>
<text x="91.3" y="100.7">SPX_RX_ISOL</text>
<text x="107.6" y="98.4">14</text>
<text x="120.3" y="101">11</text>
<text x="124" y="101.9">SPX_RX_ISOL_SW</text>
<text x="24.9" y="103.5">3</text>
<text x="24.9" y="106">7</text>
<text x="75.3" y="103.5">P$1</text>
<text x="95.6" y="103.5">P$3</text>
<text x="107.6" y="103.5">12</text>
<text x="260.5" y="105.7">~{RMT_DPX_INHIBIT}</text>
<text x="24.9" y="113.7">1</text>
<text x="24.9" y="108.6">2</text>
<text x="24.9" y="111.1">6</text>
<text x="75.3" y="113.7">P$2</text>
<text x="95.6" y="113.7">P$4</text>
<text x="107.5" y="111.1">A1</text>
<text x="120.2" y="111.1">A2</text>
<text x="124.6" y="112.9">3</text>
<text x="132.2" y="112.9">2</text>
<text x="198.2" y="112.5" transform="rotate(-90 198.2 112.5)">+5V</text>
<text x="261.1" y="110.8">~{RMT_SPX_INHIBIT}</text>
<text x="44.2" y="116.3" transform="rotate(-90 44.2 116.3)">1</text>
<text x="46.7" y="116.3" transform="rotate(-90 46.7 116.3)">3</text>
<text x="49.3" y="116.3" transform="rotate(-90 49.3 116.3)">4</text>
<text x="51.8" y="116.3" transform="rotate(-90 51.8 116.3)">5</text>
<text x="54.4" y="116.3" transform="rotate(-90 54.4 116.3)">6</text>
<text x="130.4" y="116.6" transform="rotate(-90 130.4 116.6)">1</text>
<text x="261.1" y="115.9">~{RMT_DIR_SIMPLEX_PTT}</text>
<text x="49.3" y="123.9" transform="rotate(-90 49.3 123.9)">2</text>
<text x="77.6" y="121.3">1</text>
<text x="90.3" y="121.3">4</text>
<text x="261.1" y="121">~{RMT_DIR_DUPLEX_PTT}</text>
<text x="77.6" y="126.4">2</text>
<text x="90.3" y="126.4">3</text>
<text x="139.2" y="129.2">SPX_ENABLE</text>
<text x="219.2" y="126.1">RMT_ACC_PIN5</text>
<text x="245.5" y="129.6" transform="rotate(-90 245.5 129.6)">1</text>
<text x="248" y="129.6" transform="rotate(-90 248 129.6)">3</text>
<text x="250.6" y="129.6" transform="rotate(-90 250.6 129.6)">4</text>
<text x="253.1" y="129.6" transform="rotate(-90 253.1 129.6)">5</text>
<text x="255.7" y="129.6" transform="rotate(-90 255.7 129.6)">6</text>
<text x="261.1" y="126.1">~{RMT_DPX_LOOP_INHIBIT}</text>
<text x="10.3" y="135.9">C</text>
<text x="32.5" y="133.7">SPX_PIN6</text>
<text x="75.3" y="134.6">P$1</text>
<text x="95.6" y="134.6">P$3</text>
<text x="97.3" y="132.4">SPX_CTCSS_DET_ISOL</text>
<text x="103" y="135.6">PC_RX_ISOL</text>
<text x="250.6" y="137.3" transform="rotate(-90 250.6 137.3)">2</text>
<text x="285.3" y="135.9">C</text>
<text x="75.3" y="144.8">P$2</text>
<text x="95.6" y="144.8">P$4</text>
<text x="75.3" y="157.5">P$1</text>
<text x="95.6" y="157.5">P$3</text>
<text x="103" y="158.5">PC_TX_ISOL</text>
<text x="75.3" y="167.6">P$2</text>
<text x="95.6" y="167.6">P$4</text>
<text x="80.2" y="176.5">3</text>
<text x="92.9" y="176.5">2</text>
<text x="10.3" y="185.9">D</text>
<text x="80.2" y="181.6">4</text>
<text x="92.9" y="181.6">1</text>
<text x="105.6" y="182.6">PC_TO_RETR_ACTIVE_ISOL</text>
<text x="285.3" y="185.9">D</text>
<text x="80.2" y="189.2">1</text>
<text x="92.9" y="189.2">4</text>
<text x="97.9" y="190.2">+5V</text>
<text x="80.2" y="194.3">2</text>
<text x="92.9" y="194.3">3</text>
<text x="97.9" y="195.3">PC_FROM_PTT_ISOL</text>
<text x="35" y="199.9">1</text>
<text x="85" y="199.9">2</text>
<text x="135" y="199.9">3</text>
<text x="185" y="199.9">4</text>
<text x="235" y="199.9">5</text>
<text x="285" y="199.9">6</text>
</g>
<g font-size="1.8" fill="#008484">
<text x="129.3" y="17.9">Q602</text>
<text x="223.2" y="17.9">C_Polarized</text>
<text x="226.1" y="15.3">C606</text>
<text x="234.3" y="14.9">SW_Push_DPDT</text>
<text x="237.8" y="16.8">SW602</text>
<text x="108.5" y="20.7">1N4148W</text>
<text x="110.3" y="18.1">D605</text>
<text x="128.7" y="20.4">BC856</text>
<text x="204.2" y="21.2">P$1</text>
<text x="214.3" y="21.2">P$3</text>
<text x="13.1" y="27.7">DUPLEX_RX</text>
<text x="16.4" y="25.1">J601</text>
<text x="104.2" y="28.3">RM12-3011-35-1005</text>
<text x="110.3" y="25.8">K601</text>
<text x="141.2" y="28.6">20k</text>
<text x="141.3" y="26.1">R615</text>
<text x="250.2" y="28">GND3</text>
<text x="274.2" y="29.3">J604</text>
<text x="57.3" y="32.4">GND2</text>
<text x="70.2" y="32">P$1</text>
<text x="80.3" y="32">P$3</text>
<text x="133.6" y="33.7">R612</text>
<text x="141.3" y="33.7">R616</text>
<text x="204.2" y="31.4">P$2</text>
<text x="214.3" y="31.4">P$4</text>
<text x="273.9" y="31.8">DUPLEX_TX</text>
<text x="50.6" y="38.8">C_Polarized</text>
<text x="53.5" y="36.3">C601</text>
<text x="133.6" y="36.2">51k</text>
<text x="141.2" y="36.2">51k</text>
<text x="206.2" y="40.6">R622</text>
<text x="218.9" y="40.4">U607</text>
<text x="232.7" y="37.5">R625</text>
<text x="232.7" y="40.1">660</text>
<text x="33.2" y="45.1">GND2</text>
<text x="59.5" y="45.1">R601</text>
<text x="60.1" y="47.6">680</text>
<text x="70.2" y="42.2">P$2</text>
<text x="72.2" y="47.3">SFH617A-1</text>
<text x="74.7" y="44.8">U601</text>
<text x="80.3" y="42.2">P$4</text>
<text x="206.8" y="43.2">660</text>
<text x="216.3" y="42.9">SFH617A-1</text>
<text x="264.7" y="45.8">D608</text>
<text x="63.7" y="53">GND2</text>
<text x="89.3" y="50.2">+5V</text>
<text x="96.3" y="50.1">R607</text>
<text x="96.9" y="52.7">20k</text>
<text x="233.2" y="50.8">GND3</text>
<text x="265.2" y="48.3">ESDA6V1-5SC6</text>
<text x="27.1" y="59.9">D601</text>
<text x="55.7" y="57.8">R602</text>
<text x="74.7" y="57.5">U602</text>
<text x="258" y="54">GND3</text>
<text x="27.6" y="62.5">ESDA6V1-5SC6</text>
<text x="55.7" y="65.4">R623</text>
<text x="56.3" y="60.3">680</text>
<text x="72.2" y="60">SFH617A-1</text>
<text x="89.3" y="62.9">+5V</text>
<text x="96.3" y="62.8">R608</text>
<text x="96.9" y="65.4">20k</text>
<text x="119.9" y="65.5">J603</text>
<text x="45.2" y="66.1">GND2</text>
<text x="47.2" y="69.5">GND2</text>
<text x="55.7" y="69.8">R624</text>
<text x="64.5" y="71.9">C_Polarized</text>
<text x="67.5" y="69.3">C605</text>
<text x="47" y="74.5">GND3</text>
<text x="80.4" y="75.2">P$1</text>
<text x="90.5" y="75.2">P$3</text>
<text x="204.3" y="73.3">R620</text>
<text x="204.9" y="75.8">20k</text>
<text x="52.1" y="80.3">SW_Push_DPDT</text>
<text x="56.2" y="78.4">SW601</text>
<text x="204.3" y="80.6">R621</text>
<text x="204.9" y="83.2">20k</text>
<text x="15.8" y="89.9">SIMPLEX</text>
<text x="17.7" y="87.4">J602</text>
<text x="72.4" y="84.8" transform="rotate(-90 72.4 84.8)">GNDS</text>
<text x="73.5" y="87">R606</text>
<text x="74.9" y="89.5">R</text>
<text x="80.4" y="85.3">P$2</text>
<text x="82.3" y="89.3">SFH617A-1</text>
<text x="84.9" y="86.7">U604</text>
<text x="90.5" y="85.3">P$4</text>
<text x="103.9" y="87">R611</text>
<text x="104.6" y="89.5">330</text>
<text x="109.2" y="95.6">RM12__SPDT</text>
<text x="112.8" y="93.1">K602</text>
<text x="72.4" y="96.2" transform="rotate(-90 72.4 96.2)">GNDS</text>
<text x="80.4" y="104.4">P$1</text>
<text x="90.5" y="104.4">P$3</text>
<text x="126.7" y="106.8">Q601</text>
<text x="133.7" y="105.9">+5V</text>
<text x="57.8" y="108.2">C_Polarized</text>
<text x="60.8" y="110.7">C602</text>
<text x="126.2" y="109.3">BC856</text>
<text x="61.5" y="119.7">1N4148W</text>
<text x="63.3" y="117.2">D603</text>
<text x="70.9" y="117.5">R603</text>
<text x="71.5" y="120">680</text>
<text x="79.8" y="119.7">SFH617A-1</text>
<text x="80.4" y="114.5">P$2</text>
<text x="82.3" y="117.2">U603</text>
<text x="90.5" y="114.5">P$4</text>
<text x="111" y="118.5">1N4148W</text>
<text x="137.4" y="117.5">20k</text>
<text x="137.4" y="115">R613</text>
<text x="201.7" y="116.2">R617</text>
<text x="202.4" y="118.7">20k</text>
<text x="33.4" y="121.5">D602</text>
<text x="33.9" y="124.1">ESDA6V1-5SC6</text>
<text x="54" y="125.8">GNDS</text>
<text x="96.9" y="122.6">+5VR610</text>
<text x="100.8" y="125.1">20k</text>
<text x="112.8" y="123.4">D606</text>
<text x="137.4" y="125.1">51k</text>
<text x="137.4" y="122.6">R614</text>
<text x="201.7" y="123.8">R618</text>
<text x="73.7" y="127.7">GNDS</text>
<text x="201.7" y="131.4">R619</text>
<text x="202.4" y="126.3">20k</text>
<text x="80.4" y="135.5">P$1</text>
<text x="90.5" y="135.5">P$3</text>
<text x="202.4" y="134">20k</text>
<text x="259.6" y="132.8">D607</text>
<text x="260.1" y="135.3">ESDA6V1-5SC6</text>
<text x="59.9" y="143.6">GND1</text>
<text x="67.7" y="140.6">C603</text>
<text x="67.8" y="138">120u</text>
<text x="80.4" y="145.7">P$2</text>
<text x="90.5" y="145.7">P$4</text>
<text x="66.8" y="151.4">GND1</text>
<text x="80.4" y="158.4">P$1</text>
<text x="90.5" y="158.4">P$3</text>
<text x="67.7" y="164.7">C604</text>
<text x="67.8" y="162.2">120u</text>
<text x="64.8" y="169">GND1</text>
<text x="80.4" y="168.5">P$2</text>
<text x="84.9" y="172.4">U605</text>
<text x="90.5" y="168.5">P$4</text>
<text x="55.3" y="179.3">GND1</text>
<text x="72.2" y="177.8">R604</text>
<text x="75.1" y="174.9">GND1</text>
<text x="82.3" y="175">SFH617A-1</text>
<text x="96.3" y="177.8">R609</text>
<text x="65.2" y="185.1">D604</text>
<text x="72.2" y="185.4">R605</text>
<text x="73.7" y="180.3">R</text>
<text x="84.9" y="185.1">U606</text>
<text x="96.9" y="180.3">600</text>
<text x="63.4" y="187.7">1N4148W</text>
<text x="72.8" y="187.9">600</text>
<text x="82.3" y="187.7">SFH617A-1</text>
<text x="75.7" y="197.7">GND1</text>
</g>
<g font-size="1.8" fill="#008400">
<text x="245.1" y="24">DPX_FLAT_TX_AUD 2</text>
<text x="221.1" y="32.6">GND3</text>
<text x="245.1" y="36.7">DPX_FLAT_PTT</text>
<text x="245.1" y="39.3">DPX_TX_AUD</text>
<text x="73.7" y="114" transform="rotate(-90 73.7 114)">GNDS</text>
<text x="208.9" y="136.4">~{RMT_DPX_LOOP_INHIBIT}</text>
</g>
<g font-size="1.8">
<text x="245.1" y="34.2">DPX_PTT</text>
<text x="26" y="41.2">DPX_RX_AUD</text>
<text x="144.1" y="37.4">~{DPX_MUTE}</text>
<text x="26" y="51.3">DPX_CTCSS_DET</text>
<text x="26" y="48.8">DPX_CARRIER_DET</text>
<text x="89.5" y="57.7">DPX_CARRIER_DET_ISOL</text>
<text x="89.5" y="70.4">DPX_CTCSS_DET_ISOL</text>
<text x="214" y="74.2">~{RMT_DPX_INHIBIT}</text>
<text x="19" y="80.5">SPX_PIN8</text>
<text x="214" y="78">~{RMT_SPX_INHIBIT}</text>
<text x="27.3" y="93.2">SPX_TX_AUD</text>
<text x="27.3" y="95.8">SPX_FLAT_PTT</text>
<text x="109.9" y="90.7">SIMPLEX_PTT_ISOL</text>
<text x="27.3" y="100.9">SPX_PIN8</text>
<text x="27.3" y="98.3">SPX_PTT</text>
<text x="27.3" y="103.4">SPX_RX_AUD</text>
<text x="33.1" y="107.4">GNDS</text>
<text x="27.3" y="108.5">SPX_FLAT_TX_AUD</text>
<text x="27.3" y="111">SPX_PIN6</text>
<text x="27.3" y="113.6">SPX_CTCSS_DET</text>
<text x="214" y="128.8">~{RMT_DIR_SIMPLEX_PTT}</text>
<text x="19.7" y="132.6">SPX_PIN6</text>
<text x="52.7" y="134.5">PC_FROM_AUD</text>
<text x="211.5" y="132.6">~{RMT_DIR_DUPLEX_PTT}</text>
<text x="52.7" y="138.3">PC_TO_AUD</text>
<text x="52.7" y="181.5">PC_TO_RETR_ACTIVE</text>
<text x="50.2" y="189.1">PC_FROM_PTT</text>
</g>
<g font-size="1.8" fill="#0000c2">
<text x="128.9" y="132.7">R623/R624/R625 are used to configure what</text>
<text x="128.9" y="134.8">kind of interface duplex radios have.</text>
<text x="128.9" y="138.8">Normally place only R623, DO NOT place R624</text>
<text x="128.9" y="140.9">and use 0R as R625. This is when two radios</text>
<text x="128.9" y="142.9">are working as a part of full duplex port.</text>
<text x="128.9" y="145">In such config RX radio must have separate</text>
<text x="128.9" y="147">CTCSS / Carrier detect, active high output</text>
<text x="128.9" y="149.1">and single ended, line level audio out</text>
<text x="128.9" y="151.1">(not a bridged audio power amp</text>
<text x="128.9" y="153.2">like in Motorola GP300)</text>
<text x="128.9" y="157.3">If controller should work as two direction</text>
<text x="128.9" y="159.3">simplex-simplex repeater, with handheld</text>
<text x="128.9" y="161.3">radio on a 'duplex' port side, DO NOT place</text>
<text x="128.9" y="163.4">R623, place R624 and use about 1k as R625.</text>
<text x="128.9" y="165.4">Then connect RX audio output between pin7</text>
<text x="128.9" y="167.5">and pin3 of J601. a SPK+ (positive DC offset</text>
<text x="128.9" y="169.5">in relation to radio ground) must be on</text>
<text x="128.9" y="171.6">pin7 and SPK- (negative DC offset in relation</text>
<text x="128.9" y="173.6">to ground or no offset at all) must be on</text>
<text x="128.9" y="175.7">pin7. Otherwise input blocking capacitor might</text>
<text x="128.9" y="177.7">explode!</text>
</g>
</g></defs>
<g fill="none" stroke="#840000" stroke-width=".18">
<path d="M10 10.2h277v190.1h-277zM12 12.2h273v186.1h-273zM60 10.2v2M110 10.2v2M137.8 13.7h2.5v5.1l-1.2 1.1-1.3-1.1zM138.5 14.7l1.2 .4-1.2 .4M160 10.2v2M179.9 19.3h13.3l1.1 1.3-1.1 1.2h-13.3zM210 10.2v2M227.8 18.3h.5v4.6h-.5zM229.1 19.3h1M229.6 18.8v1"/>
<path d="M238.8 18h2.5M260 10.2v2M261.6 19.3h5.1M17.9 33.9h8.1M17.9 39h8.1M21 31.4h5M21 36.4h5M55.2 31.4v-1.3l-1.2 1.3 1.2 1.2v-1.2h1.3M55.5 39.2h.5v4.6h-.5zM64.1 31.4h10.2M76.8 31.4v10.1M79.4 31.4h10.1"/>
<path d="M90.8 31.4h2.5M93.3 29.5v3.8M107.3 33.9h3.2M108.6 22.5h7.6M114.3 33.9h3.2M126.4 22.5h2.5l1.9 1.9M131.4 24.4v7M131.4 36.4v1.3M136.5 22.5h-2.5l-1.9 1.9M139.1 22.5v1.2M139.1 28.8v2.6M139.1 36.4v1.3"/>
<path d="M155.4 39.6h12.7v2.6h-12.7l-1.1-1.3zM155.4 36.4h10.9v2.6h-10.9l-1.1-1.3zM193 30.7h2.6M193 28.8v3.8M198.1 30.7h10.2M198.1 20.6h10.2M210.8 20.6v10.1M213.4 30.7h10.1M213.4 20.6h12.9M224.8 30.7h1.3v-1.2l1.2 1.2-1.2 1.3v-1.3M228.3 20.6h5.4M230.5 33.9v1.3"/>
<path d="M231.1 30.7h2.6M234.7 20.8l4.1 1.8M234.7 31l4.1 1.8M236.2 21.6v1.8M236.2 24.6v1M236.2 26.9v1M236.2 29.2v1M236.2 31.7v1.8M238.8 33.3h2.5M238.8 28.2h2.5M238.8 23.1h2.5M257.2 26.9v-1.3l-1.3 1.3 1.3 1.3v-1.3h1.2"/>
<path d="M261.6 39.6h5.1M261.6 37.1h8.1M261.6 34.5h5.1M261.6 32h8.1M261.6 29.5h5.1M261.6 26.9h8.1M261.6 24.4h5.1M261.6 21.8h8.1M17.9 49.1h8.1M17.9 44.1h8.1M21 41.5h5M21 46.6h5"/>
<path d="M21 51.7h5M29.8 44.1h1.3v-1.3l1.3 1.3-1.3 1.2v-1.2M37.5 57.4h1.2v.3M38.1 57.4l.6 1.3h-1.2zM38.1 53v6.9h10.2v-6.9M40 57.4h1.3v.3M40.6 57.4l.7 1.3h-1.3zM40.6 53v6.9M42.5 57.4h1.3v.3M43.2 57.4l.6 1.3h-1.3zM43.2 53v10.1M45.1 57.4h1.3v.3"/>
<path d="M45.7 57.4l.7 1.3h-1.3zM45.7 53v6.9M47.6 57.4h1.3v.3M48.3 57.4l.6 1.3h-1.3zM52.7 41.5h2.8M53.7 42.8h1M54.2 42.3v1M57.5 41.5h2.8M57.8 49.1h1.3M64.1 49.1h1.3M64.1 41.5h10.2M65.4 54.2v-1.2l-1.3 1.2 1.3 1.3v-1.3h1.3"/>
<path d="M69.2 49.1h5.1v3.9v-2M74.3 52.3v1.9h-5.1M76.3 52.2h1.3l-.4 .1v-.2l.4 .1M76.3 51.2h1.3l-.4 .1v-.3l.4 .2M79.4 41.5h10.1M81.2 42.8h13.6l1.1 1.3-1.1 1.2h-13.6zM81.3 54.2h3.2M84.5 49.1h-3.2l-1.9 1.9M85.7 49.1h2.6M87 48.4l1.3 .7M88.3 49.1l-1.3 .8M94.6 54.2h1.3"/>
<path d="M101 46.6h2.5M101 54.2h1.2M101 44.7v3.8M103.5 54.2h2.5M106 52.3v3.8M107.3 46.6h2.6l-.7-.6-.6 .6M114.9 44.1h5.1M122.4 42.8h17.2v2.5h-17.2l-1.1-1.2zM123 53.6h12.6v2.5h-12.6l-1.1-1.2zM176.1 43.4h26l1.1 1.3-1.1 1.3h-26zM204.5 44.7h1.2M210.2 57.4h3.8"/>
<path d="M210.8 44.7h1.3M212.1 54.9v2.5M213.4 44.7h5v3.8v-1.9M218.4 47.9v1.9h-5M220.5 47.7h1.2l-.3 .2v-.3l.3 .1M220.5 46.7h1.2l-.3 .2v-.3l.3 .1M225.4 49.8h3.2M228.6 44.7h-3.2l-1.9 1.9M229.9 49.8h1.2v-1.3l1.3 1.3-1.3 1.2v-1.2M230.5 40.3v1.2M250.2 45.3h1.3v.3M250.8 45.3l.7 1.3h-1.3z"/>
<path d="M250.8 40.9v7h10.2v-7M252.7 45.3h1.3v.3M253.4 45.3l.6 1.3h-1.3zM253.4 40.9v7M255.3 45.3h1.2v.3M255.9 51.7v1.3h1.3l-1.3 1.2-1.3-1.2h1.3M255.9 45.3l.6 1.3h-1.2zM255.9 40.9v10.1M257.8 45.3h1.3v.3M258.4 45.3l.7 1.3h-1.3zM258.4 40.9v7M260.3 45.3h1.3v.3"/>
<path d="M261 45.3l.6 1.3h-1.3zM10 60.2h2M30.3 79.6h10.4v2.6h-10.4l-1.1-1.3zM43.2 63.7v1.3h1.2l-1.2 1.3-1.3-1.3h1.3M50.2 66.9v-1.2l-1.3 1.2 1.3 1.3v-1.3h1.2M50.2 71.4v-1.3l-1.3 1.3 1.3 1.2v-1.2h1.2M54 66.9h1.2M54 61.8h1.2M54 71.4h1.2M60.3 66.9h1.3M60.3 61.8h1.3M60.3 71.4h1.3"/>
<path d="M66.7 74.5h2.8M67.7 75.8h1M68.2 75.3v1M69.2 61.8h5.1v3.9v-2M69.5 72.3h.5v4.5h-.5zM71.5 74.5h13M74.3 65v1.9h-5.1M76.3 64.9h1.3l-.4 .1v-.2l.4 .1M76.3 63.9h1.3l-.4 .1v-.3l.4 .2M81.3 66.9h3.2M84.5 61.8h-3.2l-1.9 1.9M85.7 61.8h2.6"/>
<path d="M87 74.5v10.2M87 61.1l1.3 .7M88.3 61.8l-1.3 .8M89.5 74.5h10.2M94.6 66.9h1.3M101 66.9h1.2M102.1 73.3h13.2v2.5h-13.2l-1.1-1.3zM103.5 66.9h2.5M106 65v3.8M113.7 66.9h4.2M113.7 61.8h4.2M113.7 64.4h4.2"/>
<path d="M198.8 64.5h2.5v5.1l-1.3 1.1-1.2-1.1zM199.4 65.5l1.3 .4-1.3 .4M202.6 77.1h1.2M208.9 77.1h1.3M285 60.2h2M19.2 96.1h8.1M22.2 93.6h5.1M22.2 98.7h5.1M55.2 83.4h2.6M55.2 88.5h2.6M55.2 93.6h2.6M55.2 98.7h2.6"/>
<path d="M57.8 94.1l4 1.8M57.8 83.9l4 1.8M60.3 83.2v1.8M60.3 86.5v1M60.3 88.8v1M60.3 91.1v1M60.3 93.3v1.8M62.9 86h2.5M62.9 96.1h2.5M70.5 96.1v-1.2l-1.3 1.2 1.3 1.3v-1.3h1.3M70.5 84.7v-1.3l-1.3 1.3 1.3 1.3v-1.3h1.3M74.3 84.7h10.2"/>
<path d="M78.1 91.1h4.4l2 1.9M79.4 96.1h3.1M86.2 94.1l.4-.1v.2l-.4-.1h1.3M86.2 93.1l.4-.1v.2l-.4-.1h1.3M89.5 94.2v1.9h7.7M89.5 84.7h10.2M90.1 98.7h13.6l1.1 1.2-1.1 1.3h-13.6zM94.6 91.1h-5.1v3.8v-1.9M97.2 94.2v3.8M99.1 87.2h3.8M101 84.7v2.5M102.2 91.1h1.3"/>
<path d="M108.6 91.1h1.3M109.9 98.7h2.5l-.6 .6-.7-.6M123.7 99.9h17.1v2.6h-17.1l-1.1-1.3zM128.7 89.8h18.6v2.5h-18.6l-1.1-1.2zM202.6 84.7h1.2M208.9 84.7h1.3M211.5 91.1v8.2M214 88.5v9.5M216.5 91.1v8.8M217.6 80.9h15v2.5h-15l-1.1-1.2zM219.1 86h2.5M219.1 88.5v14.6"/>
<path d="M221.6 84.1v3.8M10 110.2h2M19.2 111.4h8.1M19.2 101.2h8.1M19.2 106.3h8.1M22.2 113.9h5.1M22.2 103.8h5.1M22.2 108.8h5.1M29.8 106.3h1.3v-1.3l1.3 1.3-1.3 1.3v-1.3M43.8 119h1.3v.2M44.4 119l.7 1.3h-1.3zM44.4 114.5v7h10.2v-7"/>
<path d="M46.4 119h1.2v.2M47 119l.6 1.3h-1.2zM47 114.5v7M48.9 119h1.3v.2M49.5 119l.7 1.3h-1.3zM49.5 114.5v10.2M51.4 119h1.3v.2M52.1 119l.6 1.3h-1.3zM52.1 114.5v7M54 119h1.2v.2M54.6 119l.6 1.3h-1.2zM59.1 103.8h2.7"/>
<path d="M60.1 102.5h1M60.6 102v1M61.8 101.5h.6v4.5h-.6zM63.9 103.8h2.8M71.8 113.9v-1.3l-1.3 1.3 1.3 1.3v-1.3h1.2M74.3 113.9h10.2M74.3 103.8h10.2M87 103.8v10.1M89.5 113.9h10.2M89.5 103.8h10.2M101 113.9h2.5M103.5 112v3.8"/>
<path d="M109.9 111.4h3.1M116.8 111.4h3.2M117.5 101.2h5.1M123.8 111.4h2.6l1.9 1.9M128.9 113.3v5.7M134 111.4h-2.6l-1.9 1.9M135.3 106.3l-.8 1.3M135.3 106.3v2.5M135.3 111.4v1.2M135.3 117.7v2.6M135.3 106.3l.7 1.3M196.2 107.7h2.6v5.1l-1.3 1.1-1.3-1.1z"/>
<path d="M196.9 108.7l1.3 .4-1.3 .4M205.1 102.5h2.5v2.5h-2.5zM211.5 108.2v8.3M212.1 103.8h-3.2v15.2M214 109.5v9.5M216.5 107.6v8.9M221.6 113.9v2.6M221.6 117.7v2.6M221.6 103.8h1.3v8.8M260.2 103.8h17.3v2.5h-17.3l-1.1-1.3zM260.8 119h21.5v2.5h-21.5l-1.1-1.2zM260.8 113.9h22.2v2.6h-22.2l-1.1-1.3z"/>
<path d="M260.8 108.8h17.3v2.6h-17.3l-1.1-1.3zM285 110.2h2M32.2 131.7h10.4v2.5h-10.4l-1.1-1.2zM50.8 124.7h1.3v-1.3l1.2 1.3-1.2 1.3v-1.3M61.6 121.5h8.9M66 134.9h2.8M67.1 133.6h1M67.6 133.1v1M68.8 132.6h.5v4.6h-.5zM70.9 134.9h2.8M71.8 126.6v-1.3l-1.3 1.3 1.3 1.3v-1.3h1.2M74.3 134.9h10.2"/>
<path d="M75.6 121.5h6.3v3.8v-1.9M81.9 124.7v1.9h-5.1M83.9 124.6h1.3l-.4 .1v-.2l.4 .1M83.9 123.6h1.3l-.4 .1v-.3l.4 .2M87 134.9v10.1M88.9 126.6h3.2M89.5 134.9h10.2M92.1 121.5h-3.2l-1.9 1.9M93.3 121.5h2.6M94.6 120.8l1.3 .7M95.9 121.5l-1.3 .8M97 130.4h21.3v2.6h-21.3l-1.1-1.3z"/>
<path d="M98.4 126.6h1.3M102.7 133.6h12.4v2.5h-12.4l-1.1-1.2zM104.8 126.6h3.8M108.6 124.7v3.8M111.1 120.3h7.6M135.3 125.3v1.3M138.9 127.2h12.9v2.6h-12.9l-1.1-1.3zM200 120.3h1.3M200 135.5h1.3M200 127.9h1.3M206.4 120.3h1.2M206.4 135.5h1.2"/>
<path d="M206.4 127.9h1.2M218.9 124.1h15v2.5h-15l-1.1-1.3zM219.7 120.3h3.8M245.1 132.3h1.3v.3M245.7 132.3l.7 1.3h-1.3zM245.7 127.9v7h10.2v-7M247.6 132.3h1.3v.3M248.3 132.3l.6 1.3h-1.3zM248.3 127.9v7M250.2 132.3h1.3v.3M250.8 132.3l.7 1.3h-1.3zM250.8 127.9v12.7"/>
<path d="M252.7 132.3h1.3v.3M253.4 132.3l.6 1.3h-1.3zM253.4 127.9v7M255.3 132.3h1.2v.3M255.9 132.3l.6 1.3h-1.2zM260.8 124.1h23.3v2.5h-23.3l-1.1-1.3zM50.2 146.3v9.5M52.7 148.8v8.9M55.2 146.3v14.6M56.5 142.5h1.3v-1.3l1.3 1.3-1.3 1.3v-1.3M66 157.7h2.8M67.1 156.5h1"/>
<path d="M67.6 156v1M68.8 155.4h.5v4.6h-.5zM69.2 146.3v1.3h1.3l-1.3 1.2-1.3-1.2h1.3M70.9 157.7h2.8M74.3 157.7h10.2M74.3 145h10.2M87 157.7v10.2M89.5 157.7h10.2M89.5 145h12.1M101.6 143.1v3.8M102.7 156.5h12.1v2.5h-12.1l-1.1-1.3zM248.9 140.6h3.8"/>
<path d="M10 160.2h2M41.3 160.3h2.5v2.5h-2.5zM50.2 167.3v9.5M52.7 165.3v8.9M57.8 171.7v3.8h1.3l-1.3 1.3-1.3-1.3h1.3M57.8 161.5h1.3v8.9M71.8 167.9v-1.3l-1.3 1.3 1.3 1.3v-1.3h1.2M74.3 167.9h10.2M77.5 176.8v-1.3l-1.3 1.3 1.3 1.2v-1.2h1.2M79.4 176.8h3.1M84.5 180l-2 1.9h-3.1M86.2 178.8l.4 .1v-.2l-.4 .1h1.3"/>
<path d="M86.2 179.8l.4 .2v-.3l-.4 .1h1.3M89.5 180v-2v3.9h6.4M89.5 167.9h10.2M97.2 176.8h-7.7v1.9M97.2 174.9v3.8M100.3 167.9h2.6M102.9 166v3.8M177 166.3h108v32h-108zM219.7 177l-.4-.1-.3 .3v.4l.1 .3h.6M220.4 176.4v.2M220.4 176.9v1M221.1 176.9v1"/>
<path d="M221.5 176.9l-.3 .1-.1 .2M222.6 177l-.4-.1-.3 .3v.4l.2 .3h.5M223.3 176.9l.1 1h.3l.2-.1M223.9 176.9v1M224.6 176.4v.2M224.6 176.9v1M225.1 176.9h.6M225.4 176.4v1.3l.3 .2M226.7 177l-.3-.1-.3 .2 .1 .3 .5 .1v.4h-.6M285 160.2h2M60 198.3v2M63.5 189.5h8.3"/>
<path d="M76.8 181.9h1.3M76.8 189.5h1.3M77.5 194.6v-1.3l-1.3 1.3 1.3 1.2v-1.2h1.2M79.4 189.5h5.1v3.8v-1.9M84.5 192.7v1.9h-5.1M86.5 192.5h1.3l-.4 .2v-.3l.4 .1M86.5 191.5h1.3l-.4 .1v-.2l.4 .1M91.4 194.6h3.2M94.6 189.5h-3.2l-1.9 1.9M97.6 193.3h19.3v2.5h-19.3l-1.1-1.2zM97.6 188.2h5.2v2.5h-5.2l-1.1-1.2zM100.9 188.9l.5 1.2 .4-1.2"/>
<path d="M101 181.9h1.2M105.3 180.6h24.9v2.5h-24.9l-1.2-1.2zM110 198.3v2M160 198.3v2M177 194.8h108M177 191.8h108M177 187.8h108M177 181.8h108M186.5 192.5l-.4 1h1M186.9 193v1M197 191.8v3M197.1 183.1l.2-.2 .4 .2 .1 .5-.2 .3h-.3l-.2-.1z"/>
<path d="M198.4 182.9v1M198.9 182.9l-.3 .1-.2 .2M199.9 183l-.4-.1-.2 .2 .1 .3 .5 .1v.4h-.6M201.6 182.4l-1.2 1.9M209.6 185.7l-.4-.1-.3 .3v.4l.2 .3h.5M209.9 195.9l-.5-.1-.3 .3v.4l.2 .3h.6M209.9 195.3v1.5M210 198.3v2M210.3 185.7h.6v.9M210.4 195.8h.5M210.9 195.3l-.3 .2v1.3M210.9 186l-.5 .1a.29 .29 0 0 0-.2 .2 .29 .29 0 0 0 .2 .3h.5"/>
<path d="M211.9 195.9l-.3-.1-.2 .2v.3l.5 .1v.4h-.5M212.3 185.7l-.4-.1-.3 .3v.4l.1 .3h.6M212.3 185.1v1.5M212.6 186.8h1.2M213.3 195.8v1.2l-.3 .3h-.4M213.3 195.9l-.4-.1-.3 .3v.4l.1 .3h.6M214 196.3h1.1M214.6 185.7l-.3-.1-.2 .2v.3l.5 .1v.4h-.5M215.8 195.8l.4-.5v1.5M215.8 196.8h.8M216 185.7l-.4-.1-.3 .3v.4l.1 .3h.6M216.6 185.8l.3-.2 .3 .1 .1 .9"/>
<path d="M216.6 185.1v1.5M217 192.5h-.7l-.1 .7 .2-.1 .5 .1 .2 .2-.1 .5-.2 .1-.6-.1M217.7 193.5h1.2M219.7 192.6l.2-.1a.81 .81 0 0 1 .5 .7 .81 .81 0 0 1-.3 .8h-.1a.81 .81 0 0 1-.6-.6 .81 .81 0 0 1 .3-.8zM220.9 192.5h1l-.7 1.5M260 198.3v2M261 191.8v6.5M269.9 195.3l-1.3 1.9M270.2 195.3h1l-.6 1.5"/>
<circle cx="238.3" cy="18" r=".51"/>
<circle cx="267.5" cy="19.3" r=".76"/>
<circle cx="17.1" cy="33.9" r=".76"/>
<circle cx="17.1" cy="39" r=".76"/>
<circle cx="20.2" cy="36.4" r=".76"/>
<circle cx="20.2" cy="31.4" r=".76"/>
<circle cx="234.2" cy="30.7" r=".51"/>
<circle cx="234.2" cy="20.6" r=".51"/>
<circle cx="238.3" cy="23.1" r=".51"/>
<circle cx="238.3" cy="33.3" r=".51"/>
<circle cx="238.3" cy="28.2" r=".51"/>
<circle cx="267.5" cy="24.4" r=".76"/>
<circle cx="267.5" cy="34.5" r=".76"/>
<circle cx="267.5" cy="29.5" r=".76"/>
<circle cx="267.5" cy="39.6" r=".76"/>
<circle cx="270.5" cy="26.9" r=".76"/>
<circle cx="270.5" cy="21.8" r=".76"/>
<circle cx="270.5" cy="37.1" r=".76"/>
<circle cx="270.5" cy="32" r=".76"/>
<circle cx="17.1" cy="44.1" r=".76"/>
<circle cx="17.1" cy="49.1" r=".76"/>
<circle cx="20.2" cy="51.7" r=".76"/>
<circle cx="20.2" cy="41.5" r=".76"/>
<circle cx="20.2" cy="46.6" r=".76"/>
<circle cx="40.6" cy="59.9" r=".13"/>
<circle cx="43.2" cy="59.9" r=".13"/>
<circle cx="45.7" cy="59.9" r=".13"/>
<circle cx="253.4" cy="47.9" r=".13"/>
<circle cx="255.9" cy="47.9" r=".13"/>
<circle cx="258.4" cy="47.9" r=".13"/>
<circle cx="18.4" cy="96.1" r=".76"/>
<circle cx="21.5" cy="93.6" r=".76"/>
<circle cx="21.5" cy="98.7" r=".76"/>
<circle cx="58.3" cy="98.7" r=".51"/>
<circle cx="58.3" cy="83.4" r=".51"/>
<circle cx="58.3" cy="88.5" r=".51"/>
<circle cx="58.3" cy="93.6" r=".51"/>
<circle cx="62.4" cy="96.1" r=".51"/>
<circle cx="62.4" cy="86" r=".51"/>
<circle cx="18.4" cy="101.2" r=".76"/>
<circle cx="18.4" cy="111.4" r=".76"/>
<circle cx="18.4" cy="106.3" r=".76"/>
<circle cx="21.5" cy="113.9" r=".76"/>
<circle cx="21.5" cy="108.8" r=".76"/>
<circle cx="21.5" cy="103.8" r=".76"/>
<circle cx="47" cy="121.5" r=".13"/>
<circle cx="49.5" cy="121.5" r=".13"/>
<circle cx="52.1" cy="121.5" r=".13"/>
<circle cx="248.3" cy="134.9" r=".13"/>
<circle cx="250.8" cy="134.9" r=".13"/>
<circle cx="253.4" cy="134.9" r=".13"/>
</g>
<g fill="none" stroke="#840000" stroke-width=".4">
<path d="M267.5 189.2l.2-.1 .5 .1v1.3M268.3 189.6l-.7 .1a.4 .4 0 0 0-.3 .3 .4 .4 0 0 0 .2 .5l.7-.1M269.3 189.3a.49 .49 0 0 1 .8 .1l-.1 1.1M269.3 189.1l-.2 1.4M272 189.2a.66 .66 0 0 0-1 .3l-.1 .6 .1 .3 .2 .1 .6-.1M272 188.5l-.2 2M274.4 189.2l.2-.1 .6 .1-.1 1.3M275.2 189.6l-.6 .1a.4 .4 0 0 0-.4 .3 .4 .4 0 0 0 .3 .5l.6-.1M276.2 189.3a.49 .49 0 0 1 .9 .1l-.2 1.1M276.3 189.1l-.2 1.4M278 189.2l.2-.1 .6 .1-.1 1.3M278.9 189.6l-.7 .1a.4 .4 0 0 0-.4 .3 .4 .4 0 0 0 .3 .5l.7-.1"/>
<path d="M280 188.5l-.3 1.7 .3 .3M280.9 189.3a.52 .52 0 0 1 .5-.2 .52 .52 0 0 1 .4 .4l-.1 .6a.55 .55 0 0 1-.5 .4 .55 .55 0 0 1-.5-.4zM283.6 189.2a.66 .66 0 0 0-1 .3l-.1 .6 .2 .3 .1 .1 .6-.1M283.6 189.1l-.2 1.6a.6 .6 0 0 1-.9 .3"/>
</g>
<path d="M212.8 179.4v1.5M213.4 179.9l-.6 .6M214.1 179.4v.2M214.1 179.9v1M210.2 180.4l.7-.1-.1-.3-.4-.1-.2 .2 .1 .8h.5M212.2 180l-.4-.1-.3 .3v.4l.1 .3h.6M213 180.4l.4 .5" fill="none" stroke="#840000" stroke-width=".3"/>
<g fill="#ffffc2" stroke="#ffffc2" stroke-width=".18">
<path d="M243.2 130.4h15.2v5.1h-15.2z"/>
<path d="M14.6 32l7.6-3.8v26.7l-7.6-3.9z"/>
<path d="M35.6 55.5h15.2v5.1h-15.2z"/>
<path d="M215.9 43.4h10.2v7.6h-10.2z"/>
<path d="M71.8 47.9h10.1v7.6h-10.1z"/>
<path d="M81.9 89.8h10.2v7.6h-10.2z"/>
<path d="M265.4 16.1l7.6 3.8v19.1l-7.6 3.8z"/>
<path d="M248.3 43.4h15.2v5.1h-15.2z"/>
<path d="M109.9 96.1h10.1v20.4h-10.1z"/>
<path d="M41.9 117.1h15.2v5.1h-15.2z"/>
<path d="M79.4 120.3h10.1v7.6h-10.1z"/>
<path d="M107.3 28.8h10.2v20.3h-10.2z"/>
<path d="M81.9 188.2h10.2v7.6h-10.2z"/>
<path d="M81.9 175.5h10.2v7.6h-10.2z"/>
<path d="M71.8 60.6h10.1v7.6h-10.1z"/>
<path d="M15.9 94.2l7.6-3.8v26.7l-7.6-3.8z"/>
</g>
<g fill="none" stroke="#840000" stroke-width=".25">
<path d="M265.4 16.1l7.6 3.8v19.1l-7.6 3.8zM14.6 32l7.6-3.8v26.7l-7.6-3.9zM107.3 28.8h10.2v20.3h-10.2zM110.5 30.7h3.8v6.4h-3.8zM111.1 21.2l2.6 1.3-2.6 1.2zM112.4 37.1v.6M112.4 38.3v.7M112.4 39.6v.7M113.7 21.2v2.5M114.3 31.4l-3.8 5M130.4 31.4h2.1v5h-2.1zM138 23.7h2.1v5.1h-2.1z"/>
<path d="M138 31.4h2.1v5h-2.1zM229.5 35.2h2v5.1h-2zM35.6 55.5h15.2v5.1h-15.2zM59.1 48.1h5v2.1h-5zM71.8 47.9h10.1v7.6h-10.1zM73.7 51h1.2l-.6 1.3zM73.7 52.3h1.2M95.9 53.2h5.1v2h-5.1zM112.4 40.9v.6M112.4 42.2v.6M205.7 43.7h5.1v2h-5.1zM215.9 43.4h10.2v7.6h-10.2z"/>
<path d="M217.8 46.6h1.3l-.7 1.3zM217.8 47.9h1.3M248.3 43.4h15.2v5.1h-15.2zM55.2 65.9h5.1v2h-5.1zM55.2 60.8h5.1v2.1h-5.1zM55.2 70.4h5.1v2h-5.1zM71.8 60.6h10.1v7.6h-10.1zM73.7 63.7h1.2l-.6 1.3zM73.7 65h1.2M95.9 65.9h5.1v2h-5.1zM203.8 76.1h5.1v2h-5.1zM15.9 94.2l7.6-3.8v26.7l-7.6-3.8z"/>
<path d="M73 90h5.1v2.1h-5.1zM81.9 89.8h10.2v7.6h-10.2zM88.9 93h1.3l-.7 1.2zM88.9 94.2h1.3M103.5 90h5.1v2.1h-5.1zM109.9 96.1h10.1v20.4h-10.1zM203.8 83.7h5.1v2h-5.1zM210.8 99.9a.63 .63 0 0 1 .7-.6 .63 .63 0 0 1 .6 .6M213.4 98.7a.63 .63 0 0 1 .6-.7 .63 .63 0 0 1 .6 .7M41.9 117.1h15.2v5.1h-15.2zM113 108.2h3.8v6.3h-3.8zM113 108.8l3.8 5.1"/>
<path d="M113.7 119l2.5 1.3-2.5 1.2zM114.9 102.5v.6M114.9 103.8v.6M114.9 105v.7M114.9 106.3v.6M114.9 107.6v.6M116.2 119v2.5M134.2 112.6h2.1v5.1h-2.1zM201.3 119.2h5.1v2.1h-5.1zM210.8 107.6a.63 .63 0 0 0 .7 .6 .63 .63 0 0 0 .6-.6M213.4 108.8a.63 .63 0 0 0 .6 .7 .63 .63 0 0 0 .6-.7M215.9 106.9a.63 .63 0 0 0 .6 .7 .63 .63 0 0 0 .7-.7"/>
<path d="M215.9 100.6a.63 .63 0 0 1 .6-.7 .63 .63 0 0 1 .7 .7M218.4 103.8a.63 .63 0 0 1 .7-.7 .63 .63 0 0 1 .6 .7M64.1 120.3l2.6 1.2-2.6 1.3zM66.7 120.3v2.5M70.5 120.5h5.1v2h-5.1zM79.4 120.3h10.1v7.6h-10.1zM81.3 123.4h1.2l-.6 1.3zM81.3 124.7h1.2M99.7 125.6h5.1v2h-5.1zM134.2 120.3h2.1v5h-2.1zM201.3 134.5h5.1v2h-5.1zM201.3 126.9h5.1v2h-5.1z"/>
<path d="M243.2 130.4h15.2v5.1h-15.2zM49.5 156.5a.63 .63 0 0 1 .7-.7 .63 .63 0 0 1 .6 .7M52.1 158.4a.63 .63 0 0 1 .6-.7 .63 .63 0 0 1 .6 .7M49.5 166.6a.63 .63 0 0 0 .7 .7 .63 .63 0 0 0 .6-.7M52.1 164.7a.63 .63 0 0 0 .6 .6 .63 .63 0 0 0 .6-.6M54.6 161.5a.63 .63 0 0 1 .6-.6 .63 .63 0 0 1 .7 .6M81.9 175.5h10.2v7.6h-10.2zM88.9 178.7h1.3M89.5 178.7l.7 1.3h-1.3zM66 188.2l2.6 1.3-2.6 1.2zM68.6 188.2v2.5M71.8 180.8h5v2.1h-5z"/>
<path d="M71.8 188.5h5v2h-5zM81.9 188.2h10.2v7.6h-10.2zM83.8 191.4h1.3l-.6 1.3zM83.8 192.7h1.3M95.9 180.8h5.1v2.1h-5.1z"/>
<circle cx="131.4" cy="23.7" r="2.82"/>
<circle cx="128.9" cy="112.6" r="2.82"/>
</g>
<g fill="none" stroke="#008484" stroke-width=".18">
<path d="M233.5 17h-.4l-.2 .2 .1 .6h.5M233.5 16.6v1.2M60.9 38l-.4-.1-.2 .3 .1 .5h.5M60.9 37.5v1.3M73 31.9h.8M101.7 27.6h.6l.1-.2v-.3l-.7-.1v1.2M102 27.6l.4 .6M103 28.2v-1.2l.4 .9 .4-.9v1.2M121.3 27.1l.2-.1a.68 .68 0 0 1 .4 .6 .68 .68 0 0 1-.4 .6l-.2-.1-.1-.3zM123.1 27h-.6l-.1 .6 .2-.2 .4 .1 .1 .2v.4l-.2 .1-.5-.1M207 21.1h.7M72.2 46.1l-.4-.1-.2 .1v.4l.5 .2 .1 .3-.2 .3-.5-.1"/>
<path d="M72.2 58.8l-.4-.1-.2 .1v.4l.5 .2 .1 .3-.2 .3-.5-.1M81.4 46.4l.4-.4v1.3M81.4 59.1l.4-.4v1.3M81.4 47.3h.8M81.4 60h.8M216.4 41.6h-.5l-.2 .1v.4l.6 .2 .1 .3-.3 .2h-.4M225.6 41.9l.3-.3v1.2M225.6 42.8h.7M264.7 47.6h.4M265.3 47h-.6v1.2h.6M278.7 47h-.4a.86 .86 0 0 0 0 1.2l.5-.1v-.4l-.2-.2h-.3l-.2 .2M27.1 61.8h.4"/>
<path d="M27.7 61.1h-.6v1.3h.6M41.1 61.1l-.4 .1a.86 .86 0 0 0 0 1.2l.4-.1 .1-.4-.2-.3-.4 .1-.1 .2M74.9 71l-.4-.1-.2 .3 .1 .5h.5M74.9 70.5v1.3M83.2 75.1h.7M82.4 88l-.5-.1-.2 .1v.4l.6 .3 .1 .3-.2 .2-.5-.1M91.6 88.3l.4-.4v1.3M91.6 89.2h.7M68.1 107.4l-.3-.1-.3 .2 .1 .6h.5M68.1 106.9v1.2M79.9 118.5l-.5-.1-.2 .1v.4l.5 .2 .2 .3-.3 .3-.5-.1M83.2 104.3h.7"/>
<path d="M89.1 118.8l.3-.4v1.3M89.1 119.7h.7M33.4 123.3h.4M34 122.7h-.6v1.3h.6M47.4 122.7l-.3 .1a.86 .86 0 0 0 0 1.2l.4-.1 .1-.4-.3-.3-.4 .1-.1 .2M83.2 135.4h.7M259.6 134.6h.4M260.2 134h-.6v1.2h.6M273.6 134h-.3a.86 .86 0 0 0 0 1.2l.4-.1v-.4l-.2-.2h-.2l-.3 .2M83.2 158.3h.7M82.4 173.7l-.5-.1-.2 .2v.3l.6 .3 .1 .3-.2 .2h-.5M91.6 174l.4-.4v1.3"/>
<path d="M91.6 174.9h.7M82.4 186.4l-.5-.1-.2 .2v.3l.6 .3 .1 .3-.2 .2h-.5M91.6 186.7l.4-.4v1.3M91.6 187.6h.7"/>
</g>
<g fill="#840000" stroke="#840000" stroke-width=".18">
<path d="M57.1 160.3h1.3v2.5h-1.3z"/>
<path d="M41.3 160.3h2.5v2.5h-2.5z"/>
<path d="M70.4 155.4h.5v4.6h-.5z"/>
<path d="M223.5 47.9l1.9 1.9z"/>
<path d="M224 48.9l.5-.5 .5 1z"/>
<path d="M79.4 52.3l1.9 1.9z"/>
<path d="M79.9 53.3l.5-.5 .5 1z"/>
<path d="M69.2 31.4h5.1v10.1h-5.1z"/>
<path d="M79.4 31.4h5.1v10.1h-5.1z"/>
<path d="M57 39.2h.5v4.6h-.5z"/>
<path d="M84.5 94.2l-2 1.9z"/>
<path d="M83.4 94.7l.5 .5-1 .6z"/>
<path d="M79.4 74.5h5.1v10.2h-5.1z"/>
<path d="M89.5 74.5h5.1v10.2h-5.1z"/>
<path d="M203.2 20.6h5.1v10.1h-5.1z"/>
<path d="M213.4 20.6h5v10.1h-5z"/>
<path d="M226.3 18.3h.5v4.6h-.5z"/>
<path d="M130.7 111.6l.5 .5-1 .5z"/>
<path d="M109.9 103.8h1.2l.7-.7 .6 .7z"/>
<path d="M117.9 61.7h.8v.3h-.8z"/>
<path d="M117.9 64.3h.8v.2h-.8z"/>
<path d="M117.9 66.8h.8v.3h-.8z"/>
<path d="M133.2 22.7l.5 .5-1 .5z"/>
<path d="M63.4 101.5h.5v4.5h-.5z"/>
<path d="M79.4 134.9h5.1v10.1h-5.1z"/>
<path d="M89.5 134.9h5.1v10.1h-5.1z"/>
<path d="M87 124.7l1.9 1.9z"/>
<path d="M87.5 125.7l.5-.5 .5 1z"/>
<path d="M221 102.5h1.2v2.5h-1.2z"/>
<path d="M205.1 102.5h2.5v2.5h-2.5z"/>
<path d="M107.3 41.5h2.6l-.7 .7-.6-.7z"/>
<path d="M79.4 103.8h5.1v10.1h-5.1z"/>
<path d="M89.5 103.8h5.1v10.1h-5.1z"/>
<path d="M89.5 192.7l1.9 1.9z"/>
<path d="M90 193.7l.6-.5 .5 1z"/>
<path d="M79.4 157.7h5.1v10.2h-5.1z"/>
<path d="M89.5 157.7h5.1v10.2h-5.1z"/>
<path d="M82.5 176.8l2 1.9z"/>
<path d="M82.9 177.2l1 .5-.5 .5z"/>
<path d="M70.4 132.6h.5v4.6h-.5z"/>
<path d="M71 72.3h.5v4.5h-.5z"/>
<path d="M79.4 65l1.9 1.9z"/>
<path d="M79.9 66l.5-.5 .5 1z"/>
</g>
<path d="M203.8 93.6h20.4v20.3h-20.4zM40 151.4h20.3v20.3h-20.3z" fill="none" stroke="#840000" stroke-width=".41"/>
<g fill="none" stroke="#840000" stroke-width=".81">
<circle cx="214" cy="103.8" r="7.6"/>
<circle cx="50.2" cy="161.5" r="7.6"/>
</g>
<path d="M129.5 24.4h3.8M79.4 49.8v3.8M108.6 42.2l6.3 1.9M223.5 45.3v3.8M79.4 62.5v3.8M84.5 91.7v3.8M117.5 101.2l-6.4 1.9M127 113.3h3.8M87 122.2v3.8M84.5 177.4v3.8M89.5 190.1v3.8" fill="none" stroke="#840000" stroke-width=".51"/>
<g fill="none" stroke="#0000c2" stroke-width=".18">
<path d="M157.3 133.9h.3l.3 .2v.4l-.3 .2-.3-.1-.1-.1zM158.9 133.9h-.3l-.2 .1v.2l.5 .1v.3h-.5M160.4 134l.2-.1h.3l.1 .8M160.4 133.4v1.3M161.6 133.9h.5v.8M162.1 134.2h-.4l-.2 .2 .2 .3 .4-.1M162.6 133.9l.3 .8 .3-.8M163.6 134.3l.6-.1v-.3h-.4l-.2 .1 .1 .6h.5M164.6 140l.2 .8 .3-.6 .2 .6 .3-.8M164.8 134.6v.1M165.1 131.8v1l-.3 .3-.3-.1M165.1 131.9l-.4-.1-.2 .3 .1 .5h.5"/>
<path d="M165.7 131.8l.1 .8 .3 .1 .1-.2M166.2 131.8v.9M166.8 131.8v.9M167.2 131.8l-.4 .3M167.6 132.2l.6-.1-.1-.2-.4-.1-.1 .2v.6h.5M167.8 138l-.4-.1-.2 .3 .1 .5h.5M168.2 140v.8M168.3 138.4l.6-.2-.1-.2-.3-.1-.2 .2 .1 .6h.4M168.5 140l-.3 .2M169.6 131.8l.2 .9 .2-.6 .3 .6 .2-.9M170.4 138.2l.6-.1 .1-.2v-.3l-.7-.1v1.3M170.6 139.6v1.2"/>
<path d="M170.7 138.2l.4 .6M171 131.9l.2-.1 .3 .1 .1 .8M171 131.4v1.3M171.3 139.6v.1M171.3 140v.8M172.2 131.9h.4l.1 .8M172.2 137.5l-.3 .1a.86 .86 0 0 0 0 1.2l.4-.1v-.5l-.2-.2h-.2l-.3 .2M172.7 132.1l-.4 .1-.2 .2 .2 .3 .4-.1M172.8 137.6l.5-.1 .3 .4-.8 .9h.8M173.1 131.8h.5M173.3 131.4v1.1l.3 .2M174.3 137.5l-.3 .9h.8"/>
<path d="M174.6 137.9v.9M148 151.8h.8l-.5 .5 .4 .1v.6l-.2 .1-.5-.1M149.4 152l.1-.2a.68 .68 0 0 1 .5 .7 .68 .68 0 0 1-.5 .6l-.1-.1-.2-.4zM150.6 152l.2-.2a.68 .68 0 0 1 .4 .7 .68 .68 0 0 1-.4 .6l-.2-.1-.1-.4zM151.6 151.7a1.46 1.46 0 0 1 0 1.9M154 150.6l.6-.1v-.2l-.4-.1-.2 .2 .1 .6h.5M155.2 150.2v.9M155.5 150.2l-.3 .3M156.9 150.3h.5l.1 .8M157.5 150.5l-.5 .1-.1 .2 .1 .3 .5-.1M158.1 150.3l.2-.1 .3 .1v.8M158.1 150.2v.9"/>
<path d="M158.6 148.2l.1 .8h.3l.2-.1M158.6 150.4l.2-.2 .3 .1 .1 .8M159.2 148.2v.8M159.8 150.3l.3-.1 .3 .3-.2 .5h-.4M159.8 150.2v1.3M160.3 148.2h-.4l-.2 .2 .1 .6h.5M160.3 147.7v1.3M160.5 158.5l.2-.1h.3l.1 .8M160.8 142.1l.4-.1 .2 .3-.1 .5h-.5M160.8 142v1.3M160.9 148.2v.8M161.6 148.2h.3l.2 .2v.4l-.2 .2h-.3l-.1-.2z"/>
<path d="M161.7 158.4h.5v.8M161.9 141.6v1.1l.2 .2M162.2 156.4l-.4-.1-.2 .3 .1 .5h.5M162.2 155.9v1.3M162.2 158.7l-.4 .1-.2 .1 .2 .3h.4M162.5 142.5l.7-.2-.1-.2-.4-.1-.2 .2 .1 .6h.5M162.8 155.9v.1M162.8 156.3v.9M162.8 146.2l.2-.1 .3 .1 .1 .8M162.8 158.5l.2-.1h.3l.1 .8M162.8 145.7v1.3M162.8 158.4v.8"/>
<path d="M163.4 156.3v.9M163.6 142l.6 .9M163.7 148.2h.3l.2 .2v.4l-.2 .2h-.3l-.1-.2zM163.8 156.3l-.4 .3M164.1 156.8l.6-.2v-.2l-.4-.1-.2 .2 .1 .6h.5M164.2 142l-.6 .9M164.5 158.4h-.3l-.3 .2 .2 .6h.4M164.5 158v1.2M164.8 144.1h-.3l-.2 .2 .1 .1 .4 .2v.3h-.5M164.8 148.2v.8h.3l.2-.1M165 146.2l.3-.1 .3 .3v.3l-.3 .3-.3-.1-.1-.2zM165.1 158.5l.2-.1h.3l.1 .8"/>
<path d="M165.1 158v1.2M165.3 144.5l.6-.1v-.3h-.4l-.2 .2 .1 .6h.5M165.3 148.2v.8M165.7 142.1l.4-.1 .2 .3-.1 .5h-.5M165.7 142v1.3M165.8 148.2h.4M165.8 156.4l-.4-.1-.2 .3 .1 .5h.5M165.9 147.7v1.1l.3 .2M166.1 140h.3l.3 .2v.4l-.3 .2h-.3l-.1-.2zM166.1 146.1l.1 .8 .3 .1 .2-.2M166.2 156.3h.5M166.2 158.8l.6-.1v-.3h-.4l-.2 .2 .1 .6h.5"/>
<path d="M166.4 155.9v1.1l.3 .2M166.5 144.1h.3l.3 .2-.1 .6h-.5M166.5 144.1v1.2M166.7 146.1v.9M166.9 142.1l.3-.1 .2 .3v.3l-.2 .3-.3-.1-.1-.2zM167.1 155.9v.1M167.1 146.1h.5M167.1 156.3v.9M167.3 145.7v1.1l.3 .2M167.4 158v1.1l.2 .1M167.6 144.1h.5l.1 .8M167.7 156.4l.3-.1 .3 .3v.3l-.3 .3-.3-.1-.1-.2z"/>
<path d="M168 146.2l.4-.1 .2 .3-.1 .5h-.5M168 142v.9M168 146.1v1.3M168.2 144.4h-.5l-.1 .2 .1 .3h.5M168.4 142l-.4 .3M168.6 158.4h-.4l-.2 .2 .1 .6h.5M168.6 142h.5M168.6 158v1.2M168.8 141.6v1.1l.3 .2M168.8 144.1v.8M168.8 156.5l.2-.2 .3 .1 .1 .8M168.8 156.3v.9"/>
<path d="M169 140h.4l.1 .8M169.1 144.1l-.3 .2M169.1 146.1l.1 .8 .3 .1 .2-.2M169.5 140.3l-.4 .1-.2 .1 .2 .3h.4M169.5 142.8v.1M169.6 144.1h.4l.1 .8M169.7 146.1v.9M170.1 144.4h-.4l-.2 .2 .2 .3h.4M170.1 146.1h.5M170.3 145.7v1.1l.3 .2M170.5 144.1h.5M170.6 140h-.3l-.3 .2 .2 .6h.4"/>
<path d="M170.7 143.7v1l.3 .2M171.4 144.5l.6-.1-.1-.3h-.3l-.2 .2v.6h.5M171.9 140h.3l.3 .2v.4l-.3 .2h-.3l-.1-.2zM173.4 140h-.3l-.2 .2 .1 .2 .4 .1v.3h-.5M135.5 177.2l.6-.1-.1-.2-.4-.1-.1 .2v.6h.5M136.6 177.5v.1M136.6 176.4v.8M159 168.6v.8l.3 .1 .2-.2M159.5 168.6v.9M159.9 172.9l.2-.2 .3 .1v.7M160.5 168.7l-.3-.1-.1 .2v.2l.4 .1v.3h-.4M161 168.6h.5"/>
<path d="M161 172.7l.1 .8h.3l.2-.1M161.2 168.2v1.1l.3 .2M161.6 172.7v.8M162.6 172.8l-.3-.1-.2 .2 .1 .2 .4 .1v.3h-.5M162.8 168.7l.4-.1 .3 .3-.2 .5h-.5M162.8 168.2v1.3M163 172.7h.5M163.2 172.3v1.1l.3 .1M163.9 164.9l.6-.1-.1-.2-.3-.1-.2 .2v.6h.5M163.9 169l.6-.1v-.2l-.4-.1-.2 .2 .1 .6h.5M164 160.2l.2-.2a.43 .43 0 0 1 .6 .4v.5a.42 .42 0 0 1-.4 .4 .42 .42 0 0 1-.5-.4zM164.7 170.2v.2"/>
<path d="M164.7 170.7v.8M164.9 172.8l.4-.1 .2 .2-.1 .6h-.5M164.9 172.3v1.2M165 164.9l.6-.1-.1-.2-.4-.1-.1 .2v.6h.5M165.1 160h.8M165.3 166.1a.64 .64 0 0 1 .8 .7 .64 .64 0 0 1-.8 .6zM165.3 170.8l.2-.1h.3l.1 .8M165.3 170.7v.8M165.5 160v1.3M165.8 174.7h.5M165.9 162.5h.5v.8M166 173.1l.6-.1-.1-.2-.3-.1-.2 .2 .1 .6h.4"/>
<path d="M166 174.3v1.1l.3 .2M166.1 164.6l.2-.1 .3 .1 .1 .8M166.1 168.7l.3-.1 .3 .3v.3l-.3 .3-.3-.1-.1-.2zM166.1 164.5v.9M166.4 162.8h-.4l-.2 .2 .2 .3h.4M166.8 174.8l.3-.1 .2 .3v.4l-.2 .2-.3-.1-.1-.1zM167.2 168.7l.2-.1 .3 .1v.8M167.2 168.6v.9M167.3 160.5l.3-.1 .3 .3-.2 .5h-.4M167.3 160.4v1.3M167.3 166.3a.6 .6 0 0 0-.8 .4 .6 .6 0 0 0 .6 .7l.2-.1M167.4 162.5h-.3l-.1 .2v.1l.4 .2v.3h-.4"/>
<path d="M167.4 170.7v.8M167.8 170.7l-.4 .2M167.9 174.7v.9M168.2 171.1l.6-.1-.1-.3h-.3l-.2 .1v.6h.5M168.2 172.8l.3-.1 .2 .2v.4l-.2 .2h-.3l-.2-.2zM168.2 164.6l.4-.1 .2 .3-.1 .5h-.5M168.2 174.7l-.3 .3M168.2 164.5v1.3M168.4 160v1.1l.2 .2M168.9 166.6h.3l.2 .2v.4l-.2 .2h-.3l-.1-.2zM169 162.7h.6l.1-.2v-.3l-.7-.1v1.2M169.1 160.5h.5v.8"/>
<path d="M169.3 172.8l.1-.1 .3 .1 .1 .7M169.3 172.7v.8M169.3 170.2v1.1l.2 .2M169.3 162.7l.4 .6M169.4 164.1v.1M169.4 164.5v.9M169.6 160.7l-.4 .1-.2 .2 .2 .3 .4-.1M169.6 174.9l.2-.2 .3 .1 .1 .8M169.6 174.7v.9M169.8 166.6h.5M170 164.6l.2-.1 .3 .1v.8M170 170.7h.5v.8"/>
<path d="M170 164.5v.9M170.2 174.9l.1-.2 .3 .1 .1 .8M170.3 166.1l-.3 .2v1.1M170.5 171h-.4l-.2 .2 .2 .3 .4-.1M170.5 166.6h.5M170.8 160.5l-.4-.1-.2 .3 .1 .5h.5M170.8 162.1h-.3a.86 .86 0 0 0 0 1.2l.4-.1 .1-.4-.3-.3h-.2l-.3 .3M171 170.7h.4M171 164.1h.9l-.6 1.3M171 166.1l-.3 .2v1.1M171.1 170.2v1.1l.3 .2M171.3 160.9l.6-.2-.1-.2-.4-.1-.1 .2v.6h.5"/>
<path d="M171.3 174.3v.1M171.3 174.7v.9M171.4 162.2l.5-.1 .3 .3-.8 .9h.8M171.9 166.6h-.3l-.2 .1v.2l.5 .2v.3h-.5M171.9 170.2v.2M171.9 170.7v.8M172.4 167l.6-.1-.1-.3h-.3l-.2 .1 .1 .7h.4M172.5 174.7v1.1l-.3 .2h-.3M172.5 174.8l-.4-.1-.2 .3 .1 .5h.5M172.5 170.7h.3l.3 .2v.4l-.3 .2-.3-.1-.1-.1zM173.1 174.9l.1-.2 .4 .1v.8M173.1 174.3v1.3"/>
<path d="M173.3 162.1h-.6l-.1 .6 .2-.2 .4 .1 .2 .2-.1 .4-.2 .1-.5-.1M173.4 166.6h.5M173.6 166.1v1.1l.3 .2M173.6 170.8l.2-.1h.3l.1 .8M173.6 170.7v.8M173.9 163.2v.1M174 174.7h.5M174.2 174.3v1.1l.3 .2"/>
</g>
<g fill="none" stroke="#008400" stroke-width=".18">
<path d="M139.1 19.9v2.6h-2.6M241.3 18h3.8v6.4h15.9v16.5M56.5 31.4h7.6M89.5 31.4h1.3M108.6 22.5h-19.1v11.4h15.3M116.2 22.5h10.2M123.8 22.5v11.4h-3.8M131.4 30.1h7.7M131.4 37.7v3.2h22.9M139.1 37.7h15.2M194.3 20.6h3.8M195.6 30.7h2.5"/>
<path d="M231.1 30.7h-.6v3.2M241.3 28.2h1.3v8.9h19M241.3 23.1h2.5v16.5h17.8M241.3 33.3v1.2h20.3M253.4 39.6v1.3M255.9 37.1v3.8M258.4 34.5v6.4M258.4 26.9h3.2M26 51.7h26.1v10.1h1.9M26 44.1h3.8M26 41.5h26.7M26 49.1h31.8"/>
<path d="M43.2 41.5v11.5M45.7 49.1v3.9M48.3 51.7v1.3M60.3 41.5h3.8M65.4 49.1h3.8M66.7 54.2h2.5M84.5 54.2h10.1M84.5 49.1h1.2M88.3 54.2v3.8h25.4v3.8M89.5 41.5h15.3M97.2 41.5v2.6h-1.3M102.2 54.2h1.3"/>
<path d="M103.5 46.6h1.3M120 44.1h1.3M121.9 54.9h-9.5v9.5h1.3M203.2 44.7h1.3M212.1 44.7h1.3M213.4 49.8h-1.3v5.1M228.6 49.8h1.3M230.5 41.5v3.2h-1.9M255.9 51v.7M43.2 63.1v.6M51.4 71.4h2.6M51.4 66.9h2.6"/>
<path d="M61.6 66.9h7.6M61.6 61.8h7.6M63.5 66.9v4.5h-1.9M66.7 74.5v11.5h-1.3M84.5 66.9h10.1M84.5 61.8h1.2M88.3 66.9v3.8h25.4v-3.8M99.7 74.5h1.3M102.2 66.9h1.3M200 70.7v14h2.6M200 77.1h2.6M210.2 77.1h1.3"/>
<path d="M18.4 80.9h10.8M27.3 98.7h17.1M27.3 96.1h22.9v2.6h5M47 96.1v18.4M55.2 88.5h-3.8v20.3h-24.1M55.2 93.6h-10.8v20.9M55.2 83.4h-12v10.2h-15.9M71.8 91.1h-3.9v5h-2.5M71.8 96.1h7.6M71.8 84.7h2.5M94.6 91.1h7.6M99.7 84.7h1.3"/>
<path d="M104.8 99.9h1.2v3.9M109.9 91.1h17.7M210.2 84.7h3.8M211.5 91.1v-16.6h24.1v30.5h23.5M214 88.5v-10.1h19v31.7h26.7M216.5 82.2v8.9M219.1 86v2.5M27.3 113.9h30.5v7.6h3.8M27.3 101.2h12.1M27.3 106.3h2.5M27.3 111.4h12.1M27.3 103.8h31.8"/>
<path d="M49.5 108.8v5.7M52.1 103.8v10.7M54.6 113.9v.6M66.7 103.8h7.6M99.7 113.9h1.3M99.7 103.8h7.6M107.3 111.4h-7.6v8.9h11.4M123.8 111.4h-1.2v8.9h-3.9M128.9 119h6.4M135.3 108.8v2.6h-1.3M197.5 113.9v21.6h2.5M208.9 119v16.5h-1.3"/>
<path d="M211.5 116.5v16.5h26.6v-12.7h21.6M216.5 116.5v8.8h1.3M221.6 116.5v1.2M250.8 115.2v12.7M253.4 110.1v17.8M255.9 105v22.9M259.7 115.2h-24.1v14h-21.6v-10.2M19 133h12.1M49.5 124.7h1.3M66 134.9h-15.8v11.4M73 126.6h3.8M73.7 134.9h.6"/>
<path d="M92.1 121.5h1.2M92.1 126.6h6.3M94 126.6v5.1h1.9M99.7 134.9h1.9M135.3 126.6v1.9h2.5M197.5 127.9h2.5M197.5 120.3h2.5M207.6 127.9h3.9M207.6 120.3h6.4M245.7 127.9v-5.1h-3.8v14h-33M245.7 125.3h14M248.3 120.3v7.6"/>
<path d="M52.7 148.8v-10.1h12.7v19h.6M56.5 142.5h-1.3v3.8M73.7 157.7h.6M74.3 145h-5.1v1.3M99.1 145h.6M99.7 157.7h1.9M50.2 176.8v12.7h13.3M52.7 174.2v7.7h17.8M73 167.9h1.3M78.7 176.8h.7M99.7 167.9h.6M70.5 189.5h.6"/>
<path d="M78.1 181.9h1.3M78.1 189.5h1.3M78.7 194.6h.7M94.6 194.6h1.9M94.6 189.5h1.9M102.2 181.9h1.9"/>
</g>
<g fill="none" stroke="#000084" stroke-width=".18">
<path d="M242 33.9l1.2 1.2M243.2 33.9l-1.2 1.2M243.2 33.9l1.2 1.2M243.2 36.5l1.2 1.2M244.4 33.9l-1.2 1.2M244.4 36.5l-1.2 1.2M210.8 84.1l1.3 1.2M212.1 84.1l-1.3 1.2M208.3 119.7l1.2 1.2M209.5 119.7l-1.2 1.2M210.8 119.7l1.3 1.2M212.1 119.7l-1.3 1.2"/>
<path d="M208.3 127.3l1.2 1.2M209.5 127.3l-1.2 1.2"/>
</g>
<g fill="#008400" stroke="#008400" stroke-width=".18">
<circle cx="123.8" cy="22.5" r=".46"/>
<circle cx="131.4" cy="30.1" r=".46"/>
<circle cx="89.5" cy="31.4" r=".46"/>
<circle cx="139.1" cy="22.5" r=".46"/>
<circle cx="139.1" cy="30.1" r=".46"/>
<circle cx="214" cy="84.7" r=".46"/>
<circle cx="197.5" cy="120.3" r=".46"/>
<circle cx="214" cy="120.3" r=".46"/>
<circle cx="197.5" cy="127.9" r=".46"/>
<circle cx="255.9" cy="105" r=".46"/>
<circle cx="253.4" cy="110.1" r=".46"/>
<circle cx="250.8" cy="115.2" r=".46"/>
<circle cx="211.5" cy="77.1" r=".46"/>
<circle cx="200" cy="77.1" r=".46"/>
<circle cx="211.5" cy="127.9" r=".46"/>
<circle cx="245.7" cy="125.3" r=".46"/>
<circle cx="248.3" cy="120.3" r=".46"/>
<circle cx="258.4" cy="34.5" r=".46"/>
<circle cx="97.2" cy="41.5" r=".46"/>
<circle cx="43.2" cy="41.5" r=".46"/>
<circle cx="45.7" cy="49.1" r=".46"/>
<circle cx="48.3" cy="51.7" r=".46"/>
<circle cx="88.3" cy="54.2" r=".46"/>
<circle cx="63.5" cy="66.9" r=".46"/>
<circle cx="88.3" cy="66.9" r=".46"/>
<circle cx="54.6" cy="113.9" r=".46"/>
<circle cx="52.1" cy="103.8" r=".46"/>
<circle cx="47" cy="96.1" r=".46"/>
<circle cx="44.4" cy="98.7" r=".46"/>
<circle cx="49.5" cy="108.8" r=".46"/>
<circle cx="135.3" cy="119" r=".46"/>
<circle cx="135.3" cy="111.4" r=".46"/>
<circle cx="122.6" cy="111.4" r=".46"/>
<circle cx="94" cy="126.6" r=".46"/>
<circle cx="106" cy="103.8" r=".46"/>
<circle cx="99.7" cy="113.9" r=".46"/>
</g>
<use href="#words"/>
</svg>
